VERSION 5.8 ;
BUSBITCHARS "[]" ;
DIVIDERCHAR "/" ;
UNITS
    DATABASE MICRONS 1000 ;
END UNITS

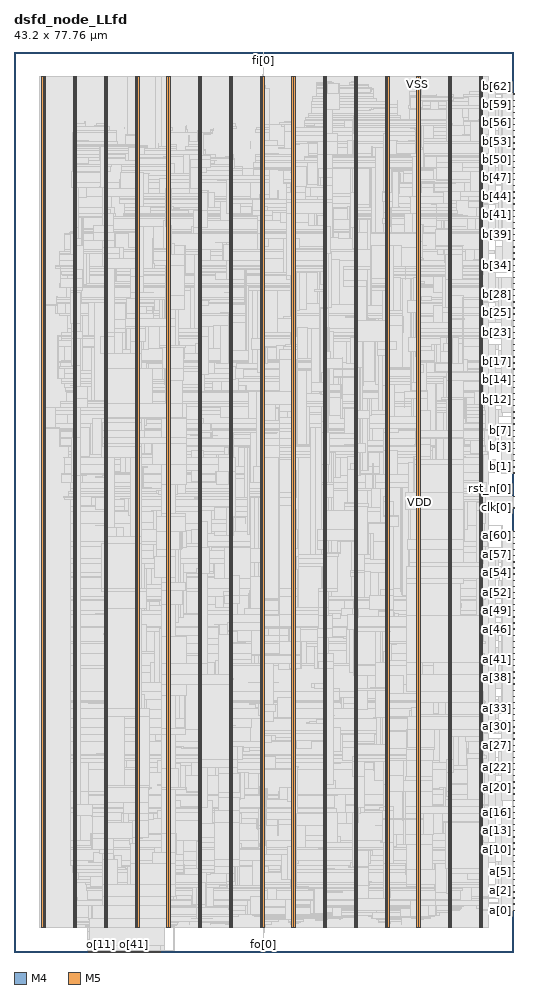
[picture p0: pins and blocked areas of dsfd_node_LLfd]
MACRO dsfd_node_LLfd
  FOREIGN dsfd_node_LLfd 0 0 ;
  CLASS BLOCK ;
  SIZE 43.2 BY 77.76 ;
  PIN a[0]
    DIRECTION INPUT ;
    USE SIGNAL ;
    PORT
      LAYER M4 ;
        RECT  43.116 3.6 43.2 3.624 ;
    END
  END a[0]
  PIN a[10]
    DIRECTION INPUT ;
    USE SIGNAL ;
    PORT
      LAYER M4 ;
        RECT  43.116 8.88 43.2 8.904 ;
    END
  END a[10]
  PIN a[11]
    DIRECTION INPUT ;
    USE SIGNAL ;
    PORT
      LAYER M4 ;
        RECT  43.116 9.408 43.2 9.432 ;
    END
  END a[11]
  PIN a[12]
    DIRECTION INPUT ;
    USE SIGNAL ;
    PORT
      LAYER M4 ;
        RECT  43.116 9.936 43.2 9.96 ;
    END
  END a[12]
  PIN a[13]
    DIRECTION INPUT ;
    USE SIGNAL ;
    PORT
      LAYER M4 ;
        RECT  43.116 10.464 43.2 10.488 ;
    END
  END a[13]
  PIN a[14]
    DIRECTION INPUT ;
    USE SIGNAL ;
    PORT
      LAYER M4 ;
        RECT  43.116 10.992 43.2 11.016 ;
    END
  END a[14]
  PIN a[15]
    DIRECTION INPUT ;
    USE SIGNAL ;
    PORT
      LAYER M4 ;
        RECT  43.116 11.52 43.2 11.544 ;
    END
  END a[15]
  PIN a[16]
    DIRECTION INPUT ;
    USE SIGNAL ;
    PORT
      LAYER M4 ;
        RECT  43.116 12.048 43.2 12.072 ;
    END
  END a[16]
  PIN a[17]
    DIRECTION INPUT ;
    USE SIGNAL ;
    PORT
      LAYER M4 ;
        RECT  43.116 12.576 43.2 12.6 ;
    END
  END a[17]
  PIN a[18]
    DIRECTION INPUT ;
    USE SIGNAL ;
    PORT
      LAYER M4 ;
        RECT  43.116 13.104 43.2 13.128 ;
    END
  END a[18]
  PIN a[19]
    DIRECTION INPUT ;
    USE SIGNAL ;
    PORT
      LAYER M4 ;
        RECT  43.116 13.632 43.2 13.656 ;
    END
  END a[19]
  PIN a[1]
    DIRECTION INPUT ;
    USE SIGNAL ;
    PORT
      LAYER M4 ;
        RECT  43.116 4.128 43.2 4.152 ;
    END
  END a[1]
  PIN a[20]
    DIRECTION INPUT ;
    USE SIGNAL ;
    PORT
      LAYER M4 ;
        RECT  43.116 14.16 43.2 14.184 ;
    END
  END a[20]
  PIN a[21]
    DIRECTION INPUT ;
    USE SIGNAL ;
    PORT
      LAYER M4 ;
        RECT  43.116 14.688 43.2 14.712 ;
    END
  END a[21]
  PIN a[22]
    DIRECTION INPUT ;
    USE SIGNAL ;
    PORT
      LAYER M4 ;
        RECT  43.116 15.216 43.2 15.24 ;
    END
  END a[22]
  PIN a[23]
    DIRECTION INPUT ;
    USE SIGNAL ;
    PORT
      LAYER M4 ;
        RECT  43.116 15.744 43.2 15.768 ;
    END
  END a[23]
  PIN a[24]
    DIRECTION INPUT ;
    USE SIGNAL ;
    PORT
      LAYER M4 ;
        RECT  43.116 16.272 43.2 16.296 ;
    END
  END a[24]
  PIN a[25]
    DIRECTION INPUT ;
    USE SIGNAL ;
    PORT
      LAYER M4 ;
        RECT  43.116 16.8 43.2 16.824 ;
    END
  END a[25]
  PIN a[26]
    DIRECTION INPUT ;
    USE SIGNAL ;
    PORT
      LAYER M4 ;
        RECT  43.116 17.328 43.2 17.352 ;
    END
  END a[26]
  PIN a[27]
    DIRECTION INPUT ;
    USE SIGNAL ;
    PORT
      LAYER M4 ;
        RECT  43.116 17.856 43.2 17.88 ;
    END
  END a[27]
  PIN a[28]
    DIRECTION INPUT ;
    USE SIGNAL ;
    PORT
      LAYER M4 ;
        RECT  43.116 18.384 43.2 18.408 ;
    END
  END a[28]
  PIN a[29]
    DIRECTION INPUT ;
    USE SIGNAL ;
    PORT
      LAYER M4 ;
        RECT  43.116 18.912 43.2 18.936 ;
    END
  END a[29]
  PIN a[2]
    DIRECTION INPUT ;
    USE SIGNAL ;
    PORT
      LAYER M4 ;
        RECT  43.116 4.656 43.2 4.68 ;
    END
  END a[2]
  PIN a[30]
    DIRECTION INPUT ;
    USE SIGNAL ;
    PORT
      LAYER M4 ;
        RECT  43.116 19.44 43.2 19.464 ;
    END
  END a[30]
  PIN a[31]
    DIRECTION INPUT ;
    USE SIGNAL ;
    PORT
      LAYER M4 ;
        RECT  43.116 19.968 43.2 19.992 ;
    END
  END a[31]
  PIN a[32]
    DIRECTION INPUT ;
    USE SIGNAL ;
    PORT
      LAYER M4 ;
        RECT  43.116 20.496 43.2 20.52 ;
    END
  END a[32]
  PIN a[33]
    DIRECTION INPUT ;
    USE SIGNAL ;
    PORT
      LAYER M4 ;
        RECT  43.116 21.024 43.2 21.048 ;
    END
  END a[33]
  PIN a[34]
    DIRECTION INPUT ;
    USE SIGNAL ;
    PORT
      LAYER M4 ;
        RECT  43.116 21.552 43.2 21.576 ;
    END
  END a[34]
  PIN a[35]
    DIRECTION INPUT ;
    USE SIGNAL ;
    PORT
      LAYER M4 ;
        RECT  43.116 22.08 43.2 22.104 ;
    END
  END a[35]
  PIN a[36]
    DIRECTION INPUT ;
    USE SIGNAL ;
    PORT
      LAYER M4 ;
        RECT  43.116 22.608 43.2 22.632 ;
    END
  END a[36]
  PIN a[37]
    DIRECTION INPUT ;
    USE SIGNAL ;
    PORT
      LAYER M4 ;
        RECT  43.116 23.136 43.2 23.16 ;
    END
  END a[37]
  PIN a[38]
    DIRECTION INPUT ;
    USE SIGNAL ;
    PORT
      LAYER M4 ;
        RECT  43.116 23.664 43.2 23.688 ;
    END
  END a[38]
  PIN a[39]
    DIRECTION INPUT ;
    USE SIGNAL ;
    PORT
      LAYER M4 ;
        RECT  43.116 24.192 43.2 24.216 ;
    END
  END a[39]
  PIN a[3]
    DIRECTION INPUT ;
    USE SIGNAL ;
    PORT
      LAYER M4 ;
        RECT  43.116 5.184 43.2 5.208 ;
    END
  END a[3]
  PIN a[40]
    DIRECTION INPUT ;
    USE SIGNAL ;
    PORT
      LAYER M4 ;
        RECT  43.116 24.72 43.2 24.744 ;
    END
  END a[40]
  PIN a[41]
    DIRECTION INPUT ;
    USE SIGNAL ;
    PORT
      LAYER M4 ;
        RECT  43.116 25.248 43.2 25.272 ;
    END
  END a[41]
  PIN a[42]
    DIRECTION INPUT ;
    USE SIGNAL ;
    PORT
      LAYER M4 ;
        RECT  43.116 25.776 43.2 25.8 ;
    END
  END a[42]
  PIN a[43]
    DIRECTION INPUT ;
    USE SIGNAL ;
    PORT
      LAYER M4 ;
        RECT  43.116 26.304 43.2 26.328 ;
    END
  END a[43]
  PIN a[44]
    DIRECTION INPUT ;
    USE SIGNAL ;
    PORT
      LAYER M4 ;
        RECT  43.116 26.832 43.2 26.856 ;
    END
  END a[44]
  PIN a[45]
    DIRECTION INPUT ;
    USE SIGNAL ;
    PORT
      LAYER M4 ;
        RECT  43.116 27.36 43.2 27.384 ;
    END
  END a[45]
  PIN a[46]
    DIRECTION INPUT ;
    USE SIGNAL ;
    PORT
      LAYER M4 ;
        RECT  43.116 27.888 43.2 27.912 ;
    END
  END a[46]
  PIN a[47]
    DIRECTION INPUT ;
    USE SIGNAL ;
    PORT
      LAYER M4 ;
        RECT  43.116 28.416 43.2 28.44 ;
    END
  END a[47]
  PIN a[48]
    DIRECTION INPUT ;
    USE SIGNAL ;
    PORT
      LAYER M4 ;
        RECT  43.116 28.944 43.2 28.968 ;
    END
  END a[48]
  PIN a[49]
    DIRECTION INPUT ;
    USE SIGNAL ;
    PORT
      LAYER M4 ;
        RECT  43.116 29.472 43.2 29.496 ;
    END
  END a[49]
  PIN a[4]
    DIRECTION INPUT ;
    USE SIGNAL ;
    PORT
      LAYER M4 ;
        RECT  43.116 5.712 43.2 5.736 ;
    END
  END a[4]
  PIN a[50]
    DIRECTION INPUT ;
    USE SIGNAL ;
    PORT
      LAYER M4 ;
        RECT  43.116 30 43.2 30.024 ;
    END
  END a[50]
  PIN a[51]
    DIRECTION INPUT ;
    USE SIGNAL ;
    PORT
      LAYER M4 ;
        RECT  43.116 30.528 43.2 30.552 ;
    END
  END a[51]
  PIN a[52]
    DIRECTION INPUT ;
    USE SIGNAL ;
    PORT
      LAYER M4 ;
        RECT  43.116 31.056 43.2 31.08 ;
    END
  END a[52]
  PIN a[53]
    DIRECTION INPUT ;
    USE SIGNAL ;
    PORT
      LAYER M4 ;
        RECT  43.116 31.584 43.2 31.608 ;
    END
  END a[53]
  PIN a[54]
    DIRECTION INPUT ;
    USE SIGNAL ;
    PORT
      LAYER M4 ;
        RECT  43.116 32.112 43.2 32.136 ;
    END
  END a[54]
  PIN a[55]
    DIRECTION INPUT ;
    USE SIGNAL ;
    PORT
      LAYER M4 ;
        RECT  43.116 32.64 43.2 32.664 ;
    END
  END a[55]
  PIN a[56]
    DIRECTION INPUT ;
    USE SIGNAL ;
    PORT
      LAYER M4 ;
        RECT  43.116 33.168 43.2 33.192 ;
    END
  END a[56]
  PIN a[57]
    DIRECTION INPUT ;
    USE SIGNAL ;
    PORT
      LAYER M4 ;
        RECT  43.116 33.696 43.2 33.72 ;
    END
  END a[57]
  PIN a[58]
    DIRECTION INPUT ;
    USE SIGNAL ;
    PORT
      LAYER M4 ;
        RECT  43.116 34.224 43.2 34.248 ;
    END
  END a[58]
  PIN a[59]
    DIRECTION INPUT ;
    USE SIGNAL ;
    PORT
      LAYER M4 ;
        RECT  43.116 34.752 43.2 34.776 ;
    END
  END a[59]
  PIN a[5]
    DIRECTION INPUT ;
    USE SIGNAL ;
    PORT
      LAYER M4 ;
        RECT  43.116 6.24 43.2 6.264 ;
    END
  END a[5]
  PIN a[60]
    DIRECTION INPUT ;
    USE SIGNAL ;
    PORT
      LAYER M4 ;
        RECT  43.116 35.28 43.2 35.304 ;
    END
  END a[60]
  PIN a[61]
    DIRECTION INPUT ;
    USE SIGNAL ;
    PORT
      LAYER M4 ;
        RECT  43.116 35.808 43.2 35.832 ;
    END
  END a[61]
  PIN a[62]
    DIRECTION INPUT ;
    USE SIGNAL ;
    PORT
      LAYER M4 ;
        RECT  43.116 36.336 43.2 36.36 ;
    END
  END a[62]
  PIN a[6]
    DIRECTION INPUT ;
    USE SIGNAL ;
    PORT
      LAYER M4 ;
        RECT  43.116 6.768 43.2 6.792 ;
    END
  END a[6]
  PIN a[7]
    DIRECTION INPUT ;
    USE SIGNAL ;
    PORT
      LAYER M4 ;
        RECT  43.116 7.296 43.2 7.32 ;
    END
  END a[7]
  PIN a[8]
    DIRECTION INPUT ;
    USE SIGNAL ;
    PORT
      LAYER M4 ;
        RECT  43.116 7.824 43.2 7.848 ;
    END
  END a[8]
  PIN a[9]
    DIRECTION INPUT ;
    USE SIGNAL ;
    PORT
      LAYER M4 ;
        RECT  43.116 8.352 43.2 8.376 ;
    END
  END a[9]
  PIN b[0]
    DIRECTION INPUT ;
    USE SIGNAL ;
    PORT
      LAYER M4 ;
        RECT  43.116 41.376 43.2 41.4 ;
    END
  END b[0]
  PIN b[10]
    DIRECTION INPUT ;
    USE SIGNAL ;
    PORT
      LAYER M4 ;
        RECT  43.116 46.656 43.2 46.68 ;
    END
  END b[10]
  PIN b[11]
    DIRECTION INPUT ;
    USE SIGNAL ;
    PORT
      LAYER M4 ;
        RECT  43.116 47.184 43.2 47.208 ;
    END
  END b[11]
  PIN b[12]
    DIRECTION INPUT ;
    USE SIGNAL ;
    PORT
      LAYER M4 ;
        RECT  43.116 47.712 43.2 47.736 ;
    END
  END b[12]
  PIN b[13]
    DIRECTION INPUT ;
    USE SIGNAL ;
    PORT
      LAYER M4 ;
        RECT  43.116 48.24 43.2 48.264 ;
    END
  END b[13]
  PIN b[14]
    DIRECTION INPUT ;
    USE SIGNAL ;
    PORT
      LAYER M4 ;
        RECT  43.116 48.768 43.2 48.792 ;
    END
  END b[14]
  PIN b[15]
    DIRECTION INPUT ;
    USE SIGNAL ;
    PORT
      LAYER M4 ;
        RECT  43.116 49.296 43.2 49.32 ;
    END
  END b[15]
  PIN b[16]
    DIRECTION INPUT ;
    USE SIGNAL ;
    PORT
      LAYER M4 ;
        RECT  43.116 49.824 43.2 49.848 ;
    END
  END b[16]
  PIN b[17]
    DIRECTION INPUT ;
    USE SIGNAL ;
    PORT
      LAYER M4 ;
        RECT  43.116 50.352 43.2 50.376 ;
    END
  END b[17]
  PIN b[18]
    DIRECTION INPUT ;
    USE SIGNAL ;
    PORT
      LAYER M4 ;
        RECT  43.116 50.88 43.2 50.904 ;
    END
  END b[18]
  PIN b[19]
    DIRECTION INPUT ;
    USE SIGNAL ;
    PORT
      LAYER M4 ;
        RECT  43.116 51.408 43.2 51.432 ;
    END
  END b[19]
  PIN b[1]
    DIRECTION INPUT ;
    USE SIGNAL ;
    PORT
      LAYER M4 ;
        RECT  43.116 41.904 43.2 41.928 ;
    END
  END b[1]
  PIN b[20]
    DIRECTION INPUT ;
    USE SIGNAL ;
    PORT
      LAYER M4 ;
        RECT  43.116 51.936 43.2 51.96 ;
    END
  END b[20]
  PIN b[21]
    DIRECTION INPUT ;
    USE SIGNAL ;
    PORT
      LAYER M4 ;
        RECT  43.116 52.464 43.2 52.488 ;
    END
  END b[21]
  PIN b[22]
    DIRECTION INPUT ;
    USE SIGNAL ;
    PORT
      LAYER M4 ;
        RECT  43.116 52.992 43.2 53.016 ;
    END
  END b[22]
  PIN b[23]
    DIRECTION INPUT ;
    USE SIGNAL ;
    PORT
      LAYER M4 ;
        RECT  43.116 53.52 43.2 53.544 ;
    END
  END b[23]
  PIN b[24]
    DIRECTION INPUT ;
    USE SIGNAL ;
    PORT
      LAYER M4 ;
        RECT  43.116 54.048 43.2 54.072 ;
    END
  END b[24]
  PIN b[25]
    DIRECTION INPUT ;
    USE SIGNAL ;
    PORT
      LAYER M4 ;
        RECT  43.116 54.576 43.2 54.6 ;
    END
  END b[25]
  PIN b[26]
    DIRECTION INPUT ;
    USE SIGNAL ;
    PORT
      LAYER M4 ;
        RECT  43.116 55.104 43.2 55.128 ;
    END
  END b[26]
  PIN b[27]
    DIRECTION INPUT ;
    USE SIGNAL ;
    PORT
      LAYER M4 ;
        RECT  43.116 55.632 43.2 55.656 ;
    END
  END b[27]
  PIN b[28]
    DIRECTION INPUT ;
    USE SIGNAL ;
    PORT
      LAYER M4 ;
        RECT  43.116 56.16 43.2 56.184 ;
    END
  END b[28]
  PIN b[29]
    DIRECTION INPUT ;
    USE SIGNAL ;
    PORT
      LAYER M4 ;
        RECT  43.116 56.688 43.2 56.712 ;
    END
  END b[29]
  PIN b[2]
    DIRECTION INPUT ;
    USE SIGNAL ;
    PORT
      LAYER M4 ;
        RECT  43.116 42.432 43.2 42.456 ;
    END
  END b[2]
  PIN b[30]
    DIRECTION INPUT ;
    USE SIGNAL ;
    PORT
      LAYER M4 ;
        RECT  43.116 57.216 43.2 57.24 ;
    END
  END b[30]
  PIN b[31]
    DIRECTION INPUT ;
    USE SIGNAL ;
    PORT
      LAYER M4 ;
        RECT  43.116 57.744 43.2 57.768 ;
    END
  END b[31]
  PIN b[32]
    DIRECTION INPUT ;
    USE SIGNAL ;
    PORT
      LAYER M4 ;
        RECT  43.116 58.272 43.2 58.296 ;
    END
  END b[32]
  PIN b[33]
    DIRECTION INPUT ;
    USE SIGNAL ;
    PORT
      LAYER M4 ;
        RECT  43.116 58.8 43.2 58.824 ;
    END
  END b[33]
  PIN b[34]
    DIRECTION INPUT ;
    USE SIGNAL ;
    PORT
      LAYER M4 ;
        RECT  43.116 59.328 43.2 59.352 ;
    END
  END b[34]
  PIN b[35]
    DIRECTION INPUT ;
    USE SIGNAL ;
    PORT
      LAYER M4 ;
        RECT  43.116 59.856 43.2 59.88 ;
    END
  END b[35]
  PIN b[36]
    DIRECTION INPUT ;
    USE SIGNAL ;
    PORT
      LAYER M4 ;
        RECT  43.116 60.384 43.2 60.408 ;
    END
  END b[36]
  PIN b[37]
    DIRECTION INPUT ;
    USE SIGNAL ;
    PORT
      LAYER M4 ;
        RECT  43.116 60.912 43.2 60.936 ;
    END
  END b[37]
  PIN b[38]
    DIRECTION INPUT ;
    USE SIGNAL ;
    PORT
      LAYER M4 ;
        RECT  43.116 61.44 43.2 61.464 ;
    END
  END b[38]
  PIN b[39]
    DIRECTION INPUT ;
    USE SIGNAL ;
    PORT
      LAYER M4 ;
        RECT  43.116 61.968 43.2 61.992 ;
    END
  END b[39]
  PIN b[3]
    DIRECTION INPUT ;
    USE SIGNAL ;
    PORT
      LAYER M4 ;
        RECT  43.116 42.96 43.2 42.984 ;
    END
  END b[3]
  PIN b[40]
    DIRECTION INPUT ;
    USE SIGNAL ;
    PORT
      LAYER M4 ;
        RECT  43.116 62.496 43.2 62.52 ;
    END
  END b[40]
  PIN b[41]
    DIRECTION INPUT ;
    USE SIGNAL ;
    PORT
      LAYER M4 ;
        RECT  43.116 63.024 43.2 63.048 ;
    END
  END b[41]
  PIN b[42]
    DIRECTION INPUT ;
    USE SIGNAL ;
    PORT
      LAYER M4 ;
        RECT  43.116 63.552 43.2 63.576 ;
    END
  END b[42]
  PIN b[43]
    DIRECTION INPUT ;
    USE SIGNAL ;
    PORT
      LAYER M4 ;
        RECT  43.116 64.08 43.2 64.104 ;
    END
  END b[43]
  PIN b[44]
    DIRECTION INPUT ;
    USE SIGNAL ;
    PORT
      LAYER M4 ;
        RECT  43.116 64.608 43.2 64.632 ;
    END
  END b[44]
  PIN b[45]
    DIRECTION INPUT ;
    USE SIGNAL ;
    PORT
      LAYER M4 ;
        RECT  43.116 65.136 43.2 65.16 ;
    END
  END b[45]
  PIN b[46]
    DIRECTION INPUT ;
    USE SIGNAL ;
    PORT
      LAYER M4 ;
        RECT  43.116 65.664 43.2 65.688 ;
    END
  END b[46]
  PIN b[47]
    DIRECTION INPUT ;
    USE SIGNAL ;
    PORT
      LAYER M4 ;
        RECT  43.116 66.192 43.2 66.216 ;
    END
  END b[47]
  PIN b[48]
    DIRECTION INPUT ;
    USE SIGNAL ;
    PORT
      LAYER M4 ;
        RECT  43.116 66.72 43.2 66.744 ;
    END
  END b[48]
  PIN b[49]
    DIRECTION INPUT ;
    USE SIGNAL ;
    PORT
      LAYER M4 ;
        RECT  43.116 67.248 43.2 67.272 ;
    END
  END b[49]
  PIN b[4]
    DIRECTION INPUT ;
    USE SIGNAL ;
    PORT
      LAYER M4 ;
        RECT  43.116 43.488 43.2 43.512 ;
    END
  END b[4]
  PIN b[50]
    DIRECTION INPUT ;
    USE SIGNAL ;
    PORT
      LAYER M4 ;
        RECT  43.116 67.776 43.2 67.8 ;
    END
  END b[50]
  PIN b[51]
    DIRECTION INPUT ;
    USE SIGNAL ;
    PORT
      LAYER M4 ;
        RECT  43.116 68.304 43.2 68.328 ;
    END
  END b[51]
  PIN b[52]
    DIRECTION INPUT ;
    USE SIGNAL ;
    PORT
      LAYER M4 ;
        RECT  43.116 68.832 43.2 68.856 ;
    END
  END b[52]
  PIN b[53]
    DIRECTION INPUT ;
    USE SIGNAL ;
    PORT
      LAYER M4 ;
        RECT  43.116 69.36 43.2 69.384 ;
    END
  END b[53]
  PIN b[54]
    DIRECTION INPUT ;
    USE SIGNAL ;
    PORT
      LAYER M4 ;
        RECT  43.116 69.888 43.2 69.912 ;
    END
  END b[54]
  PIN b[55]
    DIRECTION INPUT ;
    USE SIGNAL ;
    PORT
      LAYER M4 ;
        RECT  43.116 70.416 43.2 70.44 ;
    END
  END b[55]
  PIN b[56]
    DIRECTION INPUT ;
    USE SIGNAL ;
    PORT
      LAYER M4 ;
        RECT  43.116 70.944 43.2 70.968 ;
    END
  END b[56]
  PIN b[57]
    DIRECTION INPUT ;
    USE SIGNAL ;
    PORT
      LAYER M4 ;
        RECT  43.116 71.472 43.2 71.496 ;
    END
  END b[57]
  PIN b[58]
    DIRECTION INPUT ;
    USE SIGNAL ;
    PORT
      LAYER M4 ;
        RECT  43.116 72 43.2 72.024 ;
    END
  END b[58]
  PIN b[59]
    DIRECTION INPUT ;
    USE SIGNAL ;
    PORT
      LAYER M4 ;
        RECT  43.116 72.528 43.2 72.552 ;
    END
  END b[59]
  PIN b[5]
    DIRECTION INPUT ;
    USE SIGNAL ;
    PORT
      LAYER M4 ;
        RECT  43.116 44.016 43.2 44.04 ;
    END
  END b[5]
  PIN b[60]
    DIRECTION INPUT ;
    USE SIGNAL ;
    PORT
      LAYER M4 ;
        RECT  43.116 73.056 43.2 73.08 ;
    END
  END b[60]
  PIN b[61]
    DIRECTION INPUT ;
    USE SIGNAL ;
    PORT
      LAYER M4 ;
        RECT  43.116 73.584 43.2 73.608 ;
    END
  END b[61]
  PIN b[62]
    DIRECTION INPUT ;
    USE SIGNAL ;
    PORT
      LAYER M4 ;
        RECT  43.116 74.112 43.2 74.136 ;
    END
  END b[62]
  PIN b[6]
    DIRECTION INPUT ;
    USE SIGNAL ;
    PORT
      LAYER M4 ;
        RECT  43.116 44.544 43.2 44.568 ;
    END
  END b[6]
  PIN b[7]
    DIRECTION INPUT ;
    USE SIGNAL ;
    PORT
      LAYER M4 ;
        RECT  43.116 45.072 43.2 45.096 ;
    END
  END b[7]
  PIN b[8]
    DIRECTION INPUT ;
    USE SIGNAL ;
    PORT
      LAYER M4 ;
        RECT  43.116 45.6 43.2 45.624 ;
    END
  END b[8]
  PIN b[9]
    DIRECTION INPUT ;
    USE SIGNAL ;
    PORT
      LAYER M4 ;
        RECT  43.116 46.128 43.2 46.152 ;
    END
  END b[9]
  PIN clk[0]
    DIRECTION INPUT ;
    USE SIGNAL ;
    PORT
      LAYER M4 ;
        RECT  43.116 38.352 43.2 38.376 ;
    END
  END clk[0]
  PIN fi[0]
    DIRECTION INPUT ;
    USE SIGNAL ;
    PORT
      LAYER M5 ;
        RECT  21.552 77.676 21.576 77.76 ;
    END
  END fi[0]
  PIN fo[0]
    DIRECTION OUTPUT ;
    USE SIGNAL ;
    PORT
      LAYER M5 ;
        RECT  21.552 0 21.576 0.084 ;
    END
  END fo[0]
  PIN o[0]
    DIRECTION OUTPUT ;
    USE SIGNAL ;
    PORT
      LAYER M5 ;
        RECT  6.432 0 6.456 0.084 ;
    END
  END o[0]
  PIN o[10]
    DIRECTION OUTPUT ;
    USE SIGNAL ;
    PORT
      LAYER M5 ;
        RECT  7.392 0 7.416 0.084 ;
    END
  END o[10]
  PIN o[11]
    DIRECTION OUTPUT ;
    USE SIGNAL ;
    PORT
      LAYER M5 ;
        RECT  7.488 0 7.512 0.084 ;
    END
  END o[11]
  PIN o[12]
    DIRECTION OUTPUT ;
    USE SIGNAL ;
    PORT
      LAYER M5 ;
        RECT  7.584 0 7.608 0.084 ;
    END
  END o[12]
  PIN o[13]
    DIRECTION OUTPUT ;
    USE SIGNAL ;
    PORT
      LAYER M5 ;
        RECT  7.68 0 7.704 0.084 ;
    END
  END o[13]
  PIN o[14]
    DIRECTION OUTPUT ;
    USE SIGNAL ;
    PORT
      LAYER M5 ;
        RECT  7.776 0 7.8 0.084 ;
    END
  END o[14]
  PIN o[15]
    DIRECTION OUTPUT ;
    USE SIGNAL ;
    PORT
      LAYER M5 ;
        RECT  7.872 0 7.896 0.084 ;
    END
  END o[15]
  PIN o[16]
    DIRECTION OUTPUT ;
    USE SIGNAL ;
    PORT
      LAYER M5 ;
        RECT  7.968 0 7.992 0.084 ;
    END
  END o[16]
  PIN o[17]
    DIRECTION OUTPUT ;
    USE SIGNAL ;
    PORT
      LAYER M5 ;
        RECT  8.064 0 8.088 0.084 ;
    END
  END o[17]
  PIN o[18]
    DIRECTION OUTPUT ;
    USE SIGNAL ;
    PORT
      LAYER M5 ;
        RECT  8.16 0 8.184 0.084 ;
    END
  END o[18]
  PIN o[19]
    DIRECTION OUTPUT ;
    USE SIGNAL ;
    PORT
      LAYER M5 ;
        RECT  8.256 0 8.28 0.084 ;
    END
  END o[19]
  PIN o[1]
    DIRECTION OUTPUT ;
    USE SIGNAL ;
    PORT
      LAYER M5 ;
        RECT  6.528 0 6.552 0.084 ;
    END
  END o[1]
  PIN o[20]
    DIRECTION OUTPUT ;
    USE SIGNAL ;
    PORT
      LAYER M5 ;
        RECT  8.352 0 8.376 0.084 ;
    END
  END o[20]
  PIN o[21]
    DIRECTION OUTPUT ;
    USE SIGNAL ;
    PORT
      LAYER M5 ;
        RECT  8.448 0 8.472 0.084 ;
    END
  END o[21]
  PIN o[22]
    DIRECTION OUTPUT ;
    USE SIGNAL ;
    PORT
      LAYER M5 ;
        RECT  8.544 0 8.568 0.084 ;
    END
  END o[22]
  PIN o[23]
    DIRECTION OUTPUT ;
    USE SIGNAL ;
    PORT
      LAYER M5 ;
        RECT  8.64 0 8.664 0.084 ;
    END
  END o[23]
  PIN o[24]
    DIRECTION OUTPUT ;
    USE SIGNAL ;
    PORT
      LAYER M5 ;
        RECT  8.736 0 8.76 0.084 ;
    END
  END o[24]
  PIN o[25]
    DIRECTION OUTPUT ;
    USE SIGNAL ;
    PORT
      LAYER M5 ;
        RECT  8.832 0 8.856 0.084 ;
    END
  END o[25]
  PIN o[26]
    DIRECTION OUTPUT ;
    USE SIGNAL ;
    PORT
      LAYER M5 ;
        RECT  8.928 0 8.952 0.084 ;
    END
  END o[26]
  PIN o[27]
    DIRECTION OUTPUT ;
    USE SIGNAL ;
    PORT
      LAYER M5 ;
        RECT  9.024 0 9.048 0.084 ;
    END
  END o[27]
  PIN o[28]
    DIRECTION OUTPUT ;
    USE SIGNAL ;
    PORT
      LAYER M5 ;
        RECT  9.12 0 9.144 0.084 ;
    END
  END o[28]
  PIN o[29]
    DIRECTION OUTPUT ;
    USE SIGNAL ;
    PORT
      LAYER M5 ;
        RECT  9.216 0 9.24 0.084 ;
    END
  END o[29]
  PIN o[2]
    DIRECTION OUTPUT ;
    USE SIGNAL ;
    PORT
      LAYER M5 ;
        RECT  6.624 0 6.648 0.084 ;
    END
  END o[2]
  PIN o[30]
    DIRECTION OUTPUT ;
    USE SIGNAL ;
    PORT
      LAYER M5 ;
        RECT  9.312 0 9.336 0.084 ;
    END
  END o[30]
  PIN o[31]
    DIRECTION OUTPUT ;
    USE SIGNAL ;
    PORT
      LAYER M5 ;
        RECT  9.408 0 9.432 0.084 ;
    END
  END o[31]
  PIN o[32]
    DIRECTION OUTPUT ;
    USE SIGNAL ;
    PORT
      LAYER M5 ;
        RECT  9.504 0 9.528 0.084 ;
    END
  END o[32]
  PIN o[33]
    DIRECTION OUTPUT ;
    USE SIGNAL ;
    PORT
      LAYER M5 ;
        RECT  9.6 0 9.624 0.084 ;
    END
  END o[33]
  PIN o[34]
    DIRECTION OUTPUT ;
    USE SIGNAL ;
    PORT
      LAYER M5 ;
        RECT  9.696 0 9.72 0.084 ;
    END
  END o[34]
  PIN o[35]
    DIRECTION OUTPUT ;
    USE SIGNAL ;
    PORT
      LAYER M5 ;
        RECT  9.792 0 9.816 0.084 ;
    END
  END o[35]
  PIN o[36]
    DIRECTION OUTPUT ;
    USE SIGNAL ;
    PORT
      LAYER M5 ;
        RECT  9.888 0 9.912 0.084 ;
    END
  END o[36]
  PIN o[37]
    DIRECTION OUTPUT ;
    USE SIGNAL ;
    PORT
      LAYER M5 ;
        RECT  9.984 0 10.008 0.084 ;
    END
  END o[37]
  PIN o[38]
    DIRECTION OUTPUT ;
    USE SIGNAL ;
    PORT
      LAYER M5 ;
        RECT  10.08 0 10.104 0.084 ;
    END
  END o[38]
  PIN o[39]
    DIRECTION OUTPUT ;
    USE SIGNAL ;
    PORT
      LAYER M5 ;
        RECT  10.176 0 10.2 0.084 ;
    END
  END o[39]
  PIN o[3]
    DIRECTION OUTPUT ;
    USE SIGNAL ;
    PORT
      LAYER M5 ;
        RECT  6.72 0 6.744 0.084 ;
    END
  END o[3]
  PIN o[40]
    DIRECTION OUTPUT ;
    USE SIGNAL ;
    PORT
      LAYER M5 ;
        RECT  10.272 0 10.296 0.084 ;
    END
  END o[40]
  PIN o[41]
    DIRECTION OUTPUT ;
    USE SIGNAL ;
    PORT
      LAYER M5 ;
        RECT  10.368 0 10.392 0.084 ;
    END
  END o[41]
  PIN o[42]
    DIRECTION OUTPUT ;
    USE SIGNAL ;
    PORT
      LAYER M5 ;
        RECT  10.464 0 10.488 0.084 ;
    END
  END o[42]
  PIN o[43]
    DIRECTION OUTPUT ;
    USE SIGNAL ;
    PORT
      LAYER M5 ;
        RECT  10.56 0 10.584 0.084 ;
    END
  END o[43]
  PIN o[44]
    DIRECTION OUTPUT ;
    USE SIGNAL ;
    PORT
      LAYER M5 ;
        RECT  10.656 0 10.68 0.084 ;
    END
  END o[44]
  PIN o[45]
    DIRECTION OUTPUT ;
    USE SIGNAL ;
    PORT
      LAYER M5 ;
        RECT  10.752 0 10.776 0.084 ;
    END
  END o[45]
  PIN o[46]
    DIRECTION OUTPUT ;
    USE SIGNAL ;
    PORT
      LAYER M5 ;
        RECT  10.848 0 10.872 0.084 ;
    END
  END o[46]
  PIN o[47]
    DIRECTION OUTPUT ;
    USE SIGNAL ;
    PORT
      LAYER M5 ;
        RECT  10.944 0 10.968 0.084 ;
    END
  END o[47]
  PIN o[48]
    DIRECTION OUTPUT ;
    USE SIGNAL ;
    PORT
      LAYER M5 ;
        RECT  11.04 0 11.064 0.084 ;
    END
  END o[48]
  PIN o[49]
    DIRECTION OUTPUT ;
    USE SIGNAL ;
    PORT
      LAYER M5 ;
        RECT  11.136 0 11.16 0.084 ;
    END
  END o[49]
  PIN o[4]
    DIRECTION OUTPUT ;
    USE SIGNAL ;
    PORT
      LAYER M5 ;
        RECT  6.816 0 6.84 0.084 ;
    END
  END o[4]
  PIN o[50]
    DIRECTION OUTPUT ;
    USE SIGNAL ;
    PORT
      LAYER M5 ;
        RECT  11.232 0 11.256 0.084 ;
    END
  END o[50]
  PIN o[51]
    DIRECTION OUTPUT ;
    USE SIGNAL ;
    PORT
      LAYER M5 ;
        RECT  11.328 0 11.352 0.084 ;
    END
  END o[51]
  PIN o[52]
    DIRECTION OUTPUT ;
    USE SIGNAL ;
    PORT
      LAYER M5 ;
        RECT  11.424 0 11.448 0.084 ;
    END
  END o[52]
  PIN o[53]
    DIRECTION OUTPUT ;
    USE SIGNAL ;
    PORT
      LAYER M5 ;
        RECT  11.52 0 11.544 0.084 ;
    END
  END o[53]
  PIN o[54]
    DIRECTION OUTPUT ;
    USE SIGNAL ;
    PORT
      LAYER M5 ;
        RECT  11.616 0 11.64 0.084 ;
    END
  END o[54]
  PIN o[55]
    DIRECTION OUTPUT ;
    USE SIGNAL ;
    PORT
      LAYER M5 ;
        RECT  11.712 0 11.736 0.084 ;
    END
  END o[55]
  PIN o[56]
    DIRECTION OUTPUT ;
    USE SIGNAL ;
    PORT
      LAYER M5 ;
        RECT  11.808 0 11.832 0.084 ;
    END
  END o[56]
  PIN o[57]
    DIRECTION OUTPUT ;
    USE SIGNAL ;
    PORT
      LAYER M5 ;
        RECT  11.904 0 11.928 0.084 ;
    END
  END o[57]
  PIN o[58]
    DIRECTION OUTPUT ;
    USE SIGNAL ;
    PORT
      LAYER M5 ;
        RECT  12 0 12.024 0.084 ;
    END
  END o[58]
  PIN o[59]
    DIRECTION OUTPUT ;
    USE SIGNAL ;
    PORT
      LAYER M5 ;
        RECT  12.096 0 12.12 0.084 ;
    END
  END o[59]
  PIN o[5]
    DIRECTION OUTPUT ;
    USE SIGNAL ;
    PORT
      LAYER M5 ;
        RECT  6.912 0 6.936 0.084 ;
    END
  END o[5]
  PIN o[60]
    DIRECTION OUTPUT ;
    USE SIGNAL ;
    PORT
      LAYER M5 ;
        RECT  12.192 0 12.216 0.084 ;
    END
  END o[60]
  PIN o[61]
    DIRECTION OUTPUT ;
    USE SIGNAL ;
    PORT
      LAYER M5 ;
        RECT  12.288 0 12.312 0.084 ;
    END
  END o[61]
  PIN o[62]
    DIRECTION OUTPUT ;
    USE SIGNAL ;
    PORT
      LAYER M5 ;
        RECT  12.384 0 12.408 0.084 ;
    END
  END o[62]
  PIN o[63]
    DIRECTION OUTPUT ;
    USE SIGNAL ;
    PORT
      LAYER M5 ;
        RECT  12.48 0 12.504 0.084 ;
    END
  END o[63]
  PIN o[64]
    DIRECTION OUTPUT ;
    USE SIGNAL ;
    PORT
      LAYER M5 ;
        RECT  12.576 0 12.6 0.084 ;
    END
  END o[64]
  PIN o[65]
    DIRECTION OUTPUT ;
    USE SIGNAL ;
    PORT
      LAYER M5 ;
        RECT  12.672 0 12.696 0.084 ;
    END
  END o[65]
  PIN o[6]
    DIRECTION OUTPUT ;
    USE SIGNAL ;
    PORT
      LAYER M5 ;
        RECT  7.008 0 7.032 0.084 ;
    END
  END o[6]
  PIN o[7]
    DIRECTION OUTPUT ;
    USE SIGNAL ;
    PORT
      LAYER M5 ;
        RECT  7.104 0 7.128 0.084 ;
    END
  END o[7]
  PIN o[8]
    DIRECTION OUTPUT ;
    USE SIGNAL ;
    PORT
      LAYER M5 ;
        RECT  7.2 0 7.224 0.084 ;
    END
  END o[8]
  PIN o[9]
    DIRECTION OUTPUT ;
    USE SIGNAL ;
    PORT
      LAYER M5 ;
        RECT  7.296 0 7.32 0.084 ;
    END
  END o[9]
  PIN rst_n[0]
    DIRECTION INPUT ;
    USE SIGNAL ;
    PORT
      LAYER M4 ;
        RECT  43.116 39.36 43.2 39.384 ;
    END
  END rst_n[0]
  PIN VDD
    DIRECTION INOUT ;
    USE POWER ;
    PORT
      LAYER M5 ;
        RECT  40.392 2.151 40.512 75.609 ;
        RECT  37.692 2.151 37.812 75.609 ;
        RECT  34.992 2.151 35.112 75.609 ;
        RECT  32.292 2.151 32.412 75.609 ;
        RECT  29.592 2.151 29.712 75.609 ;
        RECT  26.892 2.151 27.012 75.609 ;
        RECT  24.192 2.151 24.312 75.609 ;
        RECT  21.492 2.151 21.612 75.609 ;
        RECT  18.792 2.151 18.912 75.609 ;
        RECT  16.092 2.151 16.212 75.609 ;
        RECT  13.392 2.151 13.512 75.609 ;
        RECT  10.692 2.151 10.812 75.609 ;
        RECT  7.992 2.151 8.112 75.609 ;
        RECT  5.292 2.151 5.412 75.609 ;
        RECT  2.592 2.151 2.712 75.609 ;
    END
  END VDD
  PIN VSS
    DIRECTION INOUT ;
    USE GROUND ;
    PORT
      LAYER M5 ;
        RECT  40.2 2.137 40.32 75.623 ;
        RECT  37.5 2.137 37.62 75.623 ;
        RECT  34.8 2.137 34.92 75.623 ;
        RECT  32.1 2.137 32.22 75.623 ;
        RECT  29.4 2.137 29.52 75.623 ;
        RECT  26.7 2.137 26.82 75.623 ;
        RECT  24 2.137 24.12 75.623 ;
        RECT  21.3 2.137 21.42 75.623 ;
        RECT  18.6 2.137 18.72 75.623 ;
        RECT  15.9 2.137 16.02 75.623 ;
        RECT  13.2 2.137 13.32 75.623 ;
        RECT  10.5 2.137 10.62 75.623 ;
        RECT  7.8 2.137 7.92 75.623 ;
        RECT  5.1 2.137 5.22 75.623 ;
        RECT  2.4 2.137 2.52 75.623 ;
    END
  END VSS
  OBS
    LAYER RVTN ;
     RECT  2.16 2.16 41.04 2.295 ;
     RECT  2.16 2.565 41.04 2.835 ;
     RECT  2.16 3.105 41.04 3.375 ;
     RECT  2.16 3.645 41.04 3.915 ;
     RECT  2.16 4.185 41.04 4.455 ;
     RECT  2.16 4.725 41.04 4.995 ;
     RECT  2.16 5.265 41.04 5.535 ;
     RECT  2.16 5.805 41.04 6.075 ;
     RECT  2.16 6.345 41.04 6.615 ;
     RECT  2.16 6.885 41.04 7.155 ;
     RECT  2.16 7.425 41.04 7.695 ;
     RECT  2.16 7.965 41.04 8.235 ;
     RECT  2.16 8.505 41.04 8.775 ;
     RECT  2.16 9.045 41.04 9.315 ;
     RECT  2.16 9.585 41.04 9.855 ;
     RECT  2.16 10.125 41.04 10.395 ;
     RECT  2.16 10.665 41.04 10.935 ;
     RECT  2.16 11.205 41.04 11.475 ;
     RECT  2.16 11.745 41.04 12.015 ;
     RECT  2.16 12.285 41.04 12.555 ;
     RECT  2.16 12.825 41.04 13.095 ;
     RECT  2.16 13.365 41.04 13.635 ;
     RECT  2.16 13.905 41.04 14.175 ;
     RECT  2.16 14.445 41.04 14.715 ;
     RECT  2.16 14.985 41.04 15.255 ;
     RECT  2.16 15.525 41.04 15.795 ;
     RECT  2.16 16.065 41.04 16.335 ;
     RECT  2.16 16.605 41.04 16.875 ;
     RECT  2.16 17.145 41.04 17.415 ;
     RECT  2.16 17.685 41.04 17.955 ;
     RECT  2.16 18.225 41.04 18.495 ;
     RECT  2.16 18.765 41.04 19.035 ;
     RECT  2.16 19.305 41.04 19.575 ;
     RECT  2.16 19.845 41.04 20.115 ;
     RECT  2.16 20.385 41.04 20.655 ;
     RECT  2.16 20.925 41.04 21.195 ;
     RECT  2.16 21.465 41.04 21.735 ;
     RECT  2.16 22.005 41.04 22.275 ;
     RECT  2.16 22.545 41.04 22.815 ;
     RECT  2.16 23.085 41.04 23.355 ;
     RECT  2.16 23.625 41.04 23.895 ;
     RECT  2.16 24.165 41.04 24.435 ;
     RECT  2.16 24.705 41.04 24.975 ;
     RECT  2.16 25.245 41.04 25.515 ;
     RECT  2.16 25.785 41.04 26.055 ;
     RECT  2.16 26.325 41.04 26.595 ;
     RECT  2.16 26.865 41.04 27.135 ;
     RECT  2.16 27.405 41.04 27.675 ;
     RECT  2.16 27.945 41.04 28.215 ;
     RECT  2.16 28.485 41.04 28.755 ;
     RECT  2.16 29.025 41.04 29.295 ;
     RECT  2.16 29.565 41.04 29.835 ;
     RECT  2.16 30.105 41.04 30.375 ;
     RECT  2.16 30.645 41.04 30.915 ;
     RECT  2.16 31.185 41.04 31.455 ;
     RECT  2.16 31.725 41.04 31.995 ;
     RECT  2.16 32.265 41.04 32.535 ;
     RECT  2.16 32.805 41.04 33.075 ;
     RECT  2.16 33.345 41.04 33.615 ;
     RECT  2.16 33.885 41.04 34.155 ;
     RECT  2.16 34.425 41.04 34.695 ;
     RECT  2.16 34.965 41.04 35.235 ;
     RECT  2.16 35.505 41.04 35.775 ;
     RECT  2.16 36.045 41.04 36.315 ;
     RECT  2.16 36.585 41.04 36.855 ;
     RECT  2.16 37.125 41.04 37.395 ;
     RECT  2.16 37.665 41.04 37.935 ;
     RECT  2.16 38.205 41.04 38.475 ;
     RECT  2.16 38.745 41.04 39.015 ;
     RECT  2.16 39.285 41.04 39.555 ;
     RECT  2.16 39.825 41.04 40.095 ;
     RECT  2.16 40.365 41.04 40.635 ;
     RECT  2.16 40.905 41.04 41.175 ;
     RECT  2.16 41.445 41.04 41.715 ;
     RECT  2.16 41.985 41.04 42.255 ;
     RECT  2.16 42.525 41.04 42.795 ;
     RECT  2.16 43.065 41.04 43.335 ;
     RECT  2.16 43.605 41.04 43.875 ;
     RECT  2.16 44.145 41.04 44.415 ;
     RECT  2.16 44.685 41.04 44.955 ;
     RECT  2.16 45.225 41.04 45.495 ;
     RECT  2.16 45.765 41.04 46.035 ;
     RECT  2.16 46.305 41.04 46.575 ;
     RECT  2.16 46.845 41.04 47.115 ;
     RECT  2.16 47.385 41.04 47.655 ;
     RECT  2.16 47.925 41.04 48.195 ;
     RECT  2.16 48.465 41.04 48.735 ;
     RECT  2.16 49.005 41.04 49.275 ;
     RECT  2.16 49.545 41.04 49.815 ;
     RECT  2.16 50.085 41.04 50.355 ;
     RECT  2.16 50.625 41.04 50.895 ;
     RECT  2.16 51.165 41.04 51.435 ;
     RECT  2.16 51.705 41.04 51.975 ;
     RECT  2.16 52.245 41.04 52.515 ;
     RECT  2.16 52.785 41.04 53.055 ;
     RECT  2.16 53.325 41.04 53.595 ;
     RECT  2.16 53.865 41.04 54.135 ;
     RECT  2.16 54.405 41.04 54.675 ;
     RECT  2.16 54.945 41.04 55.215 ;
     RECT  2.16 55.485 41.04 55.755 ;
     RECT  2.16 56.025 41.04 56.295 ;
     RECT  2.16 56.565 41.04 56.835 ;
     RECT  2.16 57.105 41.04 57.375 ;
     RECT  2.16 57.645 41.04 57.915 ;
     RECT  2.16 58.185 41.04 58.455 ;
     RECT  2.16 58.725 41.04 58.995 ;
     RECT  2.16 59.265 41.04 59.535 ;
     RECT  2.16 59.805 41.04 60.075 ;
     RECT  2.16 60.345 41.04 60.615 ;
     RECT  2.16 60.885 41.04 61.155 ;
     RECT  2.16 61.425 41.04 61.695 ;
     RECT  2.16 61.965 41.04 62.235 ;
     RECT  2.16 62.505 41.04 62.775 ;
     RECT  2.16 63.045 41.04 63.315 ;
     RECT  2.16 63.585 41.04 63.855 ;
     RECT  2.16 64.125 41.04 64.395 ;
     RECT  2.16 64.665 41.04 64.935 ;
     RECT  2.16 65.205 41.04 65.475 ;
     RECT  2.16 65.745 41.04 66.015 ;
     RECT  2.16 66.285 41.04 66.555 ;
     RECT  2.16 66.825 41.04 67.095 ;
     RECT  2.16 67.365 41.04 67.635 ;
     RECT  2.16 67.905 41.04 68.175 ;
     RECT  2.16 68.445 41.04 68.715 ;
     RECT  2.16 68.985 41.04 69.255 ;
     RECT  2.16 69.525 41.04 69.795 ;
     RECT  2.16 70.065 41.04 70.335 ;
     RECT  2.16 70.605 41.04 70.875 ;
     RECT  2.16 71.145 41.04 71.415 ;
     RECT  2.16 71.685 41.04 71.955 ;
     RECT  2.16 72.225 41.04 72.495 ;
     RECT  2.16 72.765 41.04 73.035 ;
     RECT  2.16 73.305 41.04 73.575 ;
     RECT  2.16 73.845 41.04 74.115 ;
     RECT  2.16 74.385 41.04 74.655 ;
     RECT  2.16 74.925 41.04 75.195 ;
     RECT  2.16 75.465 41.04 75.6 ;
    LAYER RVTP ;
     RECT  2.16 2.295 41.04 2.565 ;
     RECT  2.16 2.835 41.04 3.105 ;
     RECT  2.16 3.375 41.04 3.645 ;
     RECT  2.16 3.915 41.04 4.185 ;
     RECT  2.16 4.455 41.04 4.725 ;
     RECT  2.16 4.995 41.04 5.265 ;
     RECT  2.16 5.535 41.04 5.805 ;
     RECT  2.16 6.075 41.04 6.345 ;
     RECT  2.16 6.615 41.04 6.885 ;
     RECT  2.16 7.155 41.04 7.425 ;
     RECT  2.16 7.695 41.04 7.965 ;
     RECT  2.16 8.235 41.04 8.505 ;
     RECT  2.16 8.775 41.04 9.045 ;
     RECT  2.16 9.315 41.04 9.585 ;
     RECT  2.16 9.855 41.04 10.125 ;
     RECT  2.16 10.395 41.04 10.665 ;
     RECT  2.16 10.935 41.04 11.205 ;
     RECT  2.16 11.475 41.04 11.745 ;
     RECT  2.16 12.015 41.04 12.285 ;
     RECT  2.16 12.555 41.04 12.825 ;
     RECT  2.16 13.095 41.04 13.365 ;
     RECT  2.16 13.635 41.04 13.905 ;
     RECT  2.16 14.175 41.04 14.445 ;
     RECT  2.16 14.715 41.04 14.985 ;
     RECT  2.16 15.255 41.04 15.525 ;
     RECT  2.16 15.795 41.04 16.065 ;
     RECT  2.16 16.335 41.04 16.605 ;
     RECT  2.16 16.875 41.04 17.145 ;
     RECT  2.16 17.415 41.04 17.685 ;
     RECT  2.16 17.955 41.04 18.225 ;
     RECT  2.16 18.495 41.04 18.765 ;
     RECT  2.16 19.035 41.04 19.305 ;
     RECT  2.16 19.575 41.04 19.845 ;
     RECT  2.16 20.115 41.04 20.385 ;
     RECT  2.16 20.655 41.04 20.925 ;
     RECT  2.16 21.195 41.04 21.465 ;
     RECT  2.16 21.735 41.04 22.005 ;
     RECT  2.16 22.275 41.04 22.545 ;
     RECT  2.16 22.815 41.04 23.085 ;
     RECT  2.16 23.355 41.04 23.625 ;
     RECT  2.16 23.895 41.04 24.165 ;
     RECT  2.16 24.435 41.04 24.705 ;
     RECT  2.16 24.975 41.04 25.245 ;
     RECT  2.16 25.515 41.04 25.785 ;
     RECT  2.16 26.055 41.04 26.325 ;
     RECT  2.16 26.595 41.04 26.865 ;
     RECT  2.16 27.135 41.04 27.405 ;
     RECT  2.16 27.675 41.04 27.945 ;
     RECT  2.16 28.215 41.04 28.485 ;
     RECT  2.16 28.755 41.04 29.025 ;
     RECT  2.16 29.295 41.04 29.565 ;
     RECT  2.16 29.835 41.04 30.105 ;
     RECT  2.16 30.375 41.04 30.645 ;
     RECT  2.16 30.915 41.04 31.185 ;
     RECT  2.16 31.455 41.04 31.725 ;
     RECT  2.16 31.995 41.04 32.265 ;
     RECT  2.16 32.535 41.04 32.805 ;
     RECT  2.16 33.075 41.04 33.345 ;
     RECT  2.16 33.615 41.04 33.885 ;
     RECT  2.16 34.155 41.04 34.425 ;
     RECT  2.16 34.695 41.04 34.965 ;
     RECT  2.16 35.235 41.04 35.505 ;
     RECT  2.16 35.775 41.04 36.045 ;
     RECT  2.16 36.315 41.04 36.585 ;
     RECT  2.16 36.855 41.04 37.125 ;
     RECT  2.16 37.395 41.04 37.665 ;
     RECT  2.16 37.935 41.04 38.205 ;
     RECT  2.16 38.475 41.04 38.745 ;
     RECT  2.16 39.015 41.04 39.285 ;
     RECT  2.16 39.555 41.04 39.825 ;
     RECT  2.16 40.095 41.04 40.365 ;
     RECT  2.16 40.635 41.04 40.905 ;
     RECT  2.16 41.175 41.04 41.445 ;
     RECT  2.16 41.715 41.04 41.985 ;
     RECT  2.16 42.255 41.04 42.525 ;
     RECT  2.16 42.795 41.04 43.065 ;
     RECT  2.16 43.335 41.04 43.605 ;
     RECT  2.16 43.875 41.04 44.145 ;
     RECT  2.16 44.415 41.04 44.685 ;
     RECT  2.16 44.955 41.04 45.225 ;
     RECT  2.16 45.495 41.04 45.765 ;
     RECT  2.16 46.035 41.04 46.305 ;
     RECT  2.16 46.575 41.04 46.845 ;
     RECT  2.16 47.115 41.04 47.385 ;
     RECT  2.16 47.655 41.04 47.925 ;
     RECT  2.16 48.195 41.04 48.465 ;
     RECT  2.16 48.735 41.04 49.005 ;
     RECT  2.16 49.275 41.04 49.545 ;
     RECT  2.16 49.815 41.04 50.085 ;
     RECT  2.16 50.355 41.04 50.625 ;
     RECT  2.16 50.895 41.04 51.165 ;
     RECT  2.16 51.435 41.04 51.705 ;
     RECT  2.16 51.975 41.04 52.245 ;
     RECT  2.16 52.515 41.04 52.785 ;
     RECT  2.16 53.055 41.04 53.325 ;
     RECT  2.16 53.595 41.04 53.865 ;
     RECT  2.16 54.135 41.04 54.405 ;
     RECT  2.16 54.675 41.04 54.945 ;
     RECT  2.16 55.215 41.04 55.485 ;
     RECT  2.16 55.755 41.04 56.025 ;
     RECT  2.16 56.295 41.04 56.565 ;
     RECT  2.16 56.835 41.04 57.105 ;
     RECT  2.16 57.375 41.04 57.645 ;
     RECT  2.16 57.915 41.04 58.185 ;
     RECT  2.16 58.455 41.04 58.725 ;
     RECT  2.16 58.995 41.04 59.265 ;
     RECT  2.16 59.535 41.04 59.805 ;
     RECT  2.16 60.075 41.04 60.345 ;
     RECT  2.16 60.615 41.04 60.885 ;
     RECT  2.16 61.155 41.04 61.425 ;
     RECT  2.16 61.695 41.04 61.965 ;
     RECT  2.16 62.235 41.04 62.505 ;
     RECT  2.16 62.775 41.04 63.045 ;
     RECT  2.16 63.315 41.04 63.585 ;
     RECT  2.16 63.855 41.04 64.125 ;
     RECT  2.16 64.395 41.04 64.665 ;
     RECT  2.16 64.935 41.04 65.205 ;
     RECT  2.16 65.475 41.04 65.745 ;
     RECT  2.16 66.015 41.04 66.285 ;
     RECT  2.16 66.555 41.04 66.825 ;
     RECT  2.16 67.095 41.04 67.365 ;
     RECT  2.16 67.635 41.04 67.905 ;
     RECT  2.16 68.175 41.04 68.445 ;
     RECT  2.16 68.715 41.04 68.985 ;
     RECT  2.16 69.255 41.04 69.525 ;
     RECT  2.16 69.795 41.04 70.065 ;
     RECT  2.16 70.335 41.04 70.605 ;
     RECT  2.16 70.875 41.04 71.145 ;
     RECT  2.16 71.415 41.04 71.685 ;
     RECT  2.16 71.955 41.04 72.225 ;
     RECT  2.16 72.495 41.04 72.765 ;
     RECT  2.16 73.035 41.04 73.305 ;
     RECT  2.16 73.575 41.04 73.845 ;
     RECT  2.16 74.115 41.04 74.385 ;
     RECT  2.16 74.655 41.04 74.925 ;
     RECT  2.16 75.195 41.04 75.465 ;
    LAYER M1 ;
     RECT  2.16 2.151 41.04 75.609 ;
    LAYER M2 ;
     RECT  2.16 2.151 9.823 75.609 ;
     RECT  9.823 2.106 10.499 75.609 ;
     RECT  10.499 2.151 12.199 75.609 ;
     RECT  12.199 2.106 12.731 75.609 ;
     RECT  12.731 2.151 41.04 75.609 ;
     RECT  41.04 60.39 41.567 60.606 ;
     RECT  41.04 62.514 41.567 64.116 ;
     RECT  41.04 5.31 41.603 5.796 ;
     RECT  41.04 6.66 41.603 6.84 ;
     RECT  41.04 7.74 41.603 8.496 ;
     RECT  41.04 10.17 41.603 15.318 ;
     RECT  41.04 16.11 41.603 18.486 ;
     RECT  41.04 19.548 41.603 34.956 ;
     RECT  41.04 41.418 41.603 42.516 ;
     RECT  41.04 43.308 41.603 52.506 ;
     RECT  41.04 53.568 41.603 53.586 ;
     RECT  41.04 54.378 41.603 55.746 ;
     RECT  41.04 56.88 41.603 58.716 ;
     RECT  41.04 59.58 41.603 59.598 ;
     RECT  41.567 60.39 41.603 60.408 ;
     RECT  41.04 61.47 41.603 61.758 ;
     RECT  41.567 62.55 41.603 64.116 ;
     RECT  41.04 65.25 41.603 68.274 ;
     RECT  41.04 69.498 41.603 69.516 ;
     RECT  41.04 71.388 41.603 74.376 ;
     RECT  41.603 10.44 41.639 10.458 ;
     RECT  41.603 43.308 41.639 47.178 ;
     RECT  41.04 4.23 41.855 4.248 ;
     RECT  41.603 16.38 41.855 16.398 ;
     RECT  41.603 17.46 41.855 18.486 ;
     RECT  41.603 20.16 41.855 21.798 ;
     RECT  41.603 26.91 41.855 28.476 ;
     RECT  41.603 32.31 41.855 33.948 ;
     RECT  41.603 41.418 41.855 42.048 ;
     RECT  41.639 43.308 41.855 46.836 ;
     RECT  41.603 52.02 41.855 52.506 ;
     RECT  41.603 56.88 41.855 56.898 ;
     RECT  41.603 65.25 41.855 65.268 ;
     RECT  41.603 71.73 41.855 71.748 ;
     RECT  41.603 25.02 41.927 25.506 ;
     RECT  41.603 29.61 41.927 30.096 ;
     RECT  41.855 32.31 41.927 33.336 ;
     RECT  41.603 68.256 41.927 68.274 ;
     RECT  41.603 8.478 42.179 8.496 ;
     RECT  41.603 11.718 42.179 11.736 ;
     RECT  41.603 12.528 42.179 14.706 ;
     RECT  41.855 17.928 42.179 18.486 ;
     RECT  41.603 22.788 42.179 23.886 ;
     RECT  41.927 25.488 42.179 25.506 ;
     RECT  41.855 27.342 42.179 28.476 ;
     RECT  41.927 30.078 42.179 30.096 ;
     RECT  41.927 32.814 42.179 33.336 ;
     RECT  41.603 34.938 42.179 34.956 ;
     RECT  41.04 35.748 42.179 36.036 ;
     RECT  41.04 36.828 42.179 36.846 ;
     RECT  41.855 41.418 42.179 41.436 ;
     RECT  41.855 43.308 42.179 44.136 ;
     RECT  41.855 45.198 42.179 45.216 ;
     RECT  41.855 46.278 42.179 46.836 ;
     RECT  41.603 50.058 42.179 50.418 ;
     RECT  41.855 52.488 42.179 52.506 ;
     RECT  41.603 54.378 42.179 54.666 ;
     RECT  41.603 66.258 42.179 66.276 ;
     RECT  41.603 73.818 42.179 73.836 ;
     RECT  42.179 32.814 42.215 32.832 ;
     RECT  41.603 61.74 42.215 61.758 ;
     RECT  42.179 46.278 43.043 46.296 ;
     RECT  42.179 12.528 43.115 12.546 ;
     RECT  41.855 20.628 43.115 21.186 ;
     RECT  41.603 58.698 43.115 58.716 ;
    LAYER M3 ;
     RECT  6.372 0.091 8.226 0.139 ;
     RECT  9.396 0.091 9.414 0.139 ;
     RECT  11.16 0.091 11.178 0.139 ;
     RECT  6.372 0.139 8.55 1.099 ;
     RECT  9.396 0.139 9.666 1.723 ;
     RECT  11.16 0.139 11.682 1.723 ;
     RECT  12.528 0.091 12.546 1.723 ;
     RECT  6.372 1.099 8.658 1.771 ;
     RECT  9.396 1.723 12.546 1.771 ;
     RECT  6.372 1.771 12.546 2.101 ;
     RECT  6.372 2.101 12.726 2.143 ;
     RECT  13.824 0.139 13.842 2.143 ;
     RECT  21.636 1.723 21.654 2.143 ;
     RECT  6.372 2.143 13.842 2.191 ;
     RECT  21.315 2.143 21.654 2.191 ;
     RECT  6.192 2.191 13.842 2.263 ;
     RECT  5.115 2.143 5.205 2.335 ;
     RECT  6.192 2.263 14.022 2.335 ;
     RECT  5.115 2.335 14.022 2.371 ;
     RECT  18.615 2.143 18.705 2.371 ;
     RECT  21.315 2.191 21.726 2.371 ;
     RECT  24.015 2.143 24.105 2.371 ;
     RECT  2.415 2.143 2.505 2.413 ;
     RECT  15.915 2.143 16.005 2.413 ;
     RECT  18.252 2.371 18.705 2.413 ;
     RECT  23.904 2.371 24.105 2.413 ;
     RECT  26.715 2.143 26.805 2.413 ;
     RECT  29.415 2.143 29.505 2.413 ;
     RECT  32.115 2.143 32.205 2.413 ;
     RECT  34.815 2.143 34.905 2.413 ;
     RECT  37.515 2.143 37.605 2.413 ;
     RECT  40.215 2.143 40.305 2.413 ;
     RECT  16.992 2.371 17.01 2.497 ;
     RECT  18.252 2.413 18.897 2.497 ;
     RECT  23.904 2.413 24.297 2.497 ;
     RECT  32.115 2.413 32.397 2.497 ;
     RECT  23.904 2.497 24.57 2.533 ;
     RECT  32.115 2.497 32.49 2.533 ;
     RECT  5.115 2.371 14.094 2.569 ;
     RECT  15.915 2.413 16.197 2.569 ;
     RECT  16.992 2.497 18.897 2.569 ;
     RECT  23.904 2.533 24.714 2.569 ;
     RECT  5.115 2.569 14.238 2.641 ;
     RECT  15.156 2.371 15.174 2.641 ;
     RECT  15.915 2.569 18.897 2.641 ;
     RECT  21.315 2.371 22.23 2.641 ;
     RECT  23.724 2.569 24.714 2.641 ;
     RECT  31.5 2.533 32.526 2.641 ;
     RECT  33.48 2.371 33.498 2.641 ;
     RECT  26.715 2.413 26.997 2.731 ;
     RECT  31.5 2.641 33.498 2.803 ;
     RECT  21.315 2.641 22.842 2.827 ;
     RECT  23.724 2.641 25.038 2.827 ;
     RECT  26.028 2.731 26.997 2.839 ;
     RECT  34.815 2.413 35.097 2.839 ;
     RECT  21.315 2.827 25.038 2.875 ;
     RECT  26.028 2.839 27.054 2.875 ;
     RECT  28.152 2.767 28.17 2.875 ;
     RECT  31.32 2.803 33.498 2.875 ;
     RECT  34.815 2.839 35.37 2.875 ;
     RECT  21.315 2.875 27.054 2.911 ;
     RECT  28.152 2.875 28.386 2.911 ;
     RECT  34.668 2.875 35.37 2.911 ;
     RECT  21.315 2.911 28.386 3.001 ;
     RECT  29.415 2.413 29.697 3.001 ;
     RECT  30.852 2.875 33.498 3.001 ;
     RECT  34.308 2.911 35.946 3.001 ;
     RECT  30.852 3.001 35.946 3.037 ;
     RECT  21.315 3.001 29.697 3.065 ;
     RECT  5.115 2.641 18.897 3.073 ;
     RECT  21.315 3.065 27.522 3.073 ;
     RECT  30.6 3.037 35.946 3.109 ;
     RECT  20.772 3.073 27.522 3.145 ;
     RECT  28.26 3.065 29.697 3.181 ;
     RECT  30.6 3.109 36.342 3.181 ;
     RECT  5.115 3.073 19.422 3.259 ;
     RECT  20.592 3.145 27.522 3.259 ;
     RECT  28.26 3.181 36.738 3.379 ;
     RECT  37.515 2.413 37.797 3.379 ;
     RECT  40.215 2.413 40.497 3.595 ;
     RECT  28.26 3.379 37.797 3.613 ;
     RECT  40.215 3.595 41.022 3.641 ;
     RECT  28.26 3.613 38.502 3.685 ;
     RECT  28.26 3.685 38.538 3.721 ;
     RECT  40.215 3.641 40.497 3.721 ;
     RECT  5.115 3.259 27.522 3.811 ;
     RECT  28.26 3.721 38.682 3.811 ;
     RECT  5.115 3.811 38.682 3.955 ;
     RECT  5.115 3.955 38.862 3.991 ;
     RECT  39.924 3.721 40.497 3.991 ;
     RECT  41.832 4.123 41.85 4.253 ;
     RECT  5.115 3.991 40.497 4.415 ;
     RECT  6.372 4.415 40.497 4.451 ;
     RECT  6.372 4.451 38.538 4.559 ;
     RECT  39.528 4.451 40.497 4.651 ;
     RECT  5.115 4.415 5.454 4.721 ;
     RECT  39.528 4.651 41.022 4.793 ;
     RECT  6.372 4.559 21.906 5.305 ;
     RECT  22.644 4.559 38.538 5.341 ;
     RECT  6.3 5.305 21.906 5.467 ;
     RECT  22.644 5.341 38.79 5.467 ;
     RECT  6.3 5.467 38.79 5.611 ;
     RECT  39.528 4.793 40.497 5.611 ;
     RECT  6.228 5.611 40.497 5.845 ;
     RECT  5.115 4.721 5.397 5.971 ;
     RECT  6.192 5.845 40.497 5.971 ;
     RECT  5.115 5.971 40.497 6.859 ;
     RECT  5.076 6.859 40.497 7.115 ;
     RECT  5.076 7.115 38.826 7.501 ;
     RECT  4.86 7.501 38.826 7.933 ;
     RECT  39.564 7.115 40.497 7.933 ;
     RECT  41.58 5.179 41.598 7.961 ;
     RECT  42.156 8.347 42.174 8.501 ;
     RECT  4.86 7.933 40.497 8.875 ;
     RECT  4.86 8.875 41.022 9.041 ;
     RECT  4.86 9.041 40.59 9.653 ;
     RECT  41.58 9.931 41.598 10.193 ;
     RECT  41.616 10.435 41.634 10.493 ;
     RECT  41.58 10.987 41.598 11.201 ;
     RECT  42.156 11.515 42.174 11.741 ;
     RECT  4.86 9.653 40.497 12.083 ;
     RECT  28.656 12.083 40.497 12.091 ;
     RECT  41.58 12.043 41.598 12.281 ;
     RECT  4.86 12.083 27.882 12.389 ;
     RECT  4.86 12.389 27.702 12.479 ;
     RECT  43.092 12.523 43.11 12.605 ;
     RECT  28.656 12.091 40.626 12.631 ;
     RECT  28.656 12.631 40.914 12.749 ;
     RECT  6.408 12.479 27.702 13.531 ;
     RECT  6.408 13.531 27.918 13.603 ;
     RECT  28.656 12.749 40.626 13.603 ;
     RECT  4.86 12.479 5.397 13.837 ;
     RECT  4.86 13.837 5.562 13.901 ;
     RECT  42.156 13.063 42.174 14.72 ;
     RECT  6.408 13.603 40.626 15.791 ;
     RECT  41.58 15.211 41.598 16.267 ;
     RECT  4.86 13.901 5.526 16.375 ;
     RECT  6.408 15.791 40.59 16.375 ;
     RECT  41.58 16.267 41.85 16.403 ;
     RECT  4.86 16.375 40.59 16.681 ;
     RECT  41.58 16.403 41.598 16.871 ;
     RECT  4.86 16.681 40.806 16.943 ;
     RECT  4.86 16.943 40.626 17.069 ;
     RECT  41.832 17.323 41.85 17.483 ;
     RECT  4.86 17.069 40.59 18.149 ;
     RECT  42.156 17.851 42.174 18.491 ;
     RECT  21.315 18.149 40.59 18.907 ;
     RECT  21.315 18.907 41.022 19.103 ;
     RECT  4.86 18.149 20.466 19.381 ;
     RECT  41.58 19.435 41.598 19.571 ;
     RECT  4.86 19.381 20.502 20.155 ;
     RECT  21.315 19.103 40.59 20.155 ;
     RECT  41.832 19.963 41.85 20.183 ;
     RECT  4.86 20.155 40.59 21.001 ;
     RECT  43.092 20.491 43.11 21.191 ;
     RECT  4.86 21.001 40.626 21.541 ;
     RECT  4.86 21.541 40.734 21.659 ;
     RECT  4.86 21.659 40.626 21.695 ;
     RECT  41.832 21.547 41.85 21.803 ;
     RECT  41.58 22.072 41.598 22.109 ;
     RECT  4.86 21.695 40.554 22.469 ;
     RECT  42.156 22.603 42.174 23.891 ;
     RECT  41.58 24.187 41.598 24.431 ;
     RECT  4.86 22.469 40.497 24.781 ;
     RECT  41.904 24.715 41.922 25.043 ;
     RECT  42.156 25.243 42.174 25.511 ;
     RECT  4.86 24.781 40.626 25.817 ;
     RECT  41.58 25.771 41.598 26.393 ;
     RECT  4.86 25.817 40.497 26.671 ;
     RECT  4.86 26.671 40.734 26.789 ;
     RECT  41.832 26.827 41.85 26.933 ;
     RECT  4.86 26.789 40.554 28.021 ;
     RECT  4.86 28.021 40.734 28.139 ;
     RECT  42.156 27.337 42.174 28.481 ;
     RECT  41.58 28.939 41.598 29.021 ;
     RECT  4.86 28.139 40.497 29.191 ;
     RECT  4.86 29.191 40.842 29.489 ;
     RECT  41.904 29.467 41.922 29.633 ;
     RECT  42.156 29.995 42.174 30.101 ;
     RECT  4.86 29.489 28.566 30.379 ;
     RECT  29.34 29.489 40.554 30.379 ;
     RECT  4.86 30.379 40.554 30.451 ;
     RECT  4.86 30.451 40.734 30.677 ;
     RECT  4.86 30.677 40.626 31.379 ;
     RECT  41.58 30.523 41.598 31.793 ;
     RECT  41.904 32.107 41.922 32.333 ;
     RECT  4.86 31.379 40.497 32.341 ;
     RECT  4.86 32.341 40.842 32.459 ;
     RECT  4.86 32.459 40.554 32.801 ;
     RECT  42.192 32.635 42.21 32.837 ;
     RECT  42.156 33.163 42.174 33.341 ;
     RECT  4.86 32.801 40.497 33.583 ;
     RECT  41.832 33.691 41.85 33.953 ;
     RECT  4.86 33.583 40.554 33.961 ;
     RECT  41.58 34.219 41.598 34.259 ;
     RECT  4.86 33.961 40.734 35.041 ;
     RECT  4.86 35.041 40.914 35.501 ;
     RECT  42.156 34.747 42.174 36.851 ;
     RECT  4.86 35.501 40.626 37.057 ;
     RECT  4.86 37.057 40.77 38.101 ;
     RECT  4.86 38.101 40.842 38.515 ;
     RECT  43.092 38.347 43.11 38.765 ;
     RECT  4.86 38.515 40.914 39.091 ;
     RECT  4.32 39.091 40.914 39.341 ;
     RECT  4.716 39.341 40.914 39.587 ;
     RECT  4.716 39.587 40.842 39.749 ;
     RECT  4.86 39.749 40.842 40.061 ;
     RECT  4.86 40.061 30.366 40.555 ;
     RECT  31.248 40.061 40.842 40.559 ;
     RECT  31.248 40.559 40.698 40.595 ;
     RECT  4.14 40.555 30.366 41.251 ;
     RECT  31.248 40.595 40.554 41.251 ;
     RECT  4.14 41.251 40.554 41.369 ;
     RECT  42.156 41.371 42.174 41.441 ;
     RECT  41.832 41.899 41.85 42.053 ;
     RECT  4.32 41.369 40.554 42.151 ;
     RECT  41.58 42.427 41.598 42.521 ;
     RECT  4.32 42.151 40.59 42.749 ;
     RECT  4.68 42.749 40.59 42.961 ;
     RECT  4.68 42.961 40.914 43.259 ;
     RECT  3.924 43.645 3.942 43.681 ;
     RECT  4.68 43.259 40.77 43.681 ;
     RECT  3.924 43.681 40.77 43.799 ;
     RECT  42.156 42.955 42.174 44.141 ;
     RECT  3.924 43.799 40.662 44.375 ;
     RECT  41.832 44.539 41.85 44.753 ;
     RECT  4.032 44.375 40.662 45.031 ;
     RECT  4.032 45.031 40.914 45.149 ;
     RECT  42.156 45.067 42.174 45.221 ;
     RECT  4.032 45.149 40.734 45.242 ;
     RECT  3.6 45.242 40.734 45.689 ;
     RECT  41.832 45.595 41.85 45.833 ;
     RECT  43.02 46.123 43.038 46.301 ;
     RECT  3.6 45.689 3.618 46.471 ;
     RECT  4.608 45.689 40.734 46.471 ;
     RECT  3.6 46.471 40.734 46.769 ;
     RECT  42.156 46.651 42.174 46.841 ;
     RECT  3.6 46.769 40.626 47.075 ;
     RECT  41.616 47.155 41.634 47.213 ;
     RECT  3.996 47.075 40.626 47.357 ;
     RECT  3.996 47.357 40.497 47.579 ;
     RECT  4.536 47.579 40.497 48.361 ;
     RECT  4.536 48.361 40.59 48.413 ;
     RECT  4.536 48.413 40.554 48.433 ;
     RECT  4.464 48.433 40.554 48.509 ;
     RECT  4.464 48.509 17.154 48.739 ;
     RECT  4.32 48.739 17.154 49.081 ;
     RECT  4.14 49.081 17.154 49.315 ;
     RECT  17.928 48.509 40.554 49.315 ;
     RECT  4.14 49.315 40.59 49.517 ;
     RECT  4.14 49.517 18.99 49.531 ;
     RECT  41.58 47.695 41.598 49.541 ;
     RECT  3.852 49.531 18.99 49.577 ;
     RECT  19.872 49.517 40.59 49.739 ;
     RECT  4.32 49.577 18.99 49.949 ;
     RECT  17.28 49.949 18.99 50.009 ;
     RECT  19.872 49.739 40.497 50.359 ;
     RECT  4.32 49.949 16.47 50.389 ;
     RECT  42.156 49.819 42.174 50.423 ;
     RECT  3.816 50.389 16.47 50.429 ;
     RECT  17.316 50.009 18.99 50.431 ;
     RECT  19.836 50.359 40.497 50.431 ;
     RECT  3.96 50.429 16.47 50.549 ;
     RECT  3.996 50.549 16.47 50.971 ;
     RECT  17.316 50.431 40.497 50.971 ;
     RECT  3.996 50.971 40.497 51.005 ;
     RECT  4.14 51.005 40.497 51.089 ;
     RECT  41.58 50.863 41.598 51.503 ;
     RECT  41.832 51.931 41.85 52.043 ;
     RECT  4.32 51.089 40.497 52.285 ;
     RECT  3.816 52.285 40.497 52.349 ;
     RECT  42.156 52.459 42.174 52.511 ;
     RECT  4.14 52.349 40.497 52.987 ;
     RECT  4.14 52.987 41.022 53.024 ;
     RECT  4.14 53.024 40.497 53.179 ;
     RECT  3.78 53.179 40.497 53.249 ;
     RECT  4.14 53.249 40.497 53.555 ;
     RECT  41.58 53.515 41.598 53.591 ;
     RECT  4.608 53.555 40.497 53.869 ;
     RECT  42.156 54.043 42.174 54.671 ;
     RECT  4.608 53.869 40.554 54.955 ;
     RECT  4.536 54.955 40.554 55.021 ;
     RECT  3.924 55.021 40.554 55.147 ;
     RECT  3.564 55.147 40.554 55.175 ;
     RECT  41.58 55.099 41.598 55.751 ;
     RECT  2.415 2.413 2.697 55.831 ;
     RECT  3.564 55.175 3.726 55.831 ;
     RECT  2.415 55.831 3.726 55.985 ;
     RECT  3.708 55.985 3.726 56.065 ;
     RECT  4.464 55.175 40.554 56.065 ;
     RECT  3.708 56.065 40.554 56.155 ;
     RECT  3.708 56.155 41.022 56.363 ;
     RECT  3.708 56.363 40.554 56.525 ;
     RECT  3.708 56.525 3.726 56.597 ;
     RECT  41.832 56.683 41.85 56.903 ;
     RECT  4.572 56.525 40.554 57.415 ;
     RECT  4.032 57.415 40.554 57.485 ;
     RECT  4.572 57.485 40.554 57.569 ;
     RECT  4.572 57.569 40.497 57.725 ;
     RECT  4.608 57.725 40.497 58.459 ;
     RECT  41.58 57.211 41.598 58.523 ;
     RECT  4.212 58.459 40.497 58.531 ;
     RECT  4.068 58.531 40.554 58.801 ;
     RECT  43.092 58.693 43.11 58.829 ;
     RECT  4.032 58.801 40.554 59.035 ;
     RECT  3.6 59.035 40.554 59.189 ;
     RECT  3.6 59.189 40.497 59.297 ;
     RECT  3.924 59.297 40.497 59.729 ;
     RECT  39.708 59.729 40.497 59.837 ;
     RECT  41.58 59.323 41.598 60.379 ;
     RECT  3.924 59.729 38.97 60.539 ;
     RECT  41.544 60.379 41.598 60.611 ;
     RECT  4.356 60.539 38.97 60.691 ;
     RECT  39.78 59.837 40.497 60.691 ;
     RECT  41.58 60.611 41.598 61.435 ;
     RECT  41.58 61.435 42.21 61.763 ;
     RECT  4.356 60.691 40.497 62.045 ;
     RECT  4.824 62.045 40.497 62.159 ;
     RECT  4.86 62.159 40.497 62.231 ;
     RECT  5.115 62.231 40.497 62.465 ;
     RECT  41.58 61.763 41.598 62.491 ;
     RECT  41.544 62.491 41.598 62.537 ;
     RECT  5.115 62.465 39.15 63.391 ;
     RECT  39.888 62.465 40.497 63.391 ;
     RECT  5.115 63.391 40.497 63.509 ;
     RECT  9.504 63.509 40.497 63.517 ;
     RECT  9.504 63.517 40.554 63.545 ;
     RECT  9.504 63.545 39.15 63.617 ;
     RECT  9.504 63.617 38.79 63.689 ;
     RECT  5.115 63.509 8.73 63.779 ;
     RECT  9.504 63.689 38.322 63.779 ;
     RECT  9.576 63.779 38.322 64.049 ;
     RECT  41.58 62.537 41.598 64.121 ;
     RECT  9.576 64.049 38.214 64.319 ;
     RECT  5.115 63.779 8.658 64.355 ;
     RECT  39.924 63.545 40.554 64.363 ;
     RECT  25.02 64.319 38.214 64.637 ;
     RECT  9.576 64.319 24.297 64.705 ;
     RECT  39.312 64.363 40.554 64.859 ;
     RECT  9.144 64.705 24.297 65.003 ;
     RECT  9.144 65.003 22.842 65.129 ;
     RECT  25.128 64.637 38.214 65.237 ;
     RECT  5.115 64.355 8.406 65.245 ;
     RECT  9.144 65.129 20.394 65.245 ;
     RECT  39.312 64.859 40.497 65.245 ;
     RECT  41.832 65.131 41.85 65.273 ;
     RECT  25.128 65.237 37.797 65.309 ;
     RECT  23.58 65.003 24.297 65.371 ;
     RECT  21.24 65.129 22.05 65.435 ;
     RECT  38.52 65.245 40.497 65.669 ;
     RECT  38.52 65.669 39.438 65.705 ;
     RECT  22.788 65.129 22.842 65.813 ;
     RECT  41.58 65.659 41.598 65.813 ;
     RECT  23.58 65.371 24.858 66.091 ;
     RECT  25.596 65.309 37.797 66.091 ;
     RECT  42.156 66.187 42.174 66.281 ;
     RECT  23.58 66.091 37.797 66.361 ;
     RECT  23.328 66.361 38.142 66.487 ;
     RECT  38.916 65.705 39.438 66.487 ;
     RECT  5.115 65.245 20.394 66.515 ;
     RECT  9.108 66.515 20.394 66.523 ;
     RECT  21.315 65.435 22.05 66.523 ;
     RECT  9.108 66.523 22.05 66.701 ;
     RECT  23.328 66.487 39.438 66.749 ;
     RECT  9.252 66.701 22.05 67.127 ;
     RECT  5.115 66.515 8.097 67.387 ;
     RECT  5.076 67.387 8.097 67.405 ;
     RECT  37.515 66.749 39.438 67.441 ;
     RECT  40.215 65.669 40.497 67.441 ;
     RECT  23.328 66.749 36.27 67.531 ;
     RECT  9.252 67.127 19.746 67.559 ;
     RECT  20.7 67.127 22.05 67.603 ;
     RECT  22.86 67.531 36.27 67.603 ;
     RECT  20.7 67.603 36.27 67.711 ;
     RECT  20.7 67.711 36.486 67.801 ;
     RECT  37.515 67.441 40.497 67.801 ;
     RECT  5.076 67.405 8.334 67.837 ;
     RECT  9.252 67.559 19.71 67.901 ;
     RECT  41.58 66.715 41.598 67.973 ;
     RECT  5.076 67.837 8.406 68.071 ;
     RECT  9.252 67.901 19.026 68.071 ;
     RECT  20.7 67.801 40.497 68.243 ;
     RECT  20.88 68.243 40.497 68.251 ;
     RECT  41.904 68.251 41.922 68.333 ;
     RECT  20.88 68.251 40.662 68.369 ;
     RECT  5.076 68.071 19.026 68.549 ;
     RECT  5.076 68.549 18.99 68.639 ;
     RECT  25.092 68.369 40.662 68.639 ;
     RECT  18.18 68.639 18.99 68.675 ;
     RECT  18.252 68.675 18.99 68.711 ;
     RECT  20.88 68.369 24.354 68.711 ;
     RECT  25.128 68.639 40.662 68.711 ;
     RECT  25.452 68.711 40.662 68.827 ;
     RECT  5.076 68.639 17.442 68.909 ;
     RECT  18.615 68.711 18.99 68.909 ;
     RECT  5.076 68.909 17.154 68.945 ;
     RECT  20.88 68.711 24.297 68.945 ;
     RECT  25.452 68.827 41.022 68.981 ;
     RECT  5.076 68.945 16.506 69.251 ;
     RECT  14.832 69.251 16.506 69.323 ;
     RECT  5.076 69.251 14.058 69.449 ;
     RECT  41.58 69.355 41.598 69.521 ;
     RECT  12.456 69.449 14.022 69.557 ;
     RECT  5.076 69.449 11.574 69.565 ;
     RECT  14.832 69.323 16.362 69.629 ;
     RECT  5.04 69.565 11.574 69.719 ;
     RECT  21.315 68.945 24.297 69.719 ;
     RECT  23.508 69.719 24.297 69.727 ;
     RECT  5.04 69.719 10.797 69.755 ;
     RECT  13.215 69.557 14.022 69.755 ;
     RECT  15.12 69.629 16.362 69.755 ;
     RECT  23.508 69.727 24.678 69.755 ;
     RECT  12.456 69.557 12.474 69.827 ;
     RECT  23.904 69.755 24.678 69.835 ;
     RECT  25.452 68.981 40.497 69.835 ;
     RECT  23.904 69.835 40.497 69.869 ;
     RECT  24.015 69.869 40.497 69.883 ;
     RECT  20.412 69.421 20.43 69.989 ;
     RECT  5.04 69.755 8.91 70.025 ;
     RECT  15.12 69.755 16.326 70.025 ;
     RECT  24.015 69.883 41.022 70.061 ;
     RECT  21.315 69.719 22.734 70.097 ;
     RECT  24.015 70.061 39.438 70.529 ;
     RECT  9.648 69.755 10.797 70.537 ;
     RECT  15.12 70.025 15.138 70.565 ;
     RECT  9.648 70.537 10.818 70.601 ;
     RECT  38.736 70.529 39.438 70.637 ;
     RECT  15.876 70.025 16.326 70.645 ;
     RECT  10.515 70.601 10.818 70.673 ;
     RECT  40.215 70.061 41.022 70.673 ;
     RECT  15.876 70.645 16.974 70.681 ;
     RECT  14.472 70.771 14.994 70.829 ;
     RECT  15.876 70.681 17.19 70.829 ;
     RECT  5.04 70.025 8.838 70.835 ;
     RECT  21.315 70.097 22.05 70.843 ;
     RECT  24.015 70.529 37.797 70.891 ;
     RECT  5.115 70.835 8.838 70.943 ;
     RECT  13.215 69.755 13.497 70.951 ;
     RECT  16.956 70.829 17.19 70.951 ;
     RECT  15.876 70.829 16.197 70.979 ;
     RECT  16.956 70.951 17.262 71.069 ;
     RECT  20.88 70.843 22.05 71.069 ;
     RECT  14.832 70.829 14.994 71.105 ;
     RECT  18.615 68.909 18.897 71.113 ;
     RECT  17.244 71.069 17.262 71.141 ;
     RECT  13.215 70.951 13.734 71.213 ;
     RECT  20.952 71.069 22.05 71.213 ;
     RECT  23.472 70.891 37.797 71.213 ;
     RECT  9.54 71.149 9.558 71.249 ;
     RECT  13.215 71.213 13.662 71.249 ;
     RECT  5.115 70.943 8.226 71.339 ;
     RECT  14.832 71.105 14.922 71.339 ;
     RECT  18.615 71.113 19.242 71.339 ;
     RECT  23.472 71.213 24.354 71.347 ;
     RECT  38.916 70.637 39.438 71.371 ;
     RECT  25.128 71.213 37.797 71.383 ;
     RECT  6.984 71.339 8.097 71.411 ;
     RECT  14.904 71.339 14.922 71.411 ;
     RECT  21.315 71.213 22.05 71.455 ;
     RECT  41.58 70.939 41.598 71.467 ;
     RECT  21.315 71.455 22.41 71.491 ;
     RECT  23.148 71.347 24.354 71.491 ;
     RECT  21.315 71.491 24.354 71.501 ;
     RECT  5.115 71.339 6.138 71.609 ;
     RECT  7.128 71.411 8.097 71.609 ;
     RECT  18.615 71.339 19.098 71.609 ;
     RECT  25.128 71.383 37.854 71.609 ;
     RECT  22.896 71.501 24.354 71.645 ;
     RECT  22.896 71.645 24.297 71.681 ;
     RECT  38.844 71.371 39.438 71.725 ;
     RECT  40.215 70.673 40.497 71.725 ;
     RECT  6.12 71.609 6.138 71.753 ;
     RECT  41.58 71.467 41.85 71.753 ;
     RECT  23.4 71.681 24.297 71.789 ;
     RECT  25.128 71.609 37.797 71.879 ;
     RECT  38.844 71.725 40.497 71.879 ;
     RECT  25.2 71.879 37.797 71.915 ;
     RECT  40.176 71.879 40.497 71.951 ;
     RECT  25.2 71.915 33.426 72.059 ;
     RECT  38.844 71.879 39.294 72.121 ;
     RECT  25.488 72.059 33.426 72.257 ;
     RECT  25.488 72.257 33.174 72.419 ;
     RECT  34.2 71.915 37.797 72.761 ;
     RECT  34.2 72.761 35.946 72.841 ;
     RECT  36.72 72.761 37.797 72.841 ;
     RECT  38.736 72.121 39.294 72.841 ;
     RECT  40.215 71.951 40.497 72.841 ;
     RECT  25.704 72.419 33.174 72.959 ;
     RECT  36.72 72.841 40.497 73.103 ;
     RECT  34.056 72.841 35.946 73.139 ;
     RECT  25.74 72.959 33.174 73.229 ;
     RECT  41.58 71.753 41.598 73.301 ;
     RECT  25.74 73.229 32.397 73.499 ;
     RECT  34.164 73.139 35.946 73.507 ;
     RECT  36.72 73.103 39.294 73.507 ;
     RECT  33.156 73.229 33.174 73.535 ;
     RECT  25.812 73.499 31.338 73.769 ;
     RECT  34.164 73.507 39.294 73.805 ;
     RECT  42.156 73.579 42.174 73.841 ;
     RECT  38.808 73.805 39.294 73.921 ;
     RECT  40.215 73.103 40.497 73.921 ;
     RECT  25.812 73.769 31.086 73.949 ;
     RECT  34.164 73.805 37.998 73.949 ;
     RECT  34.164 73.949 36.486 74.039 ;
     RECT  37.515 73.949 37.998 74.075 ;
     RECT  36.468 74.039 36.486 74.111 ;
     RECT  38.808 73.921 40.497 74.111 ;
     RECT  26.172 73.949 31.086 74.183 ;
     RECT  39.348 74.111 40.497 74.309 ;
     RECT  34.164 74.039 35.226 74.345 ;
     RECT  39.888 74.309 40.497 74.381 ;
     RECT  41.58 74.107 41.598 74.381 ;
     RECT  21.315 71.501 22.05 74.579 ;
     RECT  26.172 74.183 31.05 74.579 ;
     RECT  34.815 74.345 35.226 74.579 ;
     RECT  34.815 74.579 35.118 74.615 ;
     RECT  26.172 74.579 30.906 74.651 ;
     RECT  26.172 74.651 30.762 74.687 ;
     RECT  21.315 74.579 21.69 74.849 ;
     RECT  26.172 74.687 30.654 74.849 ;
     RECT  28.98 74.849 30.654 74.957 ;
     RECT  26.172 74.849 28.098 74.971 ;
     RECT  28.98 74.957 30.474 74.993 ;
     RECT  26.136 74.971 28.098 75.005 ;
     RECT  26.136 75.005 27.63 75.119 ;
     RECT  28.98 74.993 29.697 75.155 ;
     RECT  26.715 75.119 27.414 75.227 ;
     RECT  29.196 75.155 29.697 75.227 ;
     RECT  2.415 55.985 2.697 75.347 ;
     RECT  5.115 71.609 5.397 75.347 ;
     RECT  7.815 71.609 8.097 75.347 ;
     RECT  10.515 70.673 10.797 75.347 ;
     RECT  13.215 71.249 13.497 75.347 ;
     RECT  15.915 70.979 16.197 75.347 ;
     RECT  18.615 71.609 18.897 75.347 ;
     RECT  21.315 74.849 21.597 75.347 ;
     RECT  24.015 71.789 24.297 75.347 ;
     RECT  26.715 75.227 26.997 75.347 ;
     RECT  29.415 75.227 29.697 75.347 ;
     RECT  32.115 73.499 32.397 75.347 ;
     RECT  34.815 74.615 35.097 75.347 ;
     RECT  37.515 74.075 37.797 75.347 ;
     RECT  40.215 74.381 40.497 75.347 ;
     RECT  2.415 75.347 2.505 75.617 ;
     RECT  5.115 75.347 5.205 75.617 ;
     RECT  7.815 75.347 7.905 75.617 ;
     RECT  10.515 75.347 10.605 75.617 ;
     RECT  13.215 75.347 13.305 75.617 ;
     RECT  15.915 75.347 16.005 75.617 ;
     RECT  18.615 75.347 18.705 75.617 ;
     RECT  21.315 75.347 21.474 75.617 ;
     RECT  24.015 75.347 24.105 75.617 ;
     RECT  26.715 75.347 26.805 75.617 ;
     RECT  29.415 75.347 29.505 75.617 ;
     RECT  32.115 75.347 32.205 75.617 ;
     RECT  34.815 75.347 34.905 75.617 ;
     RECT  37.515 75.347 37.605 75.617 ;
     RECT  40.215 75.347 40.305 75.617 ;
     RECT  21.456 75.617 21.474 75.821 ;
    LAYER M4 ;
     RECT  2.408 2.148 2.512 75.612 ;
     RECT  2.512 2.418 2.704 75.342 ;
     RECT  3.74 53.184 3.781 53.208 ;
     RECT  3.781 52.32 3.827 53.208 ;
     RECT  3.781 49.536 3.868 51 ;
     RECT  3.868 49.536 3.881 49.56 ;
     RECT  3.913 43.872 3.925 43.896 ;
     RECT  2.704 45.264 3.925 45.288 ;
     RECT  3.925 43.872 3.971 45.288 ;
     RECT  3.971 43.872 3.997 45 ;
     RECT  3.868 50.976 4.025 51 ;
     RECT  3.941 59.28 4.025 59.304 ;
     RECT  4.525 54.96 4.847 54.984 ;
     RECT  3.973 57.456 4.885 57.72 ;
     RECT  3.985 60.288 4.885 60.312 ;
     RECT  4.345 62.016 4.885 62.04 ;
     RECT  4.129 40.56 4.981 40.584 ;
     RECT  3.827 52.32 4.981 52.872 ;
     RECT  4.309 42.72 4.993 42.744 ;
     RECT  4.993 42.72 5.029 42.84 ;
     RECT  3.997 44.448 5.029 45 ;
     RECT  5.065 6.864 5.108 6.888 ;
     RECT  4.309 39.312 5.108 39.336 ;
     RECT  4.981 40.56 5.108 41.208 ;
     RECT  5.029 42.72 5.108 45 ;
     RECT  2.704 47.04 5.108 47.064 ;
     RECT  4.921 48.96 5.108 48.984 ;
     RECT  4.949 50.688 5.108 50.712 ;
     RECT  4.981 52.224 5.108 52.872 ;
     RECT  4.847 54.336 5.108 54.984 ;
     RECT  4.885 56.784 5.108 58.152 ;
     RECT  4.885 60.288 5.108 62.04 ;
     RECT  4.981 66.048 5.108 66.072 ;
     RECT  4.981 67.392 5.108 67.416 ;
     RECT  5.065 68.64 5.108 68.664 ;
     RECT  5.029 70.08 5.108 70.104 ;
     RECT  5.108 2.148 5.212 75.612 ;
     RECT  5.212 2.418 5.404 75.342 ;
     RECT  5.404 42.72 5.501 45.288 ;
     RECT  5.404 6.288 5.555 6.888 ;
     RECT  5.404 56.064 5.555 63.816 ;
     RECT  5.404 47.04 5.645 54.984 ;
     RECT  5.645 47.04 5.699 48.984 ;
     RECT  5.555 56.064 5.843 63.432 ;
     RECT  5.843 57.168 5.891 63.432 ;
     RECT  5.404 40.56 5.897 41.208 ;
     RECT  5.645 50.208 5.933 54.984 ;
     RECT  5.891 57.696 5.969 63.432 ;
     RECT  5.969 57.696 6.041 61.512 ;
     RECT  5.897 41.184 6.293 41.208 ;
     RECT  6.041 57.696 6.293 60.36 ;
     RECT  5.404 65.184 6.293 66.072 ;
     RECT  5.699 47.04 6.323 48.888 ;
     RECT  5.404 68.16 6.401 68.664 ;
     RECT  5.404 70.08 6.437 70.104 ;
     RECT  6.361 0.096 6.469 0.12 ;
     RECT  5.933 53.232 6.469 54.984 ;
     RECT  5.843 56.064 6.469 56.088 ;
     RECT  5.404 3.024 6.476 4.008 ;
     RECT  5.501 42.816 6.509 45.288 ;
     RECT  6.293 57.744 6.545 60.36 ;
     RECT  5.555 6.288 6.613 6.552 ;
     RECT  5.404 9.216 6.613 9.672 ;
     RECT  6.509 42.96 6.649 45.288 ;
     RECT  6.476 2.832 6.653 4.008 ;
     RECT  5.404 38.544 6.689 39.336 ;
     RECT  6.649 12.72 6.709 12.744 ;
     RECT  6.613 9.216 6.716 10.2 ;
     RECT  6.709 11.808 6.719 12.744 ;
     RECT  6.323 47.616 6.721 48.888 ;
     RECT  5.933 50.208 6.721 52.248 ;
     RECT  6.469 0.096 6.755 0.552 ;
     RECT  6.649 42.96 6.793 45.672 ;
     RECT  6.719 11.712 6.796 12.744 ;
     RECT  6.716 8.88 6.803 10.2 ;
     RECT  6.397 7.776 6.829 7.8 ;
     RECT  6.721 47.616 6.937 52.248 ;
     RECT  6.469 53.232 6.937 56.088 ;
     RECT  6.689 38.544 7.045 39.288 ;
     RECT  6.997 1.152 7.052 1.176 ;
     RECT  6.86 2.256 7.052 2.28 ;
     RECT  5.404 17.04 7.153 17.064 ;
     RECT  7.052 1.152 7.373 2.28 ;
     RECT  6.401 68.352 7.405 68.664 ;
     RECT  6.293 66.048 7.429 66.072 ;
     RECT  7.532 31.536 7.573 31.56 ;
     RECT  6.793 42.96 7.585 46.104 ;
     RECT  7.081 41.04 7.621 41.064 ;
     RECT  7.373 1.632 7.669 2.28 ;
     RECT  6.545 59.232 7.669 60.36 ;
     RECT  7.429 66.048 7.669 66.12 ;
     RECT  7.669 1.632 7.808 2.808 ;
     RECT  6.653 3.888 7.808 4.008 ;
     RECT  6.613 5.664 7.808 6.552 ;
     RECT  6.829 7.776 7.808 8.568 ;
     RECT  6.803 9.792 7.808 10.2 ;
     RECT  6.796 11.712 7.808 11.736 ;
     RECT  6.796 12.72 7.808 12.744 ;
     RECT  5.404 13.872 7.808 13.896 ;
     RECT  7.153 17.04 7.808 17.112 ;
     RECT  5.404 18.768 7.808 18.792 ;
     RECT  6.433 21.504 7.808 21.528 ;
     RECT  5.404 24.48 7.808 24.504 ;
     RECT  7.765 27.456 7.808 27.48 ;
     RECT  7.009 29.232 7.808 29.256 ;
     RECT  7.573 31.2 7.808 31.56 ;
     RECT  7.532 32.928 7.808 32.952 ;
     RECT  7.573 34.128 7.808 34.152 ;
     RECT  7.521 35.28 7.808 35.304 ;
     RECT  7.045 36.816 7.808 36.84 ;
     RECT  7.045 38.208 7.808 39.288 ;
     RECT  7.621 41.04 7.808 41.16 ;
     RECT  7.585 42.72 7.808 46.104 ;
     RECT  6.937 47.616 7.808 56.088 ;
     RECT  6.545 57.744 7.808 57.768 ;
     RECT  7.669 59.232 7.808 60.408 ;
     RECT  6.041 61.488 7.808 61.512 ;
     RECT  5.969 62.544 7.808 63.432 ;
     RECT  7.669 65.952 7.808 66.12 ;
     RECT  7.405 68.352 7.808 69.576 ;
     RECT  7.808 1.632 7.912 75.612 ;
     RECT  6.755 0.096 8.053 0.12 ;
     RECT  7.912 1.632 8.104 75.342 ;
     RECT  8.053 0.096 8.149 0.168 ;
     RECT  8.104 20.544 8.165 22.152 ;
     RECT  8.104 31.2 8.165 33.576 ;
     RECT  8.104 46.032 8.165 53.592 ;
     RECT  8.104 63.744 8.309 64.152 ;
     RECT  8.149 0.096 8.341 0.216 ;
     RECT  8.104 38.112 8.417 38.232 ;
     RECT  8.165 46.032 8.428 53.544 ;
     RECT  8.104 12.912 8.579 18.984 ;
     RECT  8.341 0.096 8.588 0.312 ;
     RECT  8.104 1.632 8.588 3.24 ;
     RECT  8.309 63.744 8.62 63.768 ;
     RECT  8.104 5.136 8.627 9.816 ;
     RECT  8.588 0.096 8.675 3.24 ;
     RECT  8.627 5.136 8.705 8.328 ;
     RECT  8.104 40.224 8.705 41.544 ;
     RECT  8.579 15.072 8.741 18.984 ;
     RECT  8.579 12.912 8.777 13.656 ;
     RECT  8.104 57.936 8.777 62.184 ;
     RECT  8.777 57.936 8.813 60.84 ;
     RECT  8.104 35.28 8.849 36.696 ;
     RECT  8.428 46.032 8.957 50.424 ;
     RECT  8.741 17.616 8.963 18.984 ;
     RECT  8.165 20.544 8.963 20.568 ;
     RECT  8.675 0.096 9.011 0.312 ;
     RECT  8.104 65.952 9.097 65.976 ;
     RECT  8.104 26.4 9.1 27.96 ;
     RECT  8.741 15.072 9.107 16.536 ;
     RECT  8.104 29.568 9.133 29.592 ;
     RECT  8.957 47.232 9.137 50.424 ;
     RECT  8.165 22.128 9.169 22.152 ;
     RECT  8.705 5.136 9.205 5.832 ;
     RECT  9.169 22.128 9.205 22.824 ;
     RECT  8.957 46.032 9.209 46.104 ;
     RECT  8.165 31.776 9.233 33.576 ;
     RECT  9.205 22.032 9.241 22.824 ;
     RECT  8.104 24.096 9.241 24.936 ;
     RECT  9.133 29.52 9.241 29.592 ;
     RECT  9.233 31.344 9.241 33.576 ;
     RECT  8.705 41.472 9.241 41.544 ;
     RECT  8.104 42.528 9.241 45 ;
     RECT  9.097 65.952 9.241 66.696 ;
     RECT  8.705 7.296 9.245 8.328 ;
     RECT  8.963 18.432 9.281 18.792 ;
     RECT  8.777 13.488 9.299 13.656 ;
     RECT  8.104 11.232 9.313 11.4 ;
     RECT  9.241 29.52 9.313 33.576 ;
     RECT  9.313 29.088 9.317 33.576 ;
     RECT  8.675 1.728 9.349 3.24 ;
     RECT  9.205 4.56 9.349 5.832 ;
     RECT  8.428 51.648 9.395 53.544 ;
     RECT  9.241 22.032 9.421 24.936 ;
     RECT  8.813 59.04 9.425 60.84 ;
     RECT  9.107 15.84 9.446 16.536 ;
     RECT  9.313 11.232 9.452 11.928 ;
     RECT  9.1 26.544 9.493 27.96 ;
     RECT  9.317 29.088 9.493 30.792 ;
     RECT  8.849 35.52 9.497 36.696 ;
     RECT  8.417 38.112 9.529 38.136 ;
     RECT  9.169 39.12 9.529 39.144 ;
     RECT  9.446 15.888 9.532 16.536 ;
     RECT  9.493 26.544 9.533 30.792 ;
     RECT  9.395 52.032 9.637 53.544 ;
     RECT  8.104 54.672 9.637 55.992 ;
     RECT  8.104 68.928 9.637 68.952 ;
     RECT  9.245 7.296 9.673 7.416 ;
     RECT  9.241 41.472 9.673 45 ;
     RECT  9.637 52.032 9.685 55.992 ;
     RECT  9.532 15.984 9.745 16.536 ;
     RECT  9.349 1.728 9.781 5.832 ;
     RECT  9.781 1.728 9.817 6.12 ;
     RECT  9.673 7.2 9.817 7.416 ;
     RECT  9.299 13.632 9.853 13.656 ;
     RECT  9.452 11.232 9.877 11.976 ;
     RECT  9.529 38.112 9.889 39.144 ;
     RECT  9.637 68.352 9.889 68.952 ;
     RECT  9.781 20.976 9.925 21 ;
     RECT  8.777 62.16 9.925 62.184 ;
     RECT  9.497 35.52 9.997 35.736 ;
     RECT  8.627 9.648 10.021 9.816 ;
     RECT  9.889 37.68 10.141 39.144 ;
     RECT  9.011 0.096 10.165 0.216 ;
     RECT  9.925 20.928 10.177 21 ;
     RECT  9.421 22.032 10.177 25.08 ;
     RECT  9.533 26.544 10.177 29.544 ;
     RECT  9.673 41.472 10.177 45.048 ;
     RECT  9.209 46.032 10.177 46.056 ;
     RECT  10.021 9.312 10.22 9.816 ;
     RECT  8.705 40.224 10.249 40.248 ;
     RECT  9.877 11.232 10.285 12.168 ;
     RECT  8.813 57.936 10.285 57.96 ;
     RECT  10.22 9.312 10.309 10.056 ;
     RECT  10.285 11.232 10.309 12.6 ;
     RECT  9.853 13.632 10.309 14.376 ;
     RECT  9.137 47.328 10.321 50.424 ;
     RECT  10.309 8.736 10.357 10.056 ;
     RECT  10.177 20.928 10.357 25.08 ;
     RECT  9.241 65.952 10.465 67.32 ;
     RECT  9.817 1.728 10.508 7.416 ;
     RECT  10.357 8.544 10.508 10.056 ;
     RECT  10.309 11.232 10.508 14.376 ;
     RECT  9.745 15.984 10.508 16.584 ;
     RECT  9.281 18.768 10.508 18.792 ;
     RECT  10.357 20.4 10.508 25.08 ;
     RECT  10.177 26.112 10.508 29.544 ;
     RECT  9.533 30.768 10.508 30.792 ;
     RECT  9.317 31.776 10.508 33.576 ;
     RECT  9.997 34.752 10.508 35.736 ;
     RECT  10.141 36.816 10.508 39.144 ;
     RECT  10.249 40.128 10.508 40.248 ;
     RECT  10.177 41.472 10.508 46.056 ;
     RECT  10.321 47.328 10.508 50.664 ;
     RECT  9.685 52.032 10.508 56.472 ;
     RECT  10.285 57.84 10.508 57.96 ;
     RECT  9.425 59.04 10.508 59.88 ;
     RECT  9.925 60.912 10.508 62.184 ;
     RECT  10.465 65.136 10.508 67.32 ;
     RECT  9.889 68.352 10.508 69.48 ;
     RECT  10.508 1.728 10.612 75.612 ;
     RECT  10.165 0.096 10.741 0.6 ;
     RECT  10.612 1.728 10.741 75.342 ;
     RECT  10.741 0.096 10.804 75.342 ;
     RECT  10.804 40.08 10.931 46.152 ;
     RECT  10.804 36.528 10.937 38.232 ;
     RECT  10.937 36.528 10.973 37.704 ;
     RECT  10.804 34.704 11.009 35.496 ;
     RECT  10.804 9.792 11.027 12.6 ;
     RECT  11.027 9.792 11.081 10.344 ;
     RECT  10.804 18.768 11.081 18.936 ;
     RECT  10.931 40.08 11.081 41.928 ;
     RECT  10.804 0.096 11.123 2.376 ;
     RECT  11.027 11.424 11.189 12.6 ;
     RECT  10.804 52.032 11.189 54.12 ;
     RECT  10.804 63.792 11.189 67.32 ;
     RECT  10.804 56.976 11.219 62.712 ;
     RECT  11.081 40.128 11.225 41.928 ;
     RECT  10.804 29.52 11.261 33.576 ;
     RECT  11.081 9.936 11.297 10.344 ;
     RECT  10.804 20.4 11.297 22.248 ;
     RECT  10.804 68.928 11.297 69.48 ;
     RECT  10.931 43.104 11.305 46.152 ;
     RECT  11.123 1.152 11.333 2.376 ;
     RECT  10.804 25.968 11.405 28.296 ;
     RECT  11.305 45.504 11.405 46.152 ;
     RECT  10.804 47.424 11.405 47.448 ;
     RECT  10.804 17.616 11.411 17.64 ;
     RECT  10.804 55.152 11.411 55.752 ;
     RECT  10.804 48.864 11.441 50.904 ;
     RECT  11.297 69.456 11.441 69.48 ;
     RECT  11.261 29.52 11.459 33.144 ;
     RECT  11.297 20.4 11.477 21.816 ;
     RECT  11.459 31.344 11.477 33.144 ;
     RECT  11.225 41.904 11.549 41.928 ;
     RECT  10.804 3.408 11.585 7.608 ;
     RECT  11.189 65.568 11.585 67.272 ;
     RECT  11.297 9.936 11.651 10.248 ;
     RECT  11.333 1.152 11.657 1.8 ;
     RECT  11.441 48.864 11.657 50.856 ;
     RECT  11.189 52.032 11.657 54.072 ;
     RECT  10.804 14.064 11.692 14.232 ;
     RECT  11.459 29.52 11.693 30.312 ;
     RECT  11.585 67.248 11.693 67.272 ;
     RECT  11.657 1.728 11.729 1.8 ;
     RECT  11.189 63.792 11.795 64.44 ;
     RECT  10.804 23.328 11.797 24.12 ;
     RECT  11.405 46.032 11.797 46.152 ;
     RECT  11.477 31.776 11.837 33.144 ;
     RECT  11.305 43.104 11.873 44.472 ;
     RECT  11.585 3.408 11.909 6.696 ;
     RECT  11.692 14.16 11.909 14.232 ;
     RECT  11.225 40.128 11.909 40.152 ;
     RECT  11.909 3.408 11.941 5.256 ;
     RECT  11.9 47.472 11.941 47.496 ;
     RECT  11.941 47.472 11.987 48.456 ;
     RECT  11.941 7.968 12.005 8.568 ;
     RECT  10.973 36.528 12.013 37.128 ;
     RECT  11.905 38.16 12.013 38.184 ;
     RECT  11.189 11.424 12.017 11.976 ;
     RECT  11.219 59.04 12.035 62.712 ;
     RECT  11.987 48.432 12.053 48.456 ;
     RECT  11.219 56.976 12.053 57 ;
     RECT  12.035 59.04 12.086 59.544 ;
     RECT  11.941 42.144 12.089 42.744 ;
     RECT  11.009 34.704 12.095 35.208 ;
     RECT  12.005 7.968 12.157 8.616 ;
     RECT  11.797 23.328 12.157 24.984 ;
     RECT  11.405 25.968 12.157 27.72 ;
     RECT  11.411 55.44 12.157 55.752 ;
     RECT  12.086 59.04 12.172 59.496 ;
     RECT  11.081 18.768 12.265 18.792 ;
     RECT  12.013 36.528 12.325 38.184 ;
     RECT  11.123 0.096 12.373 0.168 ;
     RECT  12.017 11.52 12.373 11.976 ;
     RECT  10.804 15.552 12.409 15.96 ;
     RECT  12.337 39.6 12.517 39.912 ;
     RECT  11.797 46.032 12.517 46.392 ;
     RECT  11.729 1.728 12.521 1.752 ;
     RECT  12.157 23.328 12.553 27.72 ;
     RECT  11.585 65.568 12.553 65.976 ;
     RECT  12.373 0.096 12.557 0.6 ;
     RECT  11.657 52.176 12.565 54.072 ;
     RECT  12.157 55.44 12.565 56.376 ;
     RECT  11.693 29.904 12.589 30.312 ;
     RECT  11.657 49.488 12.805 50.856 ;
     RECT  12.565 52.176 12.805 56.376 ;
     RECT  11.909 6.24 12.853 6.696 ;
     RECT  12.157 7.968 12.853 9.048 ;
     RECT  11.941 2.832 12.877 5.256 ;
     RECT  12.853 6.24 12.877 9.048 ;
     RECT  12.373 14.4 12.877 14.472 ;
     RECT  12.409 15.552 12.877 16.584 ;
     RECT  11.651 10.176 12.913 10.248 ;
     RECT  12.035 60.816 12.913 62.712 ;
     RECT  12.805 49.488 13.021 56.376 ;
     RECT  12.557 0.144 13.043 0.6 ;
     RECT  12.517 39.552 13.045 39.912 ;
     RECT  12.553 23.328 13.057 27.912 ;
     RECT  12.089 42.72 13.057 42.744 ;
     RECT  11.873 43.872 13.057 44.472 ;
     RECT  12.877 2.832 13.093 9.048 ;
     RECT  12.913 10.176 13.093 10.488 ;
     RECT  12.373 11.52 13.093 12.264 ;
     RECT  11.837 31.776 13.093 33.096 ;
     RECT  12.095 34.128 13.093 35.208 ;
     RECT  12.325 36.384 13.093 38.184 ;
     RECT  13.045 39.552 13.093 40.056 ;
     RECT  13.057 42.72 13.093 44.472 ;
     RECT  13.021 49.008 13.093 56.376 ;
     RECT  13.093 11.472 13.129 12.264 ;
     RECT  12.517 46.032 13.129 47.4 ;
     RECT  13.093 49.008 13.129 56.76 ;
     RECT  13.093 31.488 13.165 33.096 ;
     RECT  13.093 34.128 13.165 38.184 ;
     RECT  13.129 46.032 13.165 56.856 ;
     RECT  13.093 2.832 13.208 10.488 ;
     RECT  13.129 11.472 13.208 13.08 ;
     RECT  12.877 14.4 13.208 16.584 ;
     RECT  12.265 18.24 13.208 18.792 ;
     RECT  11.477 20.976 13.208 21.816 ;
     RECT  13.057 23.328 13.208 28.536 ;
     RECT  12.589 29.904 13.208 30.36 ;
     RECT  13.165 31.488 13.208 38.184 ;
     RECT  13.093 39.552 13.208 40.584 ;
     RECT  13.093 42.72 13.208 44.712 ;
     RECT  13.165 46.032 13.208 57.144 ;
     RECT  12.172 59.04 13.208 59.304 ;
     RECT  12.913 60.816 13.208 63.24 ;
     RECT  11.795 64.416 13.208 64.44 ;
     RECT  12.553 65.568 13.208 66.84 ;
     RECT  12.877 68.688 13.208 68.712 ;
     RECT  13.208 2.148 13.312 75.612 ;
     RECT  13.312 2.418 13.504 75.342 ;
     RECT  13.504 45.84 13.565 47.4 ;
     RECT  13.504 20.16 13.619 40.44 ;
     RECT  13.504 62.16 13.619 62.76 ;
     RECT  13.504 64.128 13.619 65.976 ;
     RECT  13.504 48.96 13.667 57.384 ;
     RECT  13.619 28.464 13.709 40.44 ;
     RECT  13.504 4.512 13.745 6.744 ;
     RECT  13.619 64.128 13.745 64.44 ;
     RECT  13.504 14.16 13.817 16.584 ;
     RECT  13.709 37.68 13.817 40.44 ;
     RECT  13.043 0.144 13.853 0.168 ;
     RECT  13.504 58.656 13.853 61.176 ;
     RECT  13.817 37.824 13.859 40.44 ;
     RECT  13.745 6 13.889 6.744 ;
     RECT  13.619 62.16 13.889 62.184 ;
     RECT  13.859 37.824 13.961 38.184 ;
     RECT  13.745 4.512 13.997 4.872 ;
     RECT  13.504 44.4 14.003 44.712 ;
     RECT  13.565 45.84 14.003 46.248 ;
     RECT  13.504 8.448 14.061 10.2 ;
     RECT  13.859 39.552 14.105 40.44 ;
     RECT  13.504 43.104 14.141 43.128 ;
     RECT  14.003 44.448 14.141 44.712 ;
     RECT  13.709 28.464 14.177 36.408 ;
     RECT  13.667 48.96 14.213 57.144 ;
     RECT  14.213 48.96 14.249 52.728 ;
     RECT  13.619 20.16 14.285 27.384 ;
     RECT  14.249 51.312 14.285 52.728 ;
     RECT  13.745 64.128 14.321 64.2 ;
     RECT  13.504 12.528 14.357 13.08 ;
     RECT  14.177 28.944 14.357 36.408 ;
     RECT  13.817 14.16 14.393 16.296 ;
     RECT  14.357 34.752 14.465 36.408 ;
     RECT  13.504 17.664 14.497 17.736 ;
     RECT  14.003 46.032 14.533 46.248 ;
     RECT  13.565 47.328 14.533 47.4 ;
     RECT  14.465 34.896 14.537 36.408 ;
     RECT  14.249 48.96 14.573 50.136 ;
     RECT  13.889 6.72 14.605 6.744 ;
     RECT  14.061 8.448 14.605 9.624 ;
     RECT  14.357 28.944 14.645 33.576 ;
     RECT  13.504 67.248 14.677 68.712 ;
     RECT  14.605 6.72 14.681 9.624 ;
     RECT  14.497 17.616 14.681 17.736 ;
     RECT  14.645 29.28 14.681 33.576 ;
     RECT  14.285 20.16 14.717 27.336 ;
     RECT  14.285 51.312 14.717 52.44 ;
     RECT  13.504 18.768 14.721 18.792 ;
     RECT  14.717 20.16 14.721 25.608 ;
     RECT  14.681 6.72 14.753 7.56 ;
     RECT  14.681 17.616 14.789 17.688 ;
     RECT  13.853 58.656 14.797 61.032 ;
     RECT  14.721 18.768 14.819 25.608 ;
     RECT  14.393 14.16 14.821 16.104 ;
     RECT  14.821 14.064 14.825 16.104 ;
     RECT  13.961 37.824 14.825 37.848 ;
     RECT  14.105 39.6 14.825 40.44 ;
     RECT  14.681 29.28 14.861 32.76 ;
     RECT  14.537 34.944 14.861 36.408 ;
     RECT  14.533 46.032 14.861 47.4 ;
     RECT  14.825 14.064 14.893 14.184 ;
     RECT  14.893 13.824 14.908 14.184 ;
     RECT  14.825 40.416 14.915 40.44 ;
     RECT  14.861 29.28 14.933 31.272 ;
     RECT  14.321 64.128 15.037 64.152 ;
     RECT  13.619 65.568 15.164 65.976 ;
     RECT  14.677 67.248 15.164 68.904 ;
     RECT  14.213 53.904 15.217 57.144 ;
     RECT  14.141 44.688 15.289 44.712 ;
     RECT  13.997 4.848 15.325 4.872 ;
     RECT  14.861 35.28 15.325 36.408 ;
     RECT  13.504 41.472 15.325 41.64 ;
     RECT  14.825 15.216 15.361 16.104 ;
     RECT  14.869 42.72 15.361 42.744 ;
     RECT  14.785 62.112 15.361 62.136 ;
     RECT  15.325 4.08 15.397 4.872 ;
     RECT  15.361 62.112 15.493 62.664 ;
     RECT  15.037 63.792 15.493 64.152 ;
     RECT  15.217 53.904 15.613 57.432 ;
     RECT  14.797 58.656 15.613 60.264 ;
     RECT  14.717 51.744 15.685 52.44 ;
     RECT  15.325 2.88 15.733 2.904 ;
     RECT  15.397 4.08 15.733 5.592 ;
     RECT  14.681 8.688 15.781 9.624 ;
     RECT  14.861 32.736 15.793 32.76 ;
     RECT  15.733 2.88 15.908 5.592 ;
     RECT  14.753 6.72 15.908 7.224 ;
     RECT  15.781 8.496 15.908 9.624 ;
     RECT  13.504 11.376 15.908 11.4 ;
     RECT  14.357 12.528 15.908 12.552 ;
     RECT  14.908 13.824 15.908 13.896 ;
     RECT  15.361 15.216 15.908 16.392 ;
     RECT  14.789 17.616 15.908 17.64 ;
     RECT  14.819 19.248 15.908 25.608 ;
     RECT  14.717 26.64 15.908 27.336 ;
     RECT  14.933 29.28 15.908 31.176 ;
     RECT  15.793 32.736 15.908 33.096 ;
     RECT  15.325 35.28 15.908 36.504 ;
     RECT  15.577 39.216 15.908 39.24 ;
     RECT  15.325 40.656 15.908 41.64 ;
     RECT  15.361 42.72 15.908 43.368 ;
     RECT  15.289 44.64 15.908 44.712 ;
     RECT  14.861 46.032 15.908 47.112 ;
     RECT  14.573 49.056 15.908 50.136 ;
     RECT  15.685 51.744 15.908 52.584 ;
     RECT  15.613 53.904 15.908 60.264 ;
     RECT  15.493 62.112 15.908 64.152 ;
     RECT  15.164 65.568 15.908 68.904 ;
     RECT  13.504 70.8 15.908 70.824 ;
     RECT  15.908 2.148 16.012 75.612 ;
     RECT  16.012 2.418 16.204 75.342 ;
     RECT  16.204 39.216 16.229 39.24 ;
     RECT  16.204 32.736 16.301 33.096 ;
     RECT  16.204 44.448 16.337 46.056 ;
     RECT  16.204 15.216 16.355 16.392 ;
     RECT  16.204 17.616 16.355 17.64 ;
     RECT  16.204 18.624 16.355 24.984 ;
     RECT  16.204 70.8 16.355 70.824 ;
     RECT  16.204 42.72 16.409 43.368 ;
     RECT  16.204 48.432 16.451 49.944 ;
     RECT  16.204 3.888 16.595 6.84 ;
     RECT  16.595 3.888 16.633 5.592 ;
     RECT  16.204 67.344 16.661 68.808 ;
     RECT  16.204 62.64 16.739 65.784 ;
     RECT  16.739 62.64 16.741 63.24 ;
     RECT  16.204 57.408 16.769 57.432 ;
     RECT  16.451 49.92 16.787 49.944 ;
     RECT  16.204 51.888 16.787 54.024 ;
     RECT  16.204 55.872 16.805 56.28 ;
     RECT  16.739 64.32 16.841 65.784 ;
     RECT  16.805 56.256 16.877 56.28 ;
     RECT  16.204 34.56 16.924 35.016 ;
     RECT  16.595 6.72 16.949 6.84 ;
     RECT  16.661 67.776 16.979 68.808 ;
     RECT  16.204 59.76 16.985 60.696 ;
     RECT  16.979 67.776 17.02 68.424 ;
     RECT  16.204 36.144 17.021 38.184 ;
     RECT  16.337 44.448 17.027 45.672 ;
     RECT  16.924 34.704 17.057 35.016 ;
     RECT  17.027 44.448 17.123 45.048 ;
     RECT  16.204 2.88 17.129 2.904 ;
     RECT  16.204 11.136 17.129 13.128 ;
     RECT  17.123 44.448 17.129 44.664 ;
     RECT  16.787 52.176 17.233 54.024 ;
     RECT  16.633 3.936 17.237 5.592 ;
     RECT  16.301 32.736 17.269 32.856 ;
     RECT  17.021 36.144 17.305 36.36 ;
     RECT  16.204 9.504 17.309 9.864 ;
     RECT  17.309 9.504 17.317 9.672 ;
     RECT  17.269 32.736 17.341 33.576 ;
     RECT  17.021 37.344 17.341 38.184 ;
     RECT  16.841 64.32 17.345 65.592 ;
     RECT  17.02 68.112 17.345 68.424 ;
     RECT  17.129 12.192 17.363 12.408 ;
     RECT  16.355 21.12 17.363 24.984 ;
     RECT  16.355 15.216 17.377 16.344 ;
     RECT  17.237 3.936 17.381 3.96 ;
     RECT  17.363 22.8 17.381 24.984 ;
     RECT  16.355 18.624 17.413 19.512 ;
     RECT  16.204 40.656 17.413 40.68 ;
     RECT  16.204 58.704 17.413 58.728 ;
     RECT  17.129 11.136 17.417 11.16 ;
     RECT  17.413 18.624 17.42 19.56 ;
     RECT  17.381 22.848 17.449 24.984 ;
     RECT  16.204 30.048 17.449 30.744 ;
     RECT  17.345 68.4 17.453 68.424 ;
     RECT  17.42 18.528 17.461 19.56 ;
     RECT  17.413 40.656 17.485 41.544 ;
     RECT  16.409 42.72 17.485 42.744 ;
     RECT  17.461 18.144 17.557 19.56 ;
     RECT  17.129 44.64 17.597 44.664 ;
     RECT  17.557 18.144 17.629 20.136 ;
     RECT  17.363 21.12 17.629 21.72 ;
     RECT  17.377 15.216 17.665 16.968 ;
     RECT  17.449 22.848 17.701 25.176 ;
     RECT  16.204 26.544 17.701 27.096 ;
     RECT  17.305 28.272 17.701 28.296 ;
     RECT  17.237 5.568 17.737 5.592 ;
     RECT  17.701 22.848 17.797 25.272 ;
     RECT  17.701 26.544 17.797 28.296 ;
     RECT  17.521 50.832 17.809 50.856 ;
     RECT  17.233 52.176 17.809 54.12 ;
     RECT  16.741 63.216 17.845 63.24 ;
     RECT  17.345 64.32 17.845 64.872 ;
     RECT  16.204 47.088 17.881 47.112 ;
     RECT  16.985 59.76 18.044 60.168 ;
     RECT  17.413 61.296 18.044 61.32 ;
     RECT  17.449 29.76 18.061 30.744 ;
     RECT  17.341 32.304 18.169 33.576 ;
     RECT  17.057 34.704 18.169 34.92 ;
     RECT  17.485 42.72 18.169 42.984 ;
     RECT  18.169 42.72 18.205 43.608 ;
     RECT  17.737 5.568 18.349 5.784 ;
     RECT  17.413 58.08 18.349 58.728 ;
     RECT  18.044 59.76 18.349 61.32 ;
     RECT  18.349 5.52 18.373 5.784 ;
     RECT  16.949 6.816 18.373 6.84 ;
     RECT  17.593 66.672 18.373 66.696 ;
     RECT  17.665 14.592 18.38 16.968 ;
     RECT  17.363 12.384 18.385 12.408 ;
     RECT  17.305 35.952 18.385 36.36 ;
     RECT  17.341 37.344 18.385 38.376 ;
     RECT  17.317 8.976 18.421 9.672 ;
     RECT  17.797 22.848 18.469 28.296 ;
     RECT  17.809 50.832 18.493 54.12 ;
     RECT  17.809 55.248 18.493 55.272 ;
     RECT  18.493 3.84 18.529 3.864 ;
     RECT  17.485 40.416 18.565 41.544 ;
     RECT  18.205 42.528 18.565 43.608 ;
     RECT  18.565 40.416 18.601 43.608 ;
     RECT  18.529 3.648 18.608 3.864 ;
     RECT  18.373 5.52 18.608 6.84 ;
     RECT  18.421 8.976 18.608 10.2 ;
     RECT  18.385 11.424 18.608 12.408 ;
     RECT  18.529 13.584 18.608 13.608 ;
     RECT  18.38 14.592 18.608 17.112 ;
     RECT  17.629 18.144 18.608 21.72 ;
     RECT  18.469 22.848 18.608 28.488 ;
     RECT  18.061 29.76 18.608 31.128 ;
     RECT  18.169 32.304 18.608 34.92 ;
     RECT  18.385 35.952 18.608 38.376 ;
     RECT  18.601 39.792 18.608 43.608 ;
     RECT  17.881 46.224 18.608 47.112 ;
     RECT  16.451 48.48 18.608 48.504 ;
     RECT  18.601 49.488 18.608 49.512 ;
     RECT  18.493 50.832 18.608 55.272 ;
     RECT  18.205 56.976 18.608 57 ;
     RECT  18.349 58.08 18.608 61.32 ;
     RECT  17.845 63.216 18.608 64.872 ;
     RECT  18.373 66.096 18.608 66.696 ;
     RECT  18.608 2.148 18.712 75.612 ;
     RECT  18.712 2.418 18.904 75.342 ;
     RECT  18.904 23.568 18.965 23.592 ;
     RECT  18.904 36 18.965 38.184 ;
     RECT  18.904 41.952 19.001 44.904 ;
     RECT  18.904 67.68 19.045 68.424 ;
     RECT  18.904 5.76 19.109 9.912 ;
     RECT  18.904 19.536 19.109 19.56 ;
     RECT  18.965 36.336 19.109 38.184 ;
     RECT  18.904 50.544 19.187 50.904 ;
     RECT  18.904 26.784 19.283 30.792 ;
     RECT  18.904 16.56 19.297 17.784 ;
     RECT  19.109 5.76 19.324 9.336 ;
     RECT  19.001 41.952 19.361 43.704 ;
     RECT  18.904 13.104 19.397 15.48 ;
     RECT  18.904 48.528 19.397 49.512 ;
     RECT  19.324 5.76 19.523 7.992 ;
     RECT  18.904 63.84 19.541 64.632 ;
     RECT  19.397 13.152 19.577 15.48 ;
     RECT  19.324 8.976 19.613 9.336 ;
     RECT  18.904 11.136 19.649 11.976 ;
     RECT  19.297 16.608 19.721 17.784 ;
     RECT  19.721 17.328 19.829 17.784 ;
     RECT  18.904 39.312 19.897 40.92 ;
     RECT  19.361 41.952 19.897 43.608 ;
     RECT  18.904 55.968 19.897 55.992 ;
     RECT  19.577 13.296 19.937 15.48 ;
     RECT  19.897 55.968 19.957 56.664 ;
     RECT  18.904 58.128 19.957 58.968 ;
     RECT  19.283 26.784 19.973 26.808 ;
     RECT  18.904 3.6 20.005 4.008 ;
     RECT  19.397 48.528 20.041 48.984 ;
     RECT  18.904 51.984 20.041 54.408 ;
     RECT  19.957 55.968 20.041 58.968 ;
     RECT  20.041 51.984 20.081 58.968 ;
     RECT  20.041 48.384 20.117 48.984 ;
     RECT  19.109 36.336 20.149 37.608 ;
     RECT  19.897 39.264 20.149 43.608 ;
     RECT  20.005 3.264 20.185 4.008 ;
     RECT  20.149 36.336 20.185 43.608 ;
     RECT  18.904 46.128 20.221 47.112 ;
     RECT  20.117 48.384 20.221 48.408 ;
     RECT  19.187 50.88 20.221 50.904 ;
     RECT  20.081 51.984 20.221 57.624 ;
     RECT  19.937 14.16 20.225 15.48 ;
     RECT  20.221 50.88 20.261 57.624 ;
     RECT  19.283 27.792 20.293 30.792 ;
     RECT  20.293 27.792 20.329 30.984 ;
     RECT  19.829 17.328 20.333 17.64 ;
     RECT  20.185 36.096 20.333 43.608 ;
     RECT  18.904 32.304 20.437 34.92 ;
     RECT  20.333 36.096 20.437 39.288 ;
     RECT  20.333 40.608 20.437 43.608 ;
     RECT  19.001 44.736 20.437 44.904 ;
     RECT  20.185 3.264 20.473 4.44 ;
     RECT  20.329 27.792 20.509 31.224 ;
     RECT  18.904 24.96 20.533 25.272 ;
     RECT  19.541 63.84 20.54 64.392 ;
     RECT  20.54 63.648 20.573 64.392 ;
     RECT  19.523 5.76 20.581 7.368 ;
     RECT  20.261 50.88 20.581 57.144 ;
     RECT  20.533 24.96 20.761 25.656 ;
     RECT  20.509 27.36 20.761 31.224 ;
     RECT  20.437 32.304 20.761 39.288 ;
     RECT  20.365 21.408 20.833 21.432 ;
     RECT  20.437 40.608 20.941 44.904 ;
     RECT  20.221 46.128 20.941 48.408 ;
     RECT  19.649 11.136 20.977 11.496 ;
     RECT  20.977 10.656 21.049 11.496 ;
     RECT  20.581 50.832 21.049 57.144 ;
     RECT  18.904 60.672 21.061 62.088 ;
     RECT  21.049 10.608 21.085 11.496 ;
     RECT  19.613 8.976 21.109 9 ;
     RECT  21.085 10.608 21.109 11.784 ;
     RECT  21.109 8.976 21.121 11.784 ;
     RECT  20.761 24.96 21.121 26.28 ;
     RECT  20.761 27.36 21.121 39.288 ;
     RECT  21.121 8.976 21.157 12.264 ;
     RECT  20.225 14.16 21.157 15.384 ;
     RECT  20.833 21.12 21.157 21.432 ;
     RECT  20.581 5.76 21.265 7.944 ;
     RECT  21.157 8.976 21.265 12.36 ;
     RECT  21.157 13.728 21.301 15.384 ;
     RECT  20.473 3.264 21.308 4.776 ;
     RECT  21.265 5.76 21.308 12.36 ;
     RECT  21.301 13.728 21.308 15.768 ;
     RECT  20.333 17.376 21.308 17.64 ;
     RECT  21.157 20.4 21.308 21.432 ;
     RECT  20.293 23.28 21.308 23.304 ;
     RECT  21.121 24.96 21.308 39.288 ;
     RECT  20.941 40.608 21.308 48.408 ;
     RECT  21.049 50.064 21.308 57.144 ;
     RECT  20.081 58.608 21.308 58.968 ;
     RECT  21.061 60.672 21.308 62.328 ;
     RECT  20.573 63.648 21.308 65.016 ;
     RECT  19.045 67.68 21.308 67.704 ;
     RECT  21.308 2.148 21.445 75.612 ;
     RECT  21.445 2.148 21.541 75.816 ;
     RECT  21.541 1.728 21.587 75.816 ;
     RECT  21.587 1.728 21.604 75.342 ;
     RECT  21.604 6.912 21.629 9.528 ;
     RECT  21.604 15.216 21.629 15.864 ;
     RECT  21.604 1.728 21.665 1.752 ;
     RECT  21.604 30.528 21.665 44.904 ;
     RECT  21.604 5.808 21.701 5.832 ;
     RECT  21.604 50.832 21.701 52.296 ;
     RECT  21.604 10.608 21.731 14.136 ;
     RECT  21.701 50.88 21.737 52.296 ;
     RECT  21.629 8.4 21.773 9.528 ;
     RECT  21.773 8.4 21.792 9.24 ;
     RECT  21.731 10.944 21.809 14.136 ;
     RECT  21.809 13.152 21.881 14.136 ;
     RECT  21.737 50.88 21.881 52.2 ;
     RECT  21.604 63.216 21.881 64.392 ;
     RECT  21.604 27.36 21.953 27.96 ;
     RECT  21.629 6.912 21.989 7.368 ;
     RECT  21.604 60.96 21.989 61.656 ;
     RECT  21.604 18.144 22.277 18.696 ;
     RECT  21.881 63.216 22.349 64.056 ;
     RECT  21.604 19.92 22.403 21.384 ;
     RECT  21.604 24.72 22.457 25.704 ;
     RECT  22.277 18.24 22.601 18.696 ;
     RECT  21.604 16.896 22.636 16.92 ;
     RECT  21.604 45.936 22.636 47.304 ;
     RECT  21.604 48.384 22.669 48.408 ;
     RECT  21.881 51.216 22.705 52.2 ;
     RECT  21.665 44.784 22.709 44.904 ;
     RECT  21.604 53.568 22.741 57.144 ;
     RECT  22.709 44.88 22.745 44.904 ;
     RECT  21.809 10.944 22.777 11.448 ;
     RECT  22.403 20.304 22.777 21.384 ;
     RECT  22.777 10.848 22.789 11.448 ;
     RECT  22.457 24.72 22.813 25.224 ;
     RECT  21.604 23.28 22.853 23.304 ;
     RECT  21.604 68.928 22.853 68.952 ;
     RECT  22.789 10.08 22.876 11.448 ;
     RECT  21.881 13.152 22.885 13.272 ;
     RECT  21.604 29.088 22.885 29.112 ;
     RECT  21.665 30.528 22.885 43.752 ;
     RECT  22.636 45.936 22.889 46.92 ;
     RECT  22.885 13.152 22.921 13.848 ;
     RECT  22.885 29.088 22.925 43.752 ;
     RECT  22.921 13.152 22.957 14.04 ;
     RECT  22.669 47.904 22.961 48.408 ;
     RECT  21.989 6.912 22.993 6.936 ;
     RECT  22.349 63.216 23.065 63.864 ;
     RECT  22.993 6.912 23.101 7.416 ;
     RECT  21.792 8.4 23.101 8.424 ;
     RECT  23.101 6.912 23.137 8.424 ;
     RECT  22.705 51.216 23.281 52.44 ;
     RECT  21.604 58.704 23.281 59.928 ;
     RECT  21.989 61.632 23.281 61.656 ;
     RECT  22.885 69.456 23.365 69.48 ;
     RECT  21.604 71.472 23.365 71.496 ;
     RECT  23.281 50.784 23.461 52.44 ;
     RECT  21.604 2.832 23.497 2.856 ;
     RECT  21.604 3.936 23.497 4.536 ;
     RECT  23.281 58.704 23.509 61.656 ;
     RECT  23.509 58.464 23.569 61.656 ;
     RECT  23.137 6.288 23.605 8.424 ;
     RECT  22.957 13.152 23.605 14.184 ;
     RECT  22.889 46.176 23.641 46.92 ;
     RECT  22.961 47.904 23.641 47.928 ;
     RECT  21.953 27.36 23.677 27.912 ;
     RECT  22.813 24.432 23.797 25.224 ;
     RECT  23.677 26.784 23.797 27.912 ;
     RECT  23.605 6.288 23.857 9.144 ;
     RECT  23.509 65.568 23.857 65.592 ;
     RECT  23.461 50.784 23.893 52.488 ;
     RECT  22.741 53.52 23.893 57.144 ;
     RECT  23.893 50.784 23.929 57.144 ;
     RECT  23.569 58.128 23.929 61.656 ;
     RECT  23.497 2.832 24.008 4.536 ;
     RECT  23.857 5.568 24.008 9.144 ;
     RECT  22.876 10.992 24.008 11.448 ;
     RECT  23.605 13.008 24.008 14.184 ;
     RECT  21.629 15.84 24.008 15.864 ;
     RECT  22.601 18.24 24.008 18.504 ;
     RECT  22.777 20.304 24.008 21.96 ;
     RECT  23.797 24.432 24.008 27.912 ;
     RECT  22.925 29.136 24.008 42.552 ;
     RECT  22.925 43.632 24.008 43.752 ;
     RECT  22.921 44.976 24.008 45.192 ;
     RECT  23.641 46.176 24.008 47.928 ;
     RECT  23.929 50.784 24.008 61.656 ;
     RECT  23.065 63.072 24.008 63.864 ;
     RECT  23.857 65.568 24.008 66.312 ;
     RECT  23.857 67.344 24.008 67.368 ;
     RECT  23.101 68.352 24.008 68.376 ;
     RECT  23.365 69.456 24.008 69.864 ;
     RECT  23.365 70.896 24.008 71.496 ;
     RECT  24.008 2.148 24.112 75.612 ;
     RECT  24.112 2.418 24.304 75.342 ;
     RECT  24.304 7.632 24.365 10.968 ;
     RECT  24.304 24.432 24.365 26.808 ;
     RECT  24.304 5.568 24.419 5.688 ;
     RECT  24.304 43.872 24.419 58.728 ;
     RECT  24.419 43.872 24.467 53.976 ;
     RECT  24.304 15.984 24.553 16.008 ;
     RECT  24.365 7.632 24.617 7.944 ;
     RECT  24.304 29.76 24.617 42.744 ;
     RECT  24.617 7.92 24.689 7.944 ;
     RECT  24.419 55.392 24.689 58.728 ;
     RECT  24.304 60.816 24.689 61.656 ;
     RECT  24.365 24.48 24.841 26.808 ;
     RECT  24.365 9.072 25.193 10.968 ;
     RECT  24.841 24.96 25.229 26.808 ;
     RECT  24.467 43.872 25.229 50.28 ;
     RECT  24.304 66.096 25.235 67.848 ;
     RECT  24.689 55.536 25.301 58.728 ;
     RECT  25.235 66.288 25.369 67.848 ;
     RECT  24.467 51.264 25.373 53.976 ;
     RECT  24.419 5.664 25.441 5.688 ;
     RECT  24.304 63.072 25.477 64.728 ;
     RECT  25.441 5.424 25.481 5.688 ;
     RECT  25.297 19.776 25.513 19.8 ;
     RECT  25.229 43.872 25.571 47.16 ;
     RECT  24.304 4.08 25.621 4.44 ;
     RECT  24.617 34.368 25.657 42.744 ;
     RECT  25.571 43.872 25.657 45.336 ;
     RECT  24.304 17.568 25.697 18.264 ;
     RECT  25.229 48.288 25.729 50.28 ;
     RECT  25.373 51.264 25.729 53.88 ;
     RECT  25.697 17.664 25.733 18.264 ;
     RECT  25.621 3.36 25.916 4.44 ;
     RECT  25.481 5.424 25.916 5.448 ;
     RECT  25.477 62.736 25.945 64.728 ;
     RECT  25.729 22.848 25.981 23.16 ;
     RECT  25.229 24.96 25.981 26.376 ;
     RECT  25.297 71.328 25.981 71.352 ;
     RECT  25.657 34.368 26.089 45.336 ;
     RECT  25.945 62.736 26.125 64.872 ;
     RECT  25.513 19.776 26.161 19.944 ;
     RECT  25.981 24.48 26.197 26.376 ;
     RECT  24.304 27.888 26.197 28.008 ;
     RECT  25.369 66.288 26.197 68.232 ;
     RECT  25.301 56.016 26.233 58.728 ;
     RECT  26.125 62.736 26.233 65.016 ;
     RECT  26.197 24.48 26.3 28.008 ;
     RECT  26.197 66.24 26.341 68.232 ;
     RECT  25.333 69.984 26.341 70.008 ;
     RECT  26.233 56.016 26.389 58.824 ;
     RECT  25.729 48.288 26.413 53.88 ;
     RECT  26.389 55.584 26.413 58.824 ;
     RECT  26.413 48.288 26.449 58.824 ;
     RECT  24.617 29.76 26.581 33.288 ;
     RECT  26.089 34.32 26.581 45.336 ;
     RECT  25.571 46.608 26.581 47.16 ;
     RECT  26.3 24.48 26.629 28.152 ;
     RECT  26.581 29.616 26.629 33.288 ;
     RECT  25.916 3.36 26.708 5.448 ;
     RECT  26.269 8.928 26.708 8.952 ;
     RECT  25.193 10.032 26.708 10.968 ;
     RECT  24.304 12 26.708 12.024 ;
     RECT  26.701 14.496 26.708 14.52 ;
     RECT  25.733 18.24 26.708 18.264 ;
     RECT  26.161 19.776 26.708 20.088 ;
     RECT  25.981 22.752 26.708 23.16 ;
     RECT  26.629 24.48 26.708 33.288 ;
     RECT  26.581 34.32 26.708 47.16 ;
     RECT  26.449 48.192 26.708 58.824 ;
     RECT  24.689 60.816 26.708 60.984 ;
     RECT  26.233 62.736 26.708 65.256 ;
     RECT  26.341 66.24 26.708 70.008 ;
     RECT  25.981 71.328 26.708 71.592 ;
     RECT  26.125 74.976 26.708 75 ;
     RECT  26.708 2.148 26.812 75.612 ;
     RECT  26.812 2.418 27.004 75.342 ;
     RECT  27.004 44.448 27.065 53.976 ;
     RECT  27.004 73.776 27.065 75 ;
     RECT  27.004 28.464 27.155 43.128 ;
     RECT  27.004 55.008 27.155 60.408 ;
     RECT  27.065 44.832 27.173 53.976 ;
     RECT  27.173 46.32 27.245 53.976 ;
     RECT  27.245 49.008 27.281 53.976 ;
     RECT  27.004 23.904 27.317 23.928 ;
     RECT  27.004 3.36 27.389 3.384 ;
     RECT  27.155 30.72 27.389 43.128 ;
     RECT  27.155 55.68 27.389 60.408 ;
     RECT  27.389 55.92 27.395 60.408 ;
     RECT  27.155 28.464 27.532 29.256 ;
     RECT  27.004 61.776 27.532 67.656 ;
     RECT  27.281 49.008 27.587 53.592 ;
     RECT  27.587 50.928 27.605 53.592 ;
     RECT  27.004 68.928 27.605 70.728 ;
     RECT  27.389 38.112 27.628 43.128 ;
     RECT  27.532 61.776 27.641 64.248 ;
     RECT  27.004 7.152 27.677 7.176 ;
     RECT  27.004 20.448 27.713 20.472 ;
     RECT  27.004 14.112 27.785 14.808 ;
     RECT  27.628 41.04 27.785 43.128 ;
     RECT  27.605 70.704 27.923 70.728 ;
     RECT  27.004 9.456 27.965 12.024 ;
     RECT  27.641 61.776 27.997 62.184 ;
     RECT  27.004 5.136 28.073 5.208 ;
     RECT  27.587 49.008 28.073 49.656 ;
     RECT  27.004 21.648 28.105 21.672 ;
     RECT  27.004 22.752 28.105 22.776 ;
     RECT  28.105 21.648 28.109 22.776 ;
     RECT  27.065 73.92 28.115 75 ;
     RECT  27.395 55.92 28.145 59.832 ;
     RECT  28.115 74.592 28.153 75 ;
     RECT  28.069 72.816 28.156 72.84 ;
     RECT  27.965 9.456 28.181 9.96 ;
     RECT  27.004 16.32 28.181 16.344 ;
     RECT  27.532 28.8 28.181 29.256 ;
     RECT  28.109 21.648 28.213 22.008 ;
     RECT  27.245 46.32 28.213 47.88 ;
     RECT  28.073 49.008 28.213 49.608 ;
     RECT  27.004 17.328 28.217 19.368 ;
     RECT  27.785 41.04 28.217 42.744 ;
     RECT  28.153 74.592 28.253 74.616 ;
     RECT  28.213 21.504 28.321 22.008 ;
     RECT  28.181 29.088 28.321 29.256 ;
     RECT  28.073 5.184 28.361 5.208 ;
     RECT  28.217 17.328 28.393 18.792 ;
     RECT  28.213 46.08 28.396 49.608 ;
     RECT  28.393 16.512 28.397 18.792 ;
     RECT  27.004 27.216 28.429 27.24 ;
     RECT  28.321 21.072 28.433 22.008 ;
     RECT  27.173 44.832 28.537 44.856 ;
     RECT  28.396 46.08 28.537 46.92 ;
     RECT  27.004 71.808 28.573 71.832 ;
     RECT  27.965 11.136 28.717 12.024 ;
     RECT  27.605 50.928 28.717 52.728 ;
     RECT  27.004 24.96 28.753 26.088 ;
     RECT  28.429 27.072 28.753 27.24 ;
     RECT  28.217 41.136 28.789 42.744 ;
     RECT  27.641 63.264 28.825 64.248 ;
     RECT  27.605 68.928 28.825 69.48 ;
     RECT  28.753 24.96 28.969 27.912 ;
     RECT  27.997 61.632 29.005 62.184 ;
     RECT  28.825 63.264 29.005 64.392 ;
     RECT  28.717 50.832 29.041 52.728 ;
     RECT  29.005 61.632 29.077 64.392 ;
     RECT  27.532 65.568 29.077 67.656 ;
     RECT  28.861 7.344 29.113 7.368 ;
     RECT  27.389 30.72 29.185 36.936 ;
     RECT  27.628 38.112 29.185 39.864 ;
     RECT  28.181 9.456 29.221 9.48 ;
     RECT  28.321 29.088 29.221 29.64 ;
     RECT  28.717 11.136 29.228 12.072 ;
     RECT  29.077 61.632 29.257 67.656 ;
     RECT  28.825 68.928 29.269 70.152 ;
     RECT  28.573 71.232 29.269 71.832 ;
     RECT  29.269 68.928 29.293 71.832 ;
     RECT  28.969 24.144 29.329 27.912 ;
     RECT  29.293 68.736 29.329 71.832 ;
     RECT  29.113 7.344 29.408 7.704 ;
     RECT  29.221 9.456 29.408 9.624 ;
     RECT  29.228 10.992 29.408 12.072 ;
     RECT  27.785 14.112 29.408 14.136 ;
     RECT  29.228 15.168 29.408 15.192 ;
     RECT  28.397 16.512 29.408 17.688 ;
     RECT  28.397 18.768 29.408 18.792 ;
     RECT  28.433 21.504 29.408 22.008 ;
     RECT  29.329 23.856 29.408 27.912 ;
     RECT  29.221 28.944 29.408 29.64 ;
     RECT  29.185 30.72 29.408 39.864 ;
     RECT  28.789 41.136 29.408 42.84 ;
     RECT  28.573 43.824 29.408 43.848 ;
     RECT  28.537 44.832 29.408 46.92 ;
     RECT  28.396 48.144 29.408 49.608 ;
     RECT  29.041 50.832 29.408 53.064 ;
     RECT  28.609 54.864 29.408 54.888 ;
     RECT  28.145 55.92 29.408 59.736 ;
     RECT  29.257 60.816 29.408 67.656 ;
     RECT  29.329 68.736 29.408 72.168 ;
     RECT  29.408 2.148 29.512 75.612 ;
     RECT  29.512 2.418 29.704 75.342 ;
     RECT  29.704 28.944 29.765 29.64 ;
     RECT  29.704 11.184 29.801 12.552 ;
     RECT  29.704 41.136 29.843 63.288 ;
     RECT  29.801 12 29.909 12.552 ;
     RECT  29.843 41.136 29.909 53.592 ;
     RECT  29.909 41.616 30.125 53.592 ;
     RECT  30.125 48.96 30.233 53.592 ;
     RECT  29.909 12.048 30.269 12.552 ;
     RECT  29.704 30.672 30.275 33.048 ;
     RECT  30.269 12.192 30.313 12.552 ;
     RECT  30.125 41.616 30.521 47.832 ;
     RECT  29.843 54.672 30.521 63.288 ;
     RECT  29.704 20.976 30.557 23.88 ;
     RECT  29.704 34.32 30.557 39.864 ;
     RECT  29.704 3.6 30.593 6.168 ;
     RECT  30.521 41.616 30.593 43.128 ;
     RECT  29.704 7.344 30.611 8.808 ;
     RECT  30.521 54.672 30.629 54.792 ;
     RECT  30.593 5.712 30.652 6.168 ;
     RECT  30.557 34.32 30.665 37.128 ;
     RECT  30.652 5.712 30.673 6.12 ;
     RECT  29.704 64.608 30.697 67.656 ;
     RECT  29.704 72.672 30.697 72.696 ;
     RECT  30.521 44.16 30.707 47.832 ;
     RECT  30.697 64.416 30.733 67.656 ;
     RECT  30.665 34.32 30.769 36.12 ;
     RECT  30.611 7.68 30.773 8.808 ;
     RECT  29.704 74.304 30.773 74.568 ;
     RECT  30.733 64.416 30.791 67.752 ;
     RECT  30.275 30.672 30.809 32.856 ;
     RECT  30.521 55.824 30.809 63.288 ;
     RECT  30.697 72.672 30.809 72.792 ;
     RECT  30.593 3.6 30.845 4.632 ;
     RECT  30.707 46.32 30.845 47.832 ;
     RECT  30.809 55.824 30.845 61.08 ;
     RECT  30.773 74.352 30.845 74.568 ;
     RECT  30.809 62.16 30.877 63.288 ;
     RECT  30.791 64.368 30.877 67.752 ;
     RECT  29.704 68.736 30.877 68.952 ;
     RECT  30.845 74.448 30.881 74.568 ;
     RECT  30.557 38.448 30.913 39.864 ;
     RECT  30.809 72.768 30.913 72.792 ;
     RECT  30.673 6.096 30.917 6.12 ;
     RECT  30.707 44.16 30.953 45.192 ;
     RECT  30.881 74.544 30.953 74.568 ;
     RECT  30.773 8.304 30.989 8.808 ;
     RECT  30.877 68.736 30.989 69.576 ;
     RECT  29.704 16.464 31.021 16.488 ;
     RECT  30.769 33.888 31.097 36.12 ;
     RECT  30.913 72.768 31.097 72.936 ;
     RECT  31.021 15.696 31.129 16.488 ;
     RECT  30.233 49.296 31.141 53.592 ;
     RECT  30.629 54.672 31.141 54.696 ;
     RECT  29.704 17.952 31.165 17.976 ;
     RECT  31.141 49.296 31.201 54.696 ;
     RECT  30.877 62.16 31.201 67.752 ;
     RECT  30.989 68.736 31.201 69.48 ;
     RECT  30.557 21.936 31.237 23.88 ;
     RECT  29.704 24.864 31.237 27.72 ;
     RECT  31.165 17.952 31.309 18.792 ;
     RECT  31.093 20.256 31.309 20.28 ;
     RECT  30.845 46.752 31.453 47.832 ;
     RECT  31.201 49.008 31.453 54.696 ;
     RECT  29.765 28.992 31.525 29.64 ;
     RECT  30.809 30.672 31.525 32.808 ;
     RECT  30.313 12.192 31.561 12.312 ;
     RECT  30.593 41.952 31.597 43.128 ;
     RECT  31.309 17.952 31.628 20.28 ;
     RECT  31.237 21.936 31.669 27.72 ;
     RECT  30.665 37.104 31.669 37.128 ;
     RECT  30.913 38.448 31.669 40.056 ;
     RECT  31.453 46.752 31.813 54.696 ;
     RECT  30.845 55.824 31.813 57.144 ;
     RECT  31.237 10.944 31.82 10.968 ;
     RECT  31.628 17.952 31.877 20.328 ;
     RECT  31.669 21.648 31.877 27.72 ;
     RECT  30.845 4.608 31.885 4.632 ;
     RECT  31.885 4.608 31.957 5.592 ;
     RECT  31.129 14.832 31.957 16.488 ;
     RECT  31.597 41.28 31.957 43.128 ;
     RECT  30.953 44.208 31.957 45.192 ;
     RECT  31.201 62.16 31.957 69.48 ;
     RECT  31.949 70.704 31.957 70.728 ;
     RECT  30.949 2.928 32.108 3.432 ;
     RECT  31.957 4.416 32.108 5.592 ;
     RECT  30.989 8.304 32.108 8.328 ;
     RECT  31.669 9.504 32.108 9.528 ;
     RECT  31.82 10.56 32.108 10.968 ;
     RECT  31.561 12.192 32.108 12.504 ;
     RECT  31.957 14.4 32.108 16.488 ;
     RECT  31.877 17.952 32.108 27.72 ;
     RECT  31.525 28.992 32.108 32.808 ;
     RECT  31.097 33.888 32.108 35.496 ;
     RECT  31.669 37.104 32.108 40.056 ;
     RECT  31.957 41.28 32.108 45.192 ;
     RECT  31.813 46.752 32.108 57.144 ;
     RECT  30.845 58.224 32.108 61.08 ;
     RECT  31.957 62.16 32.108 70.728 ;
     RECT  31.097 72.912 32.108 72.936 ;
     RECT  32.108 2.148 32.212 75.612 ;
     RECT  32.212 2.418 32.404 75.342 ;
     RECT  32.404 4.752 32.501 5.592 ;
     RECT  32.501 4.752 32.537 4.776 ;
     RECT  32.404 27.696 32.537 27.72 ;
     RECT  32.404 62.16 32.579 67.656 ;
     RECT  32.404 25.2 32.609 26.616 ;
     RECT  32.579 64.32 32.645 67.656 ;
     RECT  32.645 64.32 32.723 67.464 ;
     RECT  32.404 7.632 32.789 7.992 ;
     RECT  32.404 28.992 32.819 29.544 ;
     RECT  32.404 55.44 32.825 61.08 ;
     RECT  32.819 28.992 32.861 29.352 ;
     RECT  32.404 46.272 32.897 49.032 ;
     RECT  32.404 68.928 33.005 70.152 ;
     RECT  32.404 9.12 33.077 10.152 ;
     RECT  32.609 26.592 33.077 26.616 ;
     RECT  32.404 41.28 33.113 43.368 ;
     RECT  33.005 70.128 33.113 70.152 ;
     RECT  32.404 72.24 33.185 72.264 ;
     RECT  32.404 44.88 33.221 45.192 ;
     RECT  32.723 64.368 33.221 67.464 ;
     RECT  32.861 28.992 33.257 29.256 ;
     RECT  33.221 64.368 33.329 64.392 ;
     RECT  33.221 65.568 33.329 67.464 ;
     RECT  32.404 3.072 33.397 3.432 ;
     RECT  32.404 31.44 33.397 40.104 ;
     RECT  32.825 55.44 33.401 58.248 ;
     RECT  33.397 31.152 33.469 40.104 ;
     RECT  32.825 59.232 33.509 61.08 ;
     RECT  32.404 50.544 33.541 54.12 ;
     RECT  33.401 55.44 33.541 58.2 ;
     RECT  32.404 11.472 33.577 13.896 ;
     RECT  33.469 30.864 33.577 40.104 ;
     RECT  33.329 66.48 33.617 67.464 ;
     RECT  33.577 11.376 33.621 13.896 ;
     RECT  32.404 15.264 33.621 16.584 ;
     RECT  33.077 9.264 33.649 10.152 ;
     RECT  33.621 11.376 33.649 16.584 ;
     RECT  32.404 22.368 33.653 23.88 ;
     RECT  32.579 62.16 33.721 62.856 ;
     RECT  32.789 7.632 33.793 7.656 ;
     RECT  33.793 6.672 33.901 7.656 ;
     RECT  33.901 6.624 33.925 7.656 ;
     RECT  32.404 17.616 33.932 19.032 ;
     RECT  33.649 9.264 33.973 16.584 ;
     RECT  33.932 17.616 33.973 19.224 ;
     RECT  33.973 9.264 34.018 19.224 ;
     RECT  33.577 30.816 34.081 40.104 ;
     RECT  33.113 41.28 34.081 42.216 ;
     RECT  34.018 9.264 34.117 19.272 ;
     RECT  34.081 30.816 34.117 42.216 ;
     RECT  32.404 20.304 34.153 20.328 ;
     RECT  32.609 25.2 34.153 25.224 ;
     RECT  33.925 5.664 34.213 7.656 ;
     RECT  33.005 68.928 34.213 68.952 ;
     RECT  33.397 3.072 34.225 3.72 ;
     RECT  33.257 28.992 34.261 29.16 ;
     RECT  34.153 73.776 34.261 73.8 ;
     RECT  32.897 48.384 34.297 49.032 ;
     RECT  33.541 50.544 34.297 58.2 ;
     RECT  34.153 20.304 34.333 20.904 ;
     RECT  34.117 8.784 34.357 19.272 ;
     RECT  34.333 20.304 34.357 21.096 ;
     RECT  32.897 46.272 34.357 47.112 ;
     RECT  34.297 48.384 34.357 58.2 ;
     RECT  34.117 30.816 34.513 42.264 ;
     RECT  33.721 62.16 34.513 63.816 ;
     RECT  34.213 65.232 34.513 65.256 ;
     RECT  33.617 66.48 34.513 67.272 ;
     RECT  34.357 46.272 34.549 58.2 ;
     RECT  34.225 71.136 34.549 71.16 ;
     RECT  34.513 65.232 34.621 67.272 ;
     RECT  34.549 71.136 34.621 71.208 ;
     RECT  34.621 43.824 34.657 43.848 ;
     RECT  33.221 45.168 34.657 45.192 ;
     RECT  34.153 24.912 34.693 25.224 ;
     RECT  34.513 62.16 34.693 63.864 ;
     RECT  34.621 65.232 34.693 67.368 ;
     RECT  34.213 68.736 34.729 68.952 ;
     RECT  34.081 70.08 34.729 70.104 ;
     RECT  34.621 71.088 34.729 71.208 ;
     RECT  34.117 27.888 34.765 27.912 ;
     RECT  34.261 28.992 34.765 29.304 ;
     RECT  34.225 3.072 34.808 4.488 ;
     RECT  34.213 5.664 34.808 7.704 ;
     RECT  34.357 8.784 34.808 21.096 ;
     RECT  33.653 22.368 34.808 23.112 ;
     RECT  34.693 24.912 34.808 25.56 ;
     RECT  34.081 26.784 34.808 26.808 ;
     RECT  34.765 27.888 34.808 29.304 ;
     RECT  34.513 30.816 34.808 42.792 ;
     RECT  34.657 43.824 34.808 45.192 ;
     RECT  34.549 46.272 34.808 58.248 ;
     RECT  33.509 59.232 34.808 60.84 ;
     RECT  34.693 62.16 34.808 67.368 ;
     RECT  34.729 68.736 34.808 71.208 ;
     RECT  34.261 72.912 34.808 73.8 ;
     RECT  34.808 2.148 34.912 75.612 ;
     RECT  34.912 2.418 35.104 75.342 ;
     RECT  35.104 65.664 35.165 66.552 ;
     RECT  35.104 8.736 35.219 13.944 ;
     RECT  35.104 15.36 35.219 43.32 ;
     RECT  35.219 20.544 35.237 43.32 ;
     RECT  35.104 56.256 35.237 56.616 ;
     RECT  35.104 59.856 35.267 62.856 ;
     RECT  35.237 20.544 35.273 29.304 ;
     RECT  35.267 61.008 35.309 62.856 ;
     RECT  35.104 73.008 35.309 73.56 ;
     RECT  35.104 67.824 35.353 71.4 ;
     RECT  35.273 25.056 35.363 29.304 ;
     RECT  35.237 30.336 35.363 43.32 ;
     RECT  35.309 62.16 35.381 62.856 ;
     RECT  35.219 8.784 35.417 13.944 ;
     RECT  35.267 59.856 35.417 59.88 ;
     RECT  35.353 67.824 35.489 68.952 ;
     RECT  35.417 8.784 35.525 8.856 ;
     RECT  35.363 30.336 35.561 37.128 ;
     RECT  35.363 25.056 35.597 26.808 ;
     RECT  35.104 45.024 35.597 50.904 ;
     RECT  35.417 13.92 35.633 13.944 ;
     RECT  35.273 20.544 35.633 22.488 ;
     RECT  35.309 61.008 35.633 61.032 ;
     RECT  35.219 15.36 35.705 19.272 ;
     RECT  35.633 20.592 35.741 21.72 ;
     RECT  35.705 15.84 35.777 19.272 ;
     RECT  35.104 3.072 35.813 4.056 ;
     RECT  35.561 34.176 35.957 37.128 ;
     RECT  35.273 23.952 36.001 23.976 ;
     RECT  35.363 28.464 36.029 29.304 ;
     RECT  35.237 56.304 36.029 56.616 ;
     RECT  35.597 25.056 36.035 26.76 ;
     RECT  35.104 5.856 36.085 7.704 ;
     RECT  35.104 51.936 36.097 52.296 ;
     RECT  35.363 38.16 36.133 43.32 ;
     RECT  36.085 5.856 36.172 7.8 ;
     RECT  35.165 66.528 36.205 66.552 ;
     RECT  35.417 10.128 36.245 12.408 ;
     RECT  35.104 54.432 36.277 54.936 ;
     RECT  35.104 57.696 36.277 58.392 ;
     RECT  35.353 70.272 36.281 71.4 ;
     RECT  35.597 50.112 36.349 50.904 ;
     RECT  36.097 51.936 36.349 52.488 ;
     RECT  36.205 65.664 36.353 66.552 ;
     RECT  36.172 5.856 36.373 7.656 ;
     RECT  36.373 5.376 36.385 7.656 ;
     RECT  36.133 38.16 36.421 43.56 ;
     RECT  35.597 45.024 36.421 49.08 ;
     RECT  35.813 3.168 36.467 4.056 ;
     RECT  36.349 50.112 36.469 52.488 ;
     RECT  35.381 62.16 36.469 62.712 ;
     RECT  36.421 38.16 36.497 49.08 ;
     RECT  36.097 64.56 36.515 64.584 ;
     RECT  35.489 67.824 36.515 68.76 ;
     RECT  36.38 60.72 36.565 60.744 ;
     RECT  35.561 30.336 36.661 32.568 ;
     RECT  35.741 20.592 36.709 21.672 ;
     RECT  36.035 25.104 36.709 26.76 ;
     RECT  36.133 14.064 36.745 14.088 ;
     RECT  35.777 16.56 36.745 19.272 ;
     RECT  36.709 25.104 36.745 27.192 ;
     RECT  36.029 28.464 36.745 28.488 ;
     RECT  36.469 50.688 36.817 52.488 ;
     RECT  35.957 34.176 36.853 35.496 ;
     RECT  36.469 62.16 36.925 63.24 ;
     RECT  35.957 36.816 36.997 37.128 ;
     RECT  36.745 25.104 37.033 28.488 ;
     RECT  36.661 29.616 37.033 32.568 ;
     RECT  36.277 54.432 37.033 55.848 ;
     RECT  36.277 57.024 37.033 58.392 ;
     RECT  36.245 10.224 37.061 12.408 ;
     RECT  37.061 10.224 37.069 12.552 ;
     RECT  36.745 14.064 37.069 14.184 ;
     RECT  36.997 36.624 37.069 37.128 ;
     RECT  36.497 38.16 37.069 46.632 ;
     RECT  36.497 47.616 37.069 49.08 ;
     RECT  36.565 60.288 37.069 60.744 ;
     RECT  36.925 61.728 37.069 63.24 ;
     RECT  36.353 65.664 37.069 65.688 ;
     RECT  37.069 60.288 37.213 63.24 ;
     RECT  35.525 8.784 37.285 8.808 ;
     RECT  37.069 10.224 37.285 14.184 ;
     RECT  36.709 20.496 37.285 21.72 ;
     RECT  36.281 71.376 37.349 71.4 ;
     RECT  36.385 5.136 37.357 7.656 ;
     RECT  37.285 8.784 37.381 14.184 ;
     RECT  37.033 25.104 37.381 32.568 ;
     RECT  36.281 70.272 37.381 70.296 ;
     RECT  37.349 71.376 37.381 72.312 ;
     RECT  35.309 73.536 37.381 73.56 ;
     RECT  36.467 3.6 37.508 4.056 ;
     RECT  37.357 5.088 37.508 7.656 ;
     RECT  37.381 8.784 37.508 15.048 ;
     RECT  36.745 16.368 37.508 19.272 ;
     RECT  37.285 20.4 37.508 21.72 ;
     RECT  37.177 22.752 37.508 22.776 ;
     RECT  37.381 24.48 37.508 32.568 ;
     RECT  36.853 33.6 37.508 35.496 ;
     RECT  37.069 36.624 37.508 46.632 ;
     RECT  37.069 47.616 37.508 49.608 ;
     RECT  36.817 50.688 37.508 53.064 ;
     RECT  37.033 54.432 37.508 58.392 ;
     RECT  37.213 59.568 37.508 63.24 ;
     RECT  37.069 64.704 37.508 65.688 ;
     RECT  36.469 66.672 37.508 66.696 ;
     RECT  36.515 68.208 37.508 68.76 ;
     RECT  37.381 70.08 37.508 70.296 ;
     RECT  37.381 71.376 37.508 73.56 ;
     RECT  37.508 2.148 37.612 75.612 ;
     RECT  37.612 2.418 37.804 75.342 ;
     RECT  37.804 29.232 37.829 45.048 ;
     RECT  37.804 49.584 37.865 53.064 ;
     RECT  37.804 6.816 37.901 7.656 ;
     RECT  37.804 15.552 37.955 28.152 ;
     RECT  37.955 16.08 38.009 28.152 ;
     RECT  37.804 58.128 38.009 59.592 ;
     RECT  37.804 73.536 38.009 73.8 ;
     RECT  37.829 29.808 38.225 45.048 ;
     RECT  37.865 50.016 38.405 53.064 ;
     RECT  38.009 16.08 38.441 25.224 ;
     RECT  37.804 11.664 38.449 13.128 ;
     RECT  38.225 29.808 38.477 42.792 ;
     RECT  38.477 29.808 38.531 38.952 ;
     RECT  38.531 31.392 38.585 38.952 ;
     RECT  37.804 64.944 38.613 65.688 ;
     RECT  38.531 29.808 38.621 30.072 ;
     RECT  38.585 31.824 38.621 38.952 ;
     RECT  38.621 30.048 38.657 30.072 ;
     RECT  38.009 58.128 38.665 59.448 ;
     RECT  38.449 11.664 38.729 12.552 ;
     RECT  38.405 50.016 38.729 52.536 ;
     RECT  38.225 43.872 38.765 45.048 ;
     RECT  38.729 50.016 38.765 52.44 ;
     RECT  37.804 10.272 38.771 10.536 ;
     RECT  38.665 59.136 38.771 59.448 ;
     RECT  37.804 60.912 38.771 61.032 ;
     RECT  37.804 67.44 38.771 68.232 ;
     RECT  38.771 10.32 38.801 10.536 ;
     RECT  38.771 61.008 38.801 61.032 ;
     RECT  38.009 73.776 38.801 73.8 ;
     RECT  38.621 31.824 38.819 34.488 ;
     RECT  37.804 46.368 38.837 48.168 ;
     RECT  38.765 52.416 38.837 52.44 ;
     RECT  37.804 55.68 38.873 56.712 ;
     RECT  38.771 59.136 38.873 59.16 ;
     RECT  38.771 67.44 38.873 67.464 ;
     RECT  37.804 71.376 38.873 71.4 ;
     RECT  38.009 26.208 38.905 28.152 ;
     RECT  37.901 6.816 38.909 6.84 ;
     RECT  38.621 35.472 38.909 38.952 ;
     RECT  38.765 43.872 38.909 44.328 ;
     RECT  38.837 46.368 38.941 47.88 ;
     RECT  38.801 10.32 38.945 10.344 ;
     RECT  37.804 54.672 38.945 54.696 ;
     RECT  38.477 42.72 38.981 42.792 ;
     RECT  37.804 62.688 39.017 62.712 ;
     RECT  38.941 46.128 39.049 47.88 ;
     RECT  38.441 16.08 39.053 20.424 ;
     RECT  39.049 45.792 39.053 47.88 ;
     RECT  38.909 36.528 39.161 38.952 ;
     RECT  38.765 50.016 39.161 51.192 ;
     RECT  39.161 50.016 39.164 50.136 ;
     RECT  39.053 16.08 39.205 17.592 ;
     RECT  38.909 43.872 39.409 44.184 ;
     RECT  37.804 14.496 39.733 14.52 ;
     RECT  39.205 15.984 39.733 17.592 ;
     RECT  39.053 47.328 39.805 47.88 ;
     RECT  38.819 32.064 40.069 34.488 ;
     RECT  39.205 6.24 40.208 6.264 ;
     RECT  38.729 12.528 40.208 12.552 ;
     RECT  39.733 14.496 40.208 17.592 ;
     RECT  39.053 18.672 40.208 20.424 ;
     RECT  38.441 21.408 40.208 25.224 ;
     RECT  38.905 26.208 40.208 29.064 ;
     RECT  40.069 31.92 40.208 34.488 ;
     RECT  38.909 35.472 40.208 35.496 ;
     RECT  39.161 36.816 40.208 38.952 ;
     RECT  38.477 40.704 40.208 41.448 ;
     RECT  39.409 43.104 40.208 44.184 ;
     RECT  39.053 45.792 40.208 46.152 ;
     RECT  39.805 47.328 40.208 48.408 ;
     RECT  39.164 49.392 40.208 50.136 ;
     RECT  38.873 55.68 40.208 56.376 ;
     RECT  38.665 58.128 40.208 58.152 ;
     RECT  38.613 64.944 40.208 64.968 ;
     RECT  40.208 2.148 40.312 75.612 ;
     RECT  40.312 2.418 40.504 75.342 ;
     RECT  40.504 44.16 40.601 44.184 ;
     RECT  40.504 48.384 40.601 48.408 ;
     RECT  40.504 47.328 40.637 47.352 ;
     RECT  40.504 38.16 40.739 39.384 ;
     RECT  40.504 4.656 41.569 4.68 ;
     RECT  40.504 8.88 41.569 9.432 ;
     RECT  40.504 18.912 41.569 18.936 ;
     RECT  40.504 52.992 41.569 53.016 ;
     RECT  40.504 56.16 41.569 56.184 ;
     RECT  41.533 60.384 41.569 60.408 ;
     RECT  41.533 62.496 41.569 62.52 ;
     RECT  40.504 64.608 41.569 64.632 ;
     RECT  40.504 68.832 41.569 68.856 ;
     RECT  40.504 69.888 41.569 70.44 ;
     RECT  41.569 8.88 41.605 9.96 ;
     RECT  41.569 10.992 41.605 11.016 ;
     RECT  41.569 47.712 41.605 49.32 ;
     RECT  40.504 3.6 41.821 3.624 ;
     RECT  41.569 4.656 41.821 7.848 ;
     RECT  41.569 15.216 41.821 15.768 ;
     RECT  41.569 16.8 41.821 16.824 ;
     RECT  41.569 18.912 41.821 19.464 ;
     RECT  41.569 22.08 41.821 22.104 ;
     RECT  41.569 25.776 41.821 26.328 ;
     RECT  41.569 34.224 41.821 34.248 ;
     RECT  41.569 42.432 41.821 42.456 ;
     RECT  41.569 50.88 41.821 51.432 ;
     RECT  41.569 55.104 41.821 56.184 ;
     RECT  41.569 57.216 41.821 58.296 ;
     RECT  41.569 61.968 41.821 64.632 ;
     RECT  41.569 65.664 41.821 65.688 ;
     RECT  41.569 68.832 41.821 70.968 ;
     RECT  41.569 72 41.821 73.08 ;
     RECT  41.569 24.192 41.893 24.216 ;
     RECT  41.569 28.944 41.893 28.968 ;
     RECT  41.569 30.528 41.893 31.608 ;
     RECT  41.569 66.72 41.893 67.8 ;
     RECT  41.821 68.832 41.893 73.08 ;
     RECT  41.821 3.6 42.145 7.848 ;
     RECT  41.605 8.88 42.145 11.016 ;
     RECT  41.569 12.048 42.145 12.072 ;
     RECT  41.821 15.216 42.145 17.352 ;
     RECT  41.821 18.912 42.145 19.992 ;
     RECT  41.821 21.552 42.145 22.104 ;
     RECT  41.893 24.192 42.145 24.744 ;
     RECT  41.821 25.776 42.145 26.856 ;
     RECT  41.893 28.944 42.145 29.496 ;
     RECT  41.893 30.528 42.145 32.136 ;
     RECT  41.821 33.696 42.145 34.248 ;
     RECT  41.821 41.904 42.145 42.456 ;
     RECT  41.821 44.544 42.145 44.568 ;
     RECT  41.821 45.6 42.145 45.624 ;
     RECT  41.605 47.184 42.145 49.32 ;
     RECT  41.821 50.88 42.145 51.96 ;
     RECT  41.569 52.992 42.145 53.544 ;
     RECT  41.821 55.104 42.145 58.296 ;
     RECT  41.821 61.968 42.145 65.688 ;
     RECT  41.893 66.72 42.145 73.08 ;
     RECT  41.569 74.112 42.145 74.136 ;
     RECT  42.145 21.552 42.181 32.136 ;
     RECT  42.145 33.168 42.181 36.36 ;
     RECT  41.569 59.328 42.181 60.936 ;
     RECT  42.145 61.968 42.181 74.136 ;
     RECT  42.145 41.376 43.009 45.624 ;
     RECT  42.145 46.656 43.009 58.296 ;
     RECT  42.145 3.6 43.081 12.072 ;
     RECT  42.145 13.104 43.081 19.992 ;
     RECT  42.181 21.552 43.081 36.36 ;
     RECT  40.739 38.736 43.081 39.384 ;
     RECT  43.009 41.376 43.081 58.296 ;
     RECT  42.181 59.328 43.081 74.136 ;
     RECT  43.081 38.352 43.121 39.384 ;
     RECT  43.081 3.6 43.164 36.36 ;
     RECT  43.121 38.352 43.164 38.376 ;
     RECT  43.121 39.36 43.164 39.384 ;
     RECT  43.081 41.376 43.164 74.136 ;
    LAYER M5 ;
     RECT  6.432 0.016 12.696 0.131 ;
     RECT  6.528 0.131 12.696 0.565 ;
     RECT  6.528 0.565 13.032 2.137 ;
     RECT  21.552 0.016 21.576 2.137 ;
     RECT  2.4 2.137 2.52 2.151 ;
     RECT  5.1 2.137 5.22 2.151 ;
     RECT  6.528 2.137 13.32 2.151 ;
     RECT  15.9 2.137 16.02 2.151 ;
     RECT  18.6 2.137 18.72 2.151 ;
     RECT  21.3 2.137 21.576 2.151 ;
     RECT  24 2.137 24.12 2.151 ;
     RECT  26.7 2.137 26.82 2.151 ;
     RECT  29.4 2.137 29.52 2.151 ;
     RECT  32.1 2.137 32.22 2.151 ;
     RECT  34.8 2.137 34.92 2.151 ;
     RECT  37.5 2.137 37.62 2.151 ;
     RECT  40.2 2.137 40.32 2.151 ;
     RECT  6.528 2.151 13.512 2.867 ;
     RECT  15.9 2.151 16.212 2.869 ;
     RECT  26.7 2.151 27.012 3.349 ;
     RECT  32.1 2.151 32.412 3.397 ;
     RECT  29.4 2.151 29.712 3.589 ;
     RECT  31.344 3.397 32.412 3.589 ;
     RECT  15.744 2.869 16.212 3.877 ;
     RECT  6.816 2.867 13.512 4.019 ;
     RECT  15.744 3.877 16.584 4.115 ;
     RECT  29.4 3.589 32.412 4.643 ;
     RECT  7.68 4.019 13.512 4.837 ;
     RECT  36.432 3.157 36.456 5.171 ;
     RECT  25.968 3.349 27.012 5.459 ;
     RECT  18.6 2.151 18.912 5.509 ;
     RECT  24 2.151 24.312 5.557 ;
     RECT  34.8 2.151 35.112 5.653 ;
     RECT  29.4 4.643 30.648 5.747 ;
     RECT  18.432 5.509 18.912 5.797 ;
     RECT  7.68 4.837 13.992 5.843 ;
     RECT  33.936 5.653 35.112 5.845 ;
     RECT  36.384 5.365 36.408 5.845 ;
     RECT  15.9 4.115 16.584 6.035 ;
     RECT  18.384 5.797 18.912 6.085 ;
     RECT  40.2 2.151 40.512 6.229 ;
     RECT  5.1 2.151 5.412 6.277 ;
     RECT  24 5.557 24.408 6.277 ;
     RECT  18.384 6.085 19.032 6.805 ;
     RECT  37.5 2.151 37.812 6.805 ;
     RECT  39.216 6.229 40.512 6.805 ;
     RECT  5.1 6.277 5.544 6.899 ;
     RECT  33.936 5.845 36.408 7.139 ;
     RECT  15.9 6.035 16.212 7.189 ;
     RECT  37.5 6.805 40.512 7.189 ;
     RECT  29.4 5.747 30.6 7.333 ;
     RECT  29.28 7.333 30.6 7.379 ;
     RECT  17.28 6.805 19.032 7.381 ;
     RECT  10.032 5.843 13.992 7.619 ;
     RECT  31.968 4.643 32.412 7.621 ;
     RECT  17.28 7.381 19.464 7.957 ;
     RECT  7.68 5.843 8.904 8.003 ;
     RECT  7.68 8.003 8.616 8.485 ;
     RECT  11.952 7.619 13.992 8.579 ;
     RECT  12.048 8.579 13.992 8.627 ;
     RECT  7.392 8.485 8.616 8.869 ;
     RECT  21.3 2.151 21.612 9.109 ;
     RECT  23.616 6.277 24.408 9.155 ;
     RECT  21.168 9.109 21.612 9.205 ;
     RECT  33.936 7.139 36.12 9.301 ;
     RECT  10.032 7.619 10.812 9.347 ;
     RECT  21.168 9.205 21.72 9.349 ;
     RECT  31.968 7.621 32.808 9.493 ;
     RECT  15.792 7.189 16.212 9.539 ;
     RECT  5.1 6.899 5.412 9.637 ;
     RECT  6.768 8.869 8.616 9.779 ;
     RECT  6.768 9.779 8.112 9.827 ;
     RECT  10.272 9.347 10.812 9.925 ;
     RECT  33.792 9.301 36.12 10.163 ;
     RECT  12.768 8.627 13.992 10.211 ;
     RECT  21.12 9.349 21.72 10.643 ;
     RECT  22.8 10.069 22.824 10.883 ;
     RECT  21.12 10.643 21.612 10.931 ;
     RECT  17.28 7.957 19.512 11.171 ;
     RECT  37.248 7.189 40.512 11.173 ;
     RECT  37.104 11.173 40.512 11.269 ;
     RECT  10.272 9.925 11.64 11.365 ;
     RECT  31.872 9.493 32.808 11.413 ;
     RECT  33.792 10.163 35.352 11.413 ;
     RECT  31.872 11.413 35.352 11.555 ;
     RECT  6.768 9.827 6.792 11.747 ;
     RECT  5.1 9.637 5.784 11.797 ;
     RECT  9.888 11.365 11.64 11.941 ;
     RECT  33.792 11.555 35.352 11.941 ;
     RECT  37.056 11.269 40.512 11.941 ;
     RECT  24 9.155 24.408 11.989 ;
     RECT  29.28 7.379 29.712 12.083 ;
     RECT  17.328 11.171 19.512 12.227 ;
     RECT  31.872 11.555 32.808 12.227 ;
     RECT  15.9 9.539 16.212 12.517 ;
     RECT  29.4 12.083 29.712 12.517 ;
     RECT  31.968 12.227 32.808 12.563 ;
     RECT  33.792 11.941 40.512 12.563 ;
     RECT  5.1 11.797 6.744 12.755 ;
     RECT  7.8 9.827 8.112 12.901 ;
     RECT  9.504 11.941 11.64 12.901 ;
     RECT  37.248 12.563 40.512 13.139 ;
     RECT  17.712 12.227 19.512 13.333 ;
     RECT  37.248 13.139 37.812 13.475 ;
     RECT  21.3 10.931 21.612 13.717 ;
     RECT  17.712 13.333 19.608 13.763 ;
     RECT  33.792 12.563 36.168 13.861 ;
     RECT  37.344 13.475 37.812 13.907 ;
     RECT  12.768 10.211 13.944 14.053 ;
     RECT  12.768 14.053 14.856 14.195 ;
     RECT  7.8 12.901 11.64 14.197 ;
     RECT  21.168 13.717 21.612 14.291 ;
     RECT  7.8 14.197 11.688 14.387 ;
     RECT  31.968 12.563 32.412 14.435 ;
     RECT  26.7 5.459 27.012 14.485 ;
     RECT  33.648 13.861 36.168 14.819 ;
     RECT  33.792 14.819 36.168 15.155 ;
     RECT  29.4 12.517 30.264 15.157 ;
     RECT  17.712 13.763 19.512 15.443 ;
     RECT  37.392 13.907 37.812 15.541 ;
     RECT  12.768 14.195 14.232 15.827 ;
     RECT  21.3 14.291 21.612 15.829 ;
     RECT  15.9 12.517 16.728 15.973 ;
     RECT  17.712 15.443 19.272 15.973 ;
     RECT  24 11.989 24.504 16.019 ;
     RECT  29.28 15.157 30.264 16.499 ;
     RECT  33.888 15.155 36.168 16.549 ;
     RECT  15.9 15.973 19.272 16.595 ;
     RECT  37.392 15.541 37.944 16.595 ;
     RECT  39.216 13.139 40.512 16.741 ;
     RECT  29.28 16.499 29.712 16.883 ;
     RECT  21.3 15.829 22.584 16.931 ;
     RECT  39.12 16.741 40.512 17.123 ;
     RECT  33.888 16.549 36.264 17.509 ;
     RECT  24 16.019 24.312 17.605 ;
     RECT  33.888 17.509 36.312 17.651 ;
     RECT  39.264 17.123 40.512 18.181 ;
     RECT  24 17.605 24.408 18.275 ;
     RECT  37.5 16.595 37.812 18.661 ;
     RECT  38.976 18.181 40.512 18.661 ;
     RECT  12.768 15.827 13.944 18.757 ;
     RECT  33.984 17.651 36.312 19.237 ;
     RECT  37.5 18.661 40.512 19.237 ;
     RECT  12.768 18.757 14.808 19.283 ;
     RECT  21.3 16.931 21.612 19.909 ;
     RECT  32.1 14.435 32.412 20.245 ;
     RECT  33.984 19.237 40.512 20.339 ;
     RECT  7.8 14.387 9.528 20.389 ;
     RECT  10.5 14.387 11.688 20.389 ;
     RECT  34.8 20.339 40.512 20.531 ;
     RECT  21.3 19.909 22.392 20.821 ;
     RECT  7.8 20.389 11.688 21.011 ;
     RECT  21.3 20.821 22.584 21.347 ;
     RECT  34.8 20.531 36.264 21.541 ;
     RECT  37.5 20.531 40.512 21.541 ;
     RECT  12.768 19.283 13.944 22.165 ;
     RECT  34.8 21.541 40.512 22.549 ;
     RECT  29.4 16.883 29.712 22.597 ;
     RECT  31.248 20.245 32.412 22.597 ;
     RECT  29.4 22.597 32.412 22.739 ;
     RECT  30.768 22.739 32.412 22.835 ;
     RECT  12.768 22.165 14.904 23.125 ;
     RECT  15.9 16.595 18.912 23.125 ;
     RECT  12.768 23.125 18.912 23.939 ;
     RECT  33.888 22.549 40.512 23.987 ;
     RECT  24 18.275 24.312 24.421 ;
     RECT  23.808 24.421 24.312 24.469 ;
     RECT  26.7 14.485 27.624 24.469 ;
     RECT  12.768 23.939 16.728 24.899 ;
     RECT  21.3 21.347 22.392 24.949 ;
     RECT  23.808 24.469 24.792 24.949 ;
     RECT  31.248 22.835 32.412 24.995 ;
     RECT  33.888 23.987 35.256 25.045 ;
     RECT  36.24 23.987 40.512 25.045 ;
     RECT  26.352 24.469 27.624 25.141 ;
     RECT  21.3 24.949 24.792 25.621 ;
     RECT  20.544 25.621 24.792 25.715 ;
     RECT  26.208 25.141 27.624 25.763 ;
     RECT  31.92 24.995 32.412 25.955 ;
     RECT  22.896 25.715 24.792 26.819 ;
     RECT  26.208 25.763 27.144 27.205 ;
     RECT  12.768 24.899 14.904 27.251 ;
     RECT  17.712 23.939 18.912 27.395 ;
     RECT  18.48 27.395 18.912 27.685 ;
     RECT  18.48 27.685 19.272 27.781 ;
     RECT  20.544 25.715 21.612 27.781 ;
     RECT  29.4 22.739 29.712 27.877 ;
     RECT  26.208 27.205 27.48 27.971 ;
     RECT  24 26.819 24.792 28.019 ;
     RECT  18.48 27.781 21.612 28.499 ;
     RECT  26.352 27.971 27.48 29.075 ;
     RECT  33.888 25.045 40.512 29.075 ;
     RECT  18.6 28.499 21.612 29.123 ;
     RECT  28.848 27.877 29.712 29.123 ;
     RECT  32.1 25.955 32.412 29.461 ;
     RECT  31.536 29.461 32.412 29.509 ;
     RECT  31.536 29.509 32.808 29.605 ;
     RECT  7.8 21.011 11.016 29.653 ;
     RECT  19.92 29.123 21.612 29.699 ;
     RECT  24 28.019 24.312 29.749 ;
     RECT  26.352 29.075 27.144 29.795 ;
     RECT  12.768 27.251 13.944 30.037 ;
     RECT  18.6 29.123 18.912 30.133 ;
     RECT  22.896 26.819 22.92 30.709 ;
     RECT  24 29.749 24.504 30.709 ;
     RECT  18.192 30.133 19.464 30.803 ;
     RECT  30.72 29.605 32.808 30.803 ;
     RECT  7.8 29.653 11.448 31.189 ;
     RECT  26.352 29.795 27.012 31.189 ;
     RECT  12.768 30.037 14.52 31.237 ;
     RECT  31.632 30.803 32.808 31.331 ;
     RECT  7.584 31.189 11.448 31.379 ;
     RECT  22.896 30.709 24.504 31.427 ;
     RECT  26.352 31.189 27.96 31.427 ;
     RECT  33.888 29.075 38.568 31.813 ;
     RECT  12.768 31.237 14.808 31.955 ;
     RECT  33.888 31.813 38.808 32.245 ;
     RECT  39.936 29.075 40.512 32.245 ;
     RECT  12.768 31.955 13.944 32.341 ;
     RECT  20.448 29.699 21.612 32.483 ;
     RECT  29.4 29.123 29.712 32.485 ;
     RECT  18.6 30.803 19.464 32.531 ;
     RECT  15.9 24.899 16.728 32.725 ;
     RECT  29.088 32.485 29.712 32.821 ;
     RECT  29.088 32.821 30.264 32.963 ;
     RECT  24 31.427 24.504 33.059 ;
     RECT  33.888 32.245 40.512 33.347 ;
     RECT  21.3 32.483 21.612 33.637 ;
     RECT  34.176 33.347 40.512 33.683 ;
     RECT  12.144 32.341 13.944 34.163 ;
     RECT  24 33.059 24.408 34.165 ;
     RECT  26.7 31.427 27.96 34.165 ;
     RECT  29.4 32.963 30.264 34.355 ;
     RECT  26.7 34.165 28.008 34.453 ;
     RECT  26.7 34.453 28.2 34.499 ;
     RECT  12.336 34.163 13.944 34.741 ;
     RECT  26.7 34.499 27.012 34.741 ;
     RECT  34.176 33.683 38.808 34.789 ;
     RECT  20.448 33.637 21.612 34.835 ;
     RECT  24 34.165 24.552 34.835 ;
     RECT  15.9 32.725 16.872 34.931 ;
     RECT  7.584 31.379 11.016 35.315 ;
     RECT  27.984 34.499 28.2 35.461 ;
     RECT  29.4 34.355 29.712 35.461 ;
     RECT  26.256 34.741 27.012 35.557 ;
     RECT  27.984 35.461 29.712 35.557 ;
     RECT  33.984 34.789 38.808 35.603 ;
     RECT  7.8 35.315 11.016 35.939 ;
     RECT  12.336 34.741 14.28 36.373 ;
     RECT  24 34.835 24.456 36.467 ;
     RECT  26.256 35.557 29.712 36.515 ;
     RECT  7.8 35.939 8.856 36.707 ;
     RECT  32.1 31.331 32.808 36.757 ;
     RECT  15.9 34.931 16.728 37.235 ;
     RECT  18.6 32.531 18.912 37.573 ;
     RECT  19.968 37.045 19.992 37.573 ;
     RECT  18.6 37.573 19.992 37.619 ;
     RECT  12.336 36.373 14.808 37.667 ;
     RECT  32.1 36.757 33.24 37.669 ;
     RECT  31.968 37.669 33.24 37.715 ;
     RECT  12.768 37.667 14.808 37.859 ;
     RECT  26.7 36.515 29.712 38.147 ;
     RECT  39.936 33.683 40.512 38.149 ;
     RECT  24 36.467 24.408 38.243 ;
     RECT  34.224 35.603 38.808 38.245 ;
     RECT  28.56 38.147 29.712 38.533 ;
     RECT  22.896 31.427 22.92 38.581 ;
     RECT  24 38.243 24.312 38.581 ;
     RECT  28.56 38.533 30.6 38.771 ;
     RECT  28.56 38.771 29.712 38.867 ;
     RECT  39.936 38.149 40.728 38.867 ;
     RECT  31.968 37.715 32.808 38.963 ;
     RECT  22.896 38.581 24.312 39.301 ;
     RECT  26.7 38.147 27.012 39.301 ;
     RECT  31.968 38.963 32.412 39.395 ;
     RECT  40.2 38.867 40.728 39.395 ;
     RECT  22.896 39.301 24.408 39.683 ;
     RECT  33.792 38.245 38.808 39.731 ;
     RECT  12.768 37.859 13.944 40.405 ;
     RECT  26.7 39.301 27.576 40.405 ;
     RECT  26.592 40.405 27.576 40.595 ;
     RECT  21.3 34.835 21.612 40.597 ;
     RECT  5.1 12.755 5.784 41.173 ;
     RECT  18.6 37.619 19.176 41.509 ;
     RECT  24 39.683 24.408 41.603 ;
     RECT  28.8 38.867 29.712 41.651 ;
     RECT  20.736 40.597 21.612 41.939 ;
     RECT  12.768 40.405 14.904 42.133 ;
     RECT  26.592 40.595 27.012 42.133 ;
     RECT  34.608 39.731 38.808 42.133 ;
     RECT  29.04 41.651 29.712 42.179 ;
     RECT  31.008 40.021 31.032 42.179 ;
     RECT  34.56 42.133 38.808 42.563 ;
     RECT  7.8 36.707 8.664 42.709 ;
     RECT  10.032 35.939 11.016 42.709 ;
     RECT  21.3 41.939 21.612 42.709 ;
     RECT  22.896 39.683 22.92 42.709 ;
     RECT  17.664 41.509 19.176 42.755 ;
     RECT  34.56 42.563 35.976 42.803 ;
     RECT  17.664 42.755 18.912 42.995 ;
     RECT  29.4 42.179 29.712 43.141 ;
     RECT  32.1 39.395 32.412 43.333 ;
     RECT  7.8 42.709 11.016 43.717 ;
     RECT  21.3 42.709 22.92 43.763 ;
     RECT  34.8 42.803 35.976 43.813 ;
     RECT  29.4 43.141 30.408 43.907 ;
     RECT  7.632 43.717 11.016 43.909 ;
     RECT  12 42.133 14.904 43.909 ;
     RECT  34.704 43.813 35.976 44.389 ;
     RECT  37.104 42.563 38.808 44.389 ;
     RECT  7.632 43.909 14.904 44.435 ;
     RECT  15.9 37.235 16.212 44.437 ;
     RECT  4.992 41.173 5.784 44.483 ;
     RECT  34.704 44.389 38.808 44.483 ;
     RECT  26.592 42.133 27.288 44.867 ;
     RECT  31.968 43.333 32.412 44.915 ;
     RECT  15.9 44.437 17.016 44.917 ;
     RECT  7.632 44.435 11.256 45.059 ;
     RECT  15.9 44.917 17.112 45.059 ;
     RECT  34.8 44.483 38.808 45.059 ;
     RECT  3.936 43.861 3.96 45.299 ;
     RECT  15.9 45.059 17.016 45.683 ;
     RECT  7.632 45.059 11.016 45.731 ;
     RECT  26.592 44.867 27.012 45.827 ;
     RECT  29.4 43.907 29.712 46.069 ;
     RECT  7.8 45.731 11.016 46.117 ;
     RECT  12.768 44.435 14.904 46.117 ;
     RECT  7.8 46.117 14.904 46.211 ;
     RECT  22.896 43.763 22.92 46.693 ;
     RECT  24 41.603 24.312 46.693 ;
     RECT  25.536 44.437 25.56 46.787 ;
     RECT  29.4 46.069 30.696 46.787 ;
     RECT  34.8 45.059 35.976 46.787 ;
     RECT  5.1 44.483 5.784 47.029 ;
     RECT  21.3 43.763 21.612 47.269 ;
     RECT  22.896 46.693 24.312 47.269 ;
     RECT  7.8 46.211 14.568 47.363 ;
     RECT  28.224 46.069 28.248 47.363 ;
     RECT  37.392 45.059 38.808 47.749 ;
     RECT  5.1 47.029 6.312 47.845 ;
     RECT  33.744 47.077 33.768 47.845 ;
     RECT  34.8 46.787 35.736 47.845 ;
     RECT  36.96 47.749 38.808 47.939 ;
     RECT  26.7 45.827 27.012 48.181 ;
     RECT  21.3 47.269 24.312 48.419 ;
     RECT  33.744 47.845 35.736 48.419 ;
     RECT  15.9 45.683 16.212 48.421 ;
     RECT  26.592 48.181 27.012 48.421 ;
     RECT  34.368 48.419 35.736 48.515 ;
     RECT  5.1 47.845 6.36 48.899 ;
     RECT  32.1 44.915 32.412 48.949 ;
     RECT  28.32 47.845 28.344 49.043 ;
     RECT  25.68 48.421 27.012 49.187 ;
     RECT  34.368 48.515 35.112 49.187 ;
     RECT  13.2 47.363 14.568 49.381 ;
     RECT  37.392 47.939 38.808 49.381 ;
     RECT  40.2 39.395 40.512 49.381 ;
     RECT  18.6 42.995 18.912 49.477 ;
     RECT  15.9 48.421 16.44 49.909 ;
     RECT  26.592 49.187 27.012 50.051 ;
     RECT  34.8 49.187 35.112 50.101 ;
     RECT  37.392 49.381 40.512 50.101 ;
     RECT  36.432 50.101 40.512 50.147 ;
     RECT  7.8 47.363 11.976 50.389 ;
     RECT  13.2 49.381 14.616 50.389 ;
     RECT  26.7 50.051 27.012 50.389 ;
     RECT  28.368 49.333 28.392 50.389 ;
     RECT  7.8 50.389 14.616 50.435 ;
     RECT  29.4 46.787 29.712 50.533 ;
     RECT  18.6 49.477 19.176 50.579 ;
     RECT  5.1 48.899 5.784 50.677 ;
     RECT  34.8 50.101 35.352 50.771 ;
     RECT  36.432 50.147 38.808 50.867 ;
     RECT  36.432 50.867 37.812 50.915 ;
     RECT  22.896 48.419 24.312 51.205 ;
     RECT  26.7 50.389 28.392 51.299 ;
     RECT  28.368 51.299 28.392 51.347 ;
     RECT  34.8 50.771 35.112 51.493 ;
     RECT  31.872 48.949 32.412 51.541 ;
     RECT  7.8 50.435 11.016 51.683 ;
     RECT  7.8 51.683 8.712 51.733 ;
     RECT  26.7 51.299 27.384 51.923 ;
     RECT  36.816 50.915 37.812 51.923 ;
     RECT  34.656 51.493 35.112 51.925 ;
     RECT  22.896 51.205 24.456 52.019 ;
     RECT  31.392 51.541 32.412 52.021 ;
     RECT  21.3 48.419 21.612 52.069 ;
     RECT  12.816 50.435 14.616 52.213 ;
     RECT  23.328 52.019 24.456 52.307 ;
     RECT  12.528 52.213 14.856 52.403 ;
     RECT  23.472 52.307 24.456 52.499 ;
     RECT  37.152 51.923 37.812 52.547 ;
     RECT  31.392 52.021 33.048 52.739 ;
     RECT  10.032 51.683 11.016 52.789 ;
     RECT  29.4 50.533 30.072 52.789 ;
     RECT  31.392 52.739 32.412 52.789 ;
     RECT  4.992 50.677 5.784 52.981 ;
     RECT  20.544 52.069 21.612 53.027 ;
     RECT  34.08 51.925 35.112 53.075 ;
     RECT  37.392 52.547 37.812 53.075 ;
     RECT  3.792 49.525 3.816 53.219 ;
     RECT  7.44 51.733 8.712 53.219 ;
     RECT  15.9 49.909 16.776 53.219 ;
     RECT  23.904 52.499 24.456 53.219 ;
     RECT  7.8 53.219 8.712 53.507 ;
     RECT  23.904 53.219 24.408 53.509 ;
     RECT  4.992 52.981 5.88 53.603 ;
     RECT  10.032 52.789 11.4 53.893 ;
     RECT  26.7 51.923 27.012 53.941 ;
     RECT  9.648 53.893 11.4 54.037 ;
     RECT  12.528 52.403 13.944 54.037 ;
     RECT  4.992 53.603 5.784 54.325 ;
     RECT  29.4 52.789 32.412 54.563 ;
     RECT  9.648 54.037 13.944 54.707 ;
     RECT  22.752 53.509 24.408 54.755 ;
     RECT  33.6 53.509 33.624 54.899 ;
     RECT  23.328 54.755 24.312 54.947 ;
     RECT  9.696 54.707 12.024 55.187 ;
     RECT  34.656 53.075 35.112 55.237 ;
     RECT  37.5 53.075 37.812 55.237 ;
     RECT  13.2 54.707 13.944 55.525 ;
     RECT  26.7 53.941 27.144 55.573 ;
     RECT  12 55.187 12.024 55.667 ;
     RECT  26.4 55.573 27.144 55.715 ;
     RECT  37.008 55.237 37.812 55.715 ;
     RECT  34.032 55.237 35.112 56.291 ;
     RECT  9.696 55.187 10.812 56.483 ;
     RECT  38.784 50.867 38.808 56.531 ;
     RECT  13.2 55.525 14.76 56.725 ;
     RECT  4.896 54.325 5.784 56.965 ;
     RECT  10.032 56.483 10.812 56.965 ;
     RECT  26.4 55.715 27.012 57.109 ;
     RECT  4.896 56.965 5.832 57.157 ;
     RECT  25.92 57.109 27.012 57.251 ;
     RECT  4.896 57.157 5.88 57.445 ;
     RECT  29.4 54.563 30.456 57.541 ;
     RECT  19.968 56.101 19.992 57.635 ;
     RECT  26.4 57.251 27.012 57.635 ;
     RECT  34.8 56.291 35.112 57.781 ;
     RECT  34.8 57.781 35.496 57.923 ;
     RECT  28.464 57.541 30.456 58.021 ;
     RECT  37.296 55.715 37.812 58.117 ;
     RECT  3.984 57.445 5.88 58.163 ;
     RECT  10.032 56.965 11.208 58.403 ;
     RECT  24 54.947 24.312 58.453 ;
     RECT  5.1 58.163 5.88 58.981 ;
     RECT  28.464 58.021 30.504 58.981 ;
     RECT  7.8 53.507 8.664 59.029 ;
     RECT  10.032 58.403 10.812 59.029 ;
     RECT  28.464 58.981 30.84 59.267 ;
     RECT  33.792 58.069 33.816 59.267 ;
     RECT  3.984 58.163 4.008 59.315 ;
     RECT  13.104 56.725 14.76 59.315 ;
     RECT  12 59.029 12.12 59.507 ;
     RECT  18.6 50.579 18.912 59.749 ;
     RECT  7.8 59.029 10.812 59.891 ;
     RECT  34.8 57.923 35.112 60.037 ;
     RECT  13.2 59.315 14.76 60.275 ;
     RECT  37.296 58.117 38.76 60.277 ;
     RECT  7.8 59.891 9.096 60.373 ;
     RECT  26.7 57.635 27.012 60.373 ;
     RECT  29.4 59.267 30.84 60.659 ;
     RECT  37.2 60.277 38.76 60.709 ;
     RECT  7.68 60.373 9.096 60.851 ;
     RECT  36.432 60.709 38.76 60.947 ;
     RECT  5.1 58.981 6.024 61.043 ;
     RECT  14.736 60.275 14.76 61.043 ;
     RECT  36.432 60.947 38.616 61.043 ;
     RECT  18.096 59.749 18.912 61.139 ;
     RECT  34.8 60.037 35.256 61.427 ;
     RECT  7.68 60.851 8.712 61.477 ;
     RECT  5.1 61.043 5.832 61.619 ;
     RECT  12 59.507 12.024 61.619 ;
     RECT  21.3 53.027 21.612 62.053 ;
     RECT  15.9 53.219 16.212 62.101 ;
     RECT  34.8 61.427 35.112 62.149 ;
     RECT  6.912 61.477 8.712 62.195 ;
     RECT  29.4 60.659 30.504 62.195 ;
     RECT  36.432 61.043 37.812 62.435 ;
     RECT  36.48 62.435 37.812 62.531 ;
     RECT  5.1 61.619 5.412 62.629 ;
     RECT  15.504 62.101 16.212 62.629 ;
     RECT  29.4 62.195 29.712 62.629 ;
     RECT  26.7 60.373 27.384 62.723 ;
     RECT  13.2 60.275 13.608 62.725 ;
     RECT  32.1 54.563 32.412 62.725 ;
     RECT  6.912 62.195 8.568 62.771 ;
     RECT  13.104 62.725 13.608 62.771 ;
     RECT  32.1 62.725 32.568 62.917 ;
     RECT  21.072 62.053 21.612 63.205 ;
     RECT  31.824 62.917 32.568 63.347 ;
     RECT  21.072 63.205 22.296 63.637 ;
     RECT  26.7 62.723 27.012 63.637 ;
     RECT  7.68 62.771 8.568 63.779 ;
     RECT  10.5 59.891 10.812 63.781 ;
     RECT  18.6 61.139 18.912 63.781 ;
     RECT  34.464 62.149 35.112 63.781 ;
     RECT  23.52 58.453 24.312 63.829 ;
     RECT  26.16 63.637 27.012 63.829 ;
     RECT  31.968 63.347 32.568 63.875 ;
     RECT  15.504 62.629 16.728 64.067 ;
     RECT  20.592 63.637 22.296 64.067 ;
     RECT  32.1 63.875 32.568 64.309 ;
     RECT  10.5 63.781 11.784 64.451 ;
     RECT  36.48 62.531 36.504 64.595 ;
     RECT  23.52 63.829 27.012 64.741 ;
     RECT  32.1 64.309 32.712 64.885 ;
     RECT  13.104 62.771 13.512 64.933 ;
     RECT  37.5 62.531 37.812 64.933 ;
     RECT  20.592 64.067 21.612 65.027 ;
     RECT  23.52 64.741 27.48 65.027 ;
     RECT  34.224 63.781 35.112 65.267 ;
     RECT  13.104 64.933 13.608 65.603 ;
     RECT  15.9 64.067 16.728 65.603 ;
     RECT  23.52 65.027 25.224 65.603 ;
     RECT  29.088 62.629 29.712 65.603 ;
     RECT  31.872 64.885 32.712 65.603 ;
     RECT  31.872 65.603 32.412 65.699 ;
     RECT  37.5 64.933 38.568 65.699 ;
     RECT  15.9 65.603 16.212 65.941 ;
     RECT  13.104 65.603 13.512 65.987 ;
     RECT  5.1 62.629 5.544 66.037 ;
     RECT  4.992 66.037 5.544 66.083 ;
     RECT  7.68 63.779 8.112 66.085 ;
     RECT  24 65.603 25.224 66.131 ;
     RECT  26.7 65.027 27.48 66.229 ;
     RECT  18.384 63.781 18.912 66.707 ;
     RECT  26.496 66.229 27.48 66.901 ;
     RECT  13.2 65.987 13.512 67.237 ;
     RECT  33.408 66.565 33.432 67.283 ;
     RECT  4.992 66.083 5.412 67.427 ;
     RECT  37.5 65.699 37.812 67.429 ;
     RECT  18.6 66.707 18.912 67.669 ;
     RECT  26.352 66.901 27.48 67.717 ;
     RECT  15.216 65.941 16.212 67.765 ;
     RECT  36.48 66.661 36.504 67.859 ;
     RECT  13.2 67.237 13.848 68.099 ;
     RECT  37.5 67.429 38.76 68.243 ;
     RECT  15.216 67.765 16.968 68.435 ;
     RECT  18.6 67.669 19.032 68.435 ;
     RECT  34.464 65.267 35.112 68.725 ;
     RECT  15.9 68.435 16.968 68.819 ;
     RECT  26.208 67.717 27.48 68.917 ;
     RECT  34.224 68.725 35.112 68.963 ;
     RECT  34.8 68.963 35.112 69.349 ;
     RECT  24 66.131 24.312 69.445 ;
     RECT  34.8 69.349 35.304 69.539 ;
     RECT  7.44 66.085 8.112 69.587 ;
     RECT  26.208 68.917 27.912 70.019 ;
     RECT  37.5 68.243 37.812 70.069 ;
     RECT  29.4 65.603 29.712 70.117 ;
     RECT  29.28 70.117 29.712 70.691 ;
     RECT  26.7 70.019 27.912 70.739 ;
     RECT  31.968 65.699 32.412 70.739 ;
     RECT  15.9 68.819 16.344 70.835 ;
     RECT  23.376 69.445 24.312 70.931 ;
     RECT  34.8 69.539 35.208 71.315 ;
     RECT  26.7 70.739 27.48 72.805 ;
     RECT  37.392 70.069 37.812 73.571 ;
     RECT  26.7 72.805 28.104 74.147 ;
     RECT  28.08 74.147 28.104 75.011 ;
     RECT  2.4 2.151 2.712 75.609 ;
     RECT  5.1 67.427 5.412 75.609 ;
     RECT  7.8 69.587 8.112 75.609 ;
     RECT  10.5 64.451 10.812 75.609 ;
     RECT  13.2 68.099 13.512 75.609 ;
     RECT  15.9 70.835 16.212 75.609 ;
     RECT  18.6 68.435 18.912 75.609 ;
     RECT  21.3 65.027 21.612 75.609 ;
     RECT  24 70.931 24.312 75.609 ;
     RECT  26.7 74.147 27.012 75.609 ;
     RECT  29.4 70.691 29.712 75.609 ;
     RECT  32.1 70.739 32.412 75.609 ;
     RECT  34.8 71.315 35.112 75.609 ;
     RECT  37.5 73.571 37.812 75.609 ;
     RECT  40.2 50.147 40.512 75.609 ;
     RECT  2.4 75.609 2.52 75.623 ;
     RECT  5.1 75.609 5.22 75.623 ;
     RECT  7.8 75.609 7.92 75.623 ;
     RECT  10.5 75.609 10.62 75.623 ;
     RECT  13.2 75.609 13.32 75.623 ;
     RECT  15.9 75.609 16.02 75.623 ;
     RECT  18.6 75.609 18.72 75.623 ;
     RECT  21.3 75.609 21.576 75.623 ;
     RECT  24 75.609 24.12 75.623 ;
     RECT  26.7 75.609 26.82 75.623 ;
     RECT  29.4 75.609 29.52 75.623 ;
     RECT  32.1 75.609 32.22 75.623 ;
     RECT  34.8 75.609 34.92 75.623 ;
     RECT  37.5 75.609 37.62 75.623 ;
     RECT  40.2 75.609 40.32 75.623 ;
     RECT  21.552 75.623 21.576 77.712 ;
  END
END dsfd_node_LLfd
END LIBRARY
